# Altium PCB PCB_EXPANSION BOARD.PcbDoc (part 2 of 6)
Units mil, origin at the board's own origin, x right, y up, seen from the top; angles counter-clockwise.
Board outline 5512.34 x 7953.29 mil, 6 copper layers (Top Layer, L2, L3, L4, L5, Bottom Layer); 420 components, 365 nets, 1860 pads, 895 vias.
Unrouted connection lines stored in the file: 9.

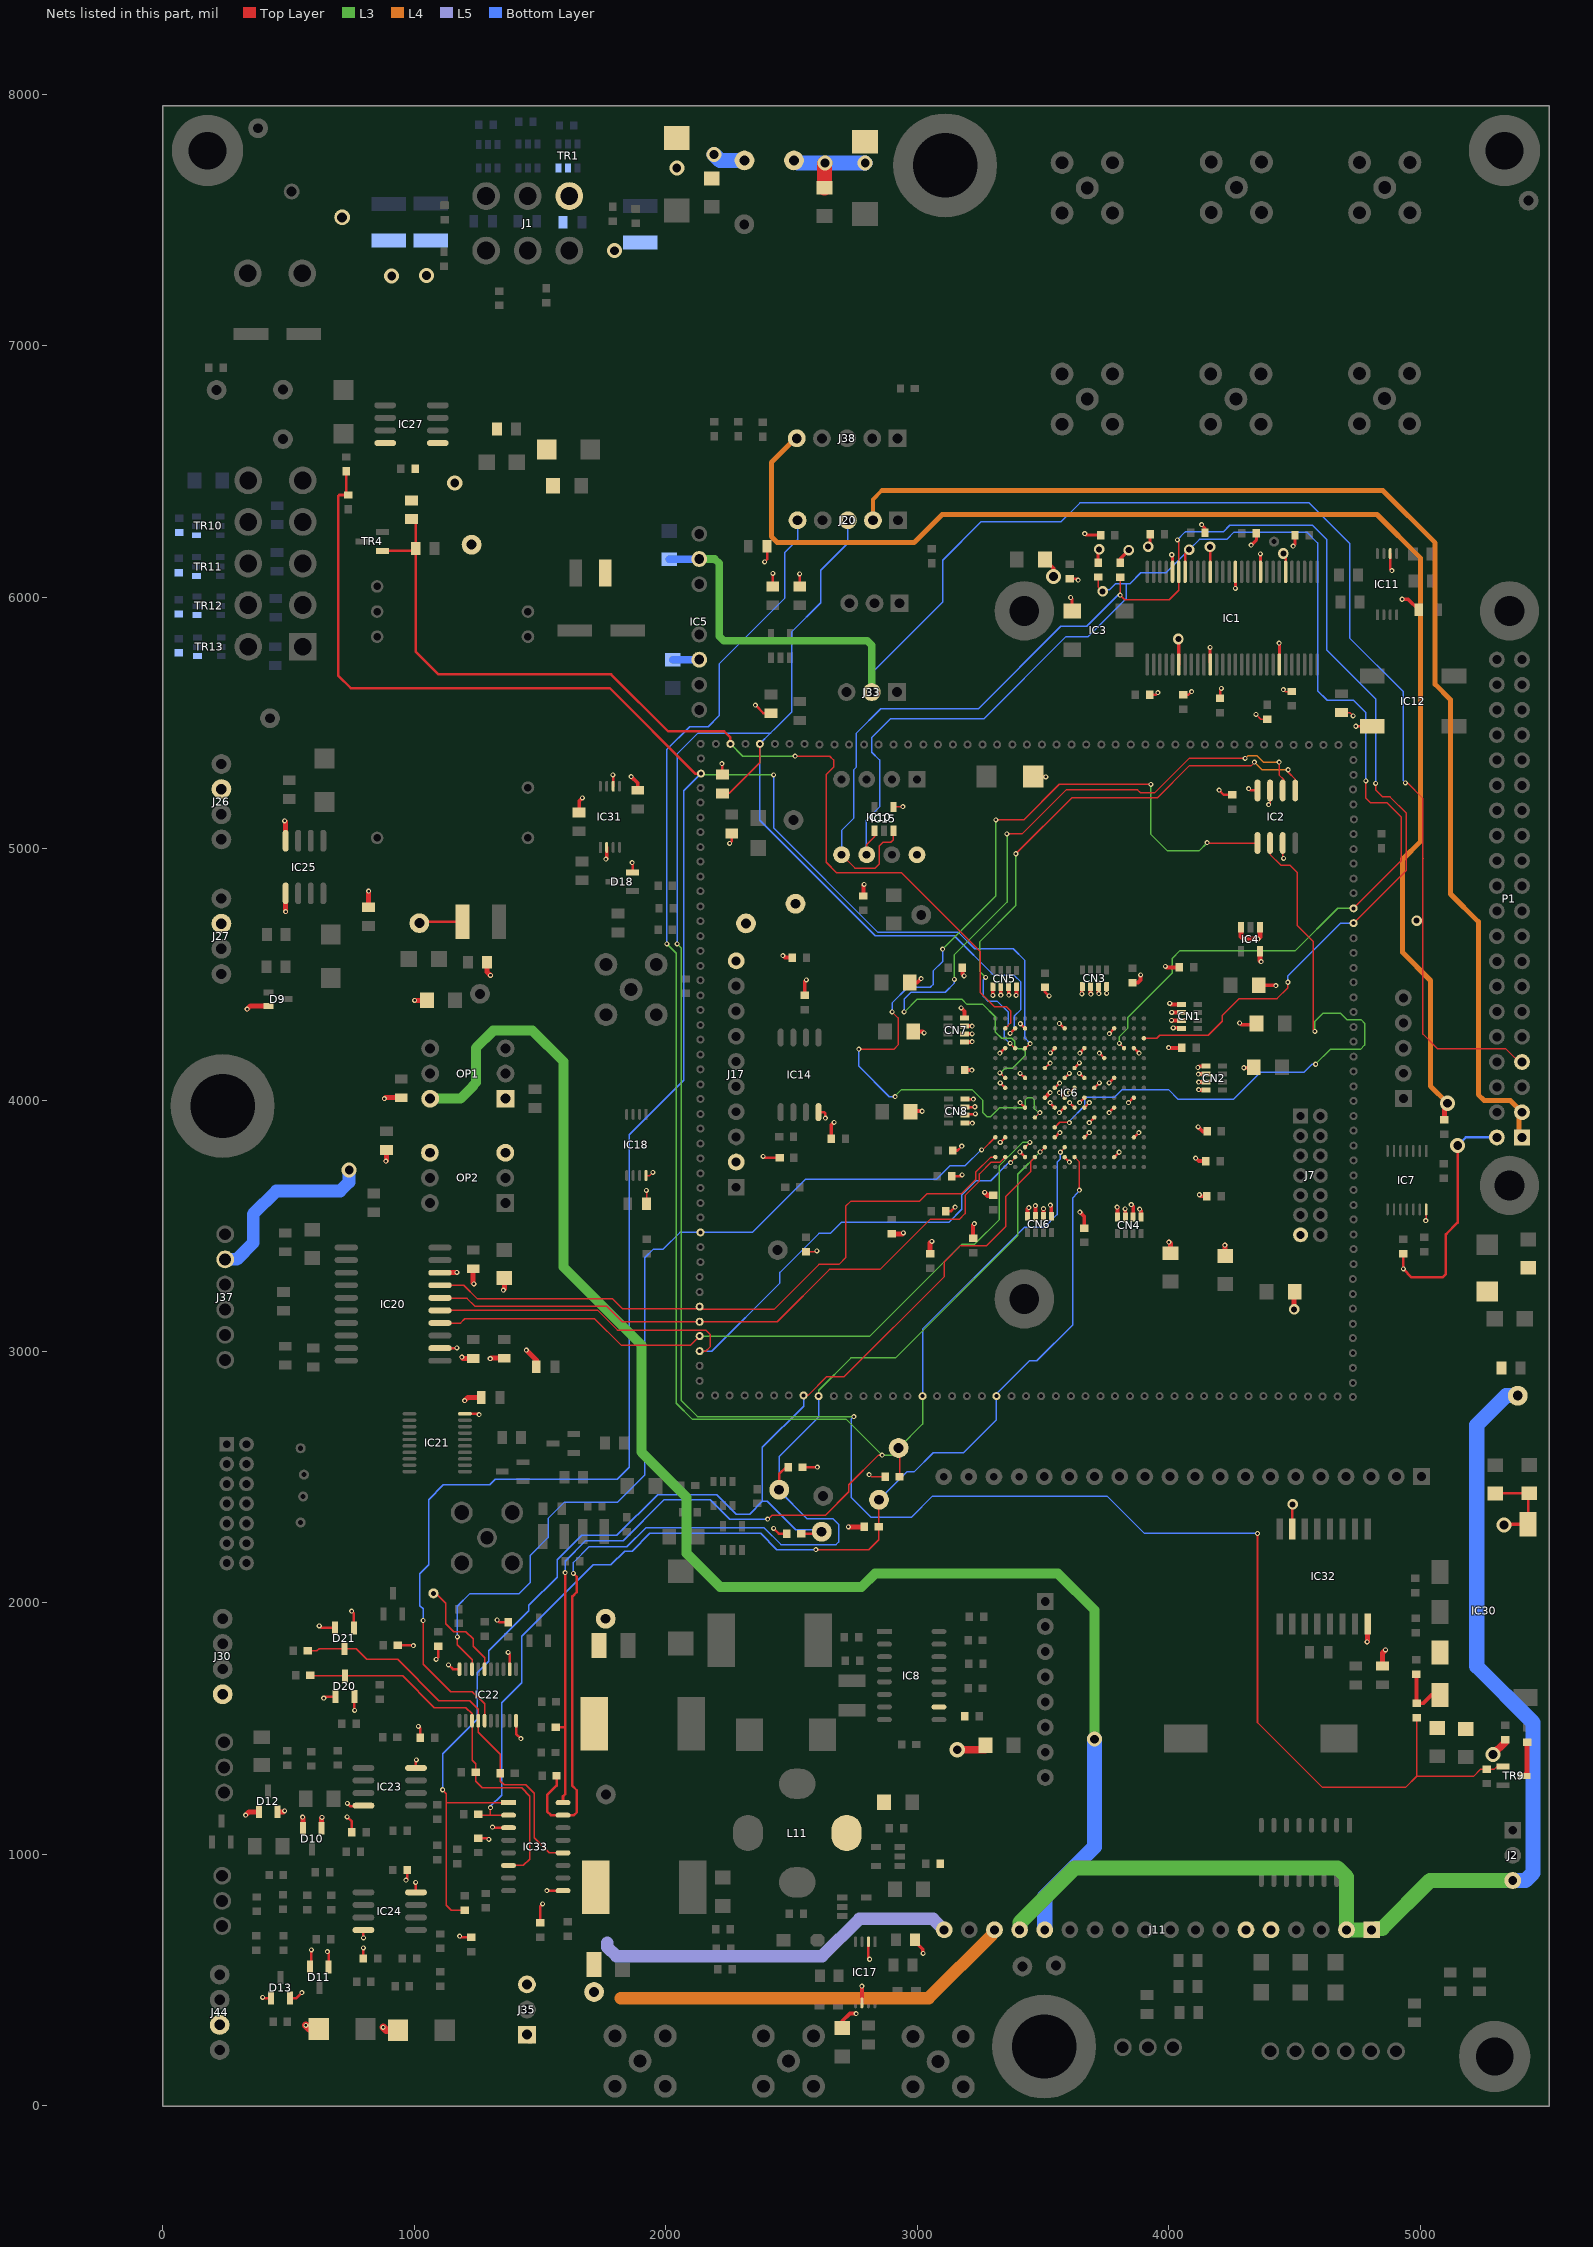
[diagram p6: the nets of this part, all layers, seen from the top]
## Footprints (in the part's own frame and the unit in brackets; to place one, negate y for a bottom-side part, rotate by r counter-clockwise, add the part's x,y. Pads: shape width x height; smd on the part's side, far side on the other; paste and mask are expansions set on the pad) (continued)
SSOP-56 [mil]
  oval 14x89.24 smd: 1(-338,-184) 2(-313,-184) 3(-288,-184) 4(-263,-184) 5(-238,-184) 6(-213,-184) 7(-188,-184) 8(-163,-184) 9(-138,-184) 10(-113,-184) 11(-88,-184) 12(-63,-184) 13(-38,-184) 14(-13,-184) 15(12,-184) 16(37,-184) 17(62,-184) 18(87,-184) 19(112,-184) 20(137,-184) 21(162,-184) 22(187,-184) 23(212,-184) 24(237,-184) 25(262,-184) 26(287,-184) 27(312,-184) 28(337,-184) 29(337,184.38) 30(312,184.38) 31(287,184.38) 32(262,184.38) 33(237,184.38) 34(212,184.38) 35(187,184.38) 36(162,184.38) 37(137,184.38) 38(112,184.38) 39(87,184.38) 40(62,184.38) 41(37,184.38) 42(12,184.38) 43(-13,184.38) 44(-38,184.38) 45(-63,184.38) 46(-88,184.38) 47(-113,184.38) 48(-138,184.38) 49(-163,184.38) 50(-188,184.38) 51(-213,184.38) 52(-238,184.38) 53(-263,184.38) 54(-288,184.38) 55(-313,184.38) 56(-338,184.38)
  silkscreen extent -369,-190 365,131
TEST_HOLE_C2mmD1mm [mm] "Connector; Plug"
  round 2 hole 1: 1(0,0)
  silkscreen extent -1.1,-1.1 1.1,1.1
TSSOP8 [mm] "3*6.4*1.2mm£¨³¤¿í¸ß£©"
  rect 1.1x0.3 smd: 1(-3.088,0.975)
  oval 1.1x0.3 smd: 2(-3.088,0.325) 3(-3.088,-0.325) 4(-3.088,-0.975) 5(3.087,-0.975) 6(3.087,-0.325) 7(3.087,0.325) 8(3.087,0.975)
  silkscreen extent -3.14,-1.27 1.77,2.03
TSSOP14 [mm] "5*6.4*1mm£¨³¤¿í¸ß£©"
  rect 1.2x0.25 smd: 1(-2.95,1.95)
  oval 1.2x0.25 smd: 2(-2.95,1.3) 3(-2.95,0.65) 4(-2.95,0) 5(-2.95,-0.65) 6(-2.95,-1.3) 7(-2.95,-1.95) 8(2.95,-1.95) 9(2.95,-1.3) 10(2.95,-0.65) 11(2.95,0) 12(2.95,0.65) 13(2.95,1.3) 14(2.95,1.95)
  silkscreen extent -3.3,-2.41 1.52,2.67
TSSOP20 [mm] "TSOP, 20-Leads, Body 6.5x4.4mm, Pitch 0.65mm, IPC High Density"
  oval 1.4x0.35 smd: 1(-2.8,2.925) 2(-2.8,2.275) 3(-2.8,1.625) 4(-2.8,0.975) 5(-2.8,0.325) 6(-2.8,-0.325) 7(-2.8,-0.975) 8(-2.8,-1.625) 9(-2.8,-2.275) 10(-2.8,-2.925) 11(2.8,-2.925) 12(2.8,-2.275) 13(2.8,-1.625) 14(2.8,-0.975) 15(2.8,-0.325) 16(2.8,0.325) 17(2.8,0.975) 18(2.8,1.625) 19(2.8,2.275) 20(2.8,2.925)
  silkscreen extent -2.92,-3.3 1.7,3.77
XH2.54-LI-3P [mm] "½Ó²å¼þ£¬3P"
  rect 1.7x1.7 hole 0.9: 1(-2.54,0)
  round 1.7 hole 0.9: 2(0,0) 3(2.54,0)
  silkscreen extent -4.95,-3.38 4.93,2.39

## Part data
C1 C2 C4 C5 C6 C7 C12 C13 C14 C15 C16 C17 C18 C19 C20 C21 C22 C23 C24 C25 C26 C27 C28 C29 C30 C31 C32 C33 C34 C35 C36 C37 C38 C39 C40 C41 C42 C43 C44 C45 C46 C47 C48 C49 C50 C51 C54 C55 C56 C57 C61 C68 C69 C72 C74 C75 C76 C77 C78 C79 C80 C81 C82 C83 C84 C85 C86 C88 C89 C90 C91 C92 C93 C94 C95 C96 C97 C98 C99 C100 C101 C102 C103 C104 C105 C106 C107 C108 C109 C110 C111 C112 C113 C114 C115 C116 C117 C118 C119 C120 C121 C122 C123 C124 C125 C126 C127 C128 C129 C130 C131 C132 C133 C134 C136 C137 C138 C139 C140 C141 C143 C144 C145 C146 C147 C148 C149 C150: library part CAP, "Capacitor"
C67 C70 C71 C135 C142: library part EC, "Electrolytic Capacitor"
CN1 CN2 CN3 CN4 CN5 CN6 CN7 CN8: library part CAP_8
D1 D2 D3 D4 D6 D7 D8: library part DZ
D10 D11 D12 D13 D18 D20 D21: library part BAV99
D14: library part BAV99W
D15 D16 D17: library part DDDDX
F1 F2 F5 F6 F7: library part R_fuse
IC3 IC12: library part JT_4
IC5: library part "TMR 1210"
IC7: library part SN74AHC125PWR_1
IC15: library part DIP5
IC19: library part JCG1212S05
IC21: library part 74AC244MTC
IC23 IC24: library part LM358A
IC28: library part "NMOS+PMOS  SOP6"
IC33: "14PIN 4+ 11- OUT_ 1 7 8 14"
J1: library part COON6X, "Connector"
J2 J12 J31 J33 J35 J42 J43: library part CON3, "Connector"
J5 J9 J13 J18 J19 J21 J22 J34 J39 J41 J45: library part RF_5_1_1
J6 J20 J38: library part CON5, "Connector"
J7 J29: library part COON14X, "Connector"
J8 J37: library part CON6, "Connector"
J10: library part CON20, "Connector"
J11: library part CON18, "Connector"
J17 J25: library part CON10, "Connector"
J24: library part CON2, "Connector"
J26 J27 J30 J44: library part CON4, "Connector"
J32: library part CON8, "Connector"
J40: library part BATTERY, "Battery"
L1 L3 L5 L7 L8 L9 L10: library part LLL1
L4 L6: library part LLL2
L11: library part UU9.8
LED1 LED2 LED3 LED4 LED5 LED6 LED7: library part LEDA
OP1 OP2: library part H11L1S1(TA)-V
P1: library part COON40X, "Connector"
R1 R2 R3 R4 R5 R6 R7 R8 R9 R10 R11 R12 R13 R14 R15 R16 R17 R18 R19 R20 R21 R22 R23 R24 R25 R26 R27 R28 R29 R30 R31 R32 R33 R34 R35 R36 R37 R38 R39 R42 R43 R44 R45 R46 R47 R48 R49 R50 R52 R53 R54 R55 R56 R57 R58 R59 R60 R61 R62 R63 R64 R65 R66 R67 R68 R69 R70 R71 R72 R73 R74 R75 R76 R77 R78 R79 R80 R81 R82 R83 R84 R85 R86 R87 R88 R89 R90 R91 R92 R93 R94 R95 R96 R97 R98 R99 R100 R101 R102 R103 R104 R105 R106 R107 R108 R109 R110 R111 R112 R113 R114 R115 R116 R117 R118 R119 R120 R123 R124 R125 R126 R127 R128 R130 R131 R132 R133 R218: library part R_XIAO
TP1 TP2 TP4 TP5 TP6 TP7 TP8 TP9 TP10 TP11 TP12 TP13 TP14 TP15 TP16 TP17 TP18 TP19 TP20 TP21 TP22 TP24 TP25 TP111: library part TTT_DWK1

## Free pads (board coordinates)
  round 0.25 on Keep-Out: 1(0,0) 1(0,0) 1(0,3976.38) 1(0,7952.76) 1(0,7952.76) 1(413.39,7952.76) 1(2755.91,0) 1(2755.91,6.38) 1(2755.91,7946.38) 1(2755.91,7952.76) 1(3110.24,7952.76) 1(3503.94,0) 1(5295.28,0) 1(5509.41,3976.38) 1(5511.81,0) 1(5511.81,0) 1(5511.81,0) 1(5511.81,0) 1(5511.81,3976.38) 1(5511.81,7952.76) 1(5511.81,7952.76) 1(5511.81,7952.76) 1(5511.81,7952.76) 1(5511.81,7952.76)
  round 283.46 hole 149.61: 1(177.17,7775.59) 1(5295.28,196.85) 1(5334.65,7775.59)
  round 413.39 hole 255.91: 1(237.41,3976.38) 1(3110.24,7716.54) 1(3503.94,236.22)
  round 40 hole 20: 1(547.41,2320.38) 1(547.41,2615.38) 1(557.41,2423.38) 1(560.41,2510.38) 1(1075.41,2038.38) 1(4418.41,6220.38)
  round 32 hole 16: 1(2134.41,2883.38) 1(2134.41,2943.38) 1(2134.41,3001.38) 1(2134.41,3061.38) 1(2134.41,3118.38) 1(2134.41,3178.38) 1(2134.41,3236.38) 1(2134.41,3296.38) 1(2135.41,2825.38) 1(2137.41,3355.38) 1(2137.41,3415.38) 1(2137.41,3473.38) 1(2137.41,3533.38) 1(2137.41,3590.38) 1(2137.41,3650.38) 1(2137.41,3708.38) 1(2137.41,3768.37) 1(2137.41,3826.38) 1(2137.41,3886.38) 1(2137.41,3944.37) 1(2137.41,4004.38) 1(2137.41,4062.38) 1(2137.41,4122.38) 1(2137.41,4180.38) 1(2137.41,4240.37) 1(2137.41,4298.38) 1(2137.41,4358.38) 1(2137.41,4416.37) 1(2137.41,4476.38) 1(2137.41,4533.38) 1(2137.41,4593.38) 1(2137.41,4651.38) 1(2137.41,4711.38) 1(2137.41,4770.38) 1(2137.41,4830.38) 1(2137.41,4888.37) 1(2137.41,4948.38) 1(2137.41,5005.38) 1(2137.41,5065.38) 1(2137.41,5123.38) 1(2137.41,5183.38) 1(2138.41,5241.38) 1(2138.41,5416.37) 1(2139.41,5298.38) 1(2139.41,5358.38) 1(2195.41,2825.38) 1(2198.41,5416.37) 1(2253.41,2825.38) 1(2256.41,5416.37) 1(2313.41,2825.38) 1(2316.41,5416.37) 1(2370.41,2825.38) 1(2373.41,5416.37) 1(2430.41,2825.38) 1(2433.41,5416.37) 1(2488.41,2825.38) 1(2491.41,5416.37) 1(2547.41,2825.38) 1(2551.41,5416.37) 1(2607.41,2822.38) 1(2610.41,5413.38) 1(2667.41,2822.38) 1(2670.41,5413.38) 1(2725.41,2822.38) 1(2728.41,5413.38) 1(2785.41,2822.38) 1(2788.41,5413.38) 1(2842.41,2822.38) 1(2845.41,5413.38) 1(2902.41,2822.38) 1(2905.41,5413.38) 1(2960.41,2822.38) 1(2963.41,5413.38) 1(3020.41,2822.38) 1(3023.41,5413.38) 1(3078.41,2822.38) 1(3081.41,5413.38) 1(3138.41,2822.38) 1(3141.41,5413.38) 1(3196.41,2822.38) 1(3199.41,5413.38) 1(3256.41,2822.38) 1(3259.41,5413.38) 1(3314.41,2822.38) 1(3317.41,5413.38) 1(3374.41,2822.38) 1(3377.41,5413.38) 1(3432.41,2822.38) 1(3435.41,5413.38) 1(3492.41,2822.38) 1(3495.41,5413.38) 1(3550.41,2822.38) 1(3553.41,5413.38) 1(3610.41,2822.38) 1(3613.41,5413.38) 1(3668.41,2822.38) 1(3671.41,5413.38) 1(3728.41,2822.38) 1(3731.41,5413.38) 1(3785.41,2822.38) 1(3788.4,5413.38) 1(3845.41,2822.38) 1(3848.41,5413.38) 1(3903.41,2822.38) 1(3906.41,5413.38) 1(3963.41,2822.38) 1(3966.41,5413.38) 1(4022.41,2822.38) 1(4025.41,5413.38) 1(4082.41,2822.38) 1(4085.41,5413.38) 1(4140.4,2822.38) 1(4143.41,5413.38) 1(4200.41,2822.38) 1(4203.41,5413.38) 1(4257.41,2822.38) 1(4260.4,5413.38) 1(4317.41,2822.38) 1(4320.41,5413.38) 1(4375.41,2822.38) 1(4378.41,5413.38) 1(4435.41,2822.38) 1(4438.41,5413.38) 1(4493.41,2821.38) 1(4496.41,5412.38) 1(4553.41,2821.38) 1(4556.4,5412.38) 1(4611.41,2821.38) 1(4614.41,5412.38) 1(4671.41,2821.38) 1(4674.41,5412.38) 1(4731.41,2819.38) 1(4731.41,2875.38) 1(4731.41,2935.38) 1(4731.41,2993.38) 1(4731.41,3053.38) 1(4731.41,3110.38) 1(4731.41,3170.38) 1(4731.41,3228.38) 1(4731.41,3288.38) 1(4732.4,5235.38) 1(4733.41,5175.38) 1(4733.41,5352.37) 1(4734.41,3347.38) 1(4734.41,3407.38) 1(4734.41,3465.38) 1(4734.41,3525.38) 1(4734.41,3582.38) 1(4734.41,3642.38) 1(4734.41,3700.38) 1(4734.41,3760.37) 1(4734.41,3818.38) 1(4734.41,3878.38) 1(4734.41,3936.37) 1(4734.41,3996.38) 1(4734.41,4054.38) 1(4734.41,4114.38) 1(4734.41,4172.38) 1(4734.41,4232.37) 1(4734.41,4290.38) 1(4734.41,4350.38) 1(4734.41,4408.37) 1(4734.41,4468.38) 1(4734.41,4525.38) 1(4734.41,4585.38) 1(4734.41,4643.38) 1(4734.41,4703.38) 1(4734.41,4762.38) 1(4734.41,4822.38) 1(4734.41,4880.37) 1(4734.41,4940.38) 1(4734.41,4997.38) 1(4734.41,5057.38) 1(4734.41,5293.38) 1(4734.41,5412.38) 1(4735.41,5116.38)
  round 236.22 hole 118.11: 1(3425.2,3208.66) 1(3425.2,5944.88) 1(5354.33,5944.88) 1(5354.41,3660.38)
  round 0.25 on Mech1: 1(5295.28,3661.42)
  round 0.5 on Mech1: 1(5509.41,7946.38) 1(5509.41,7946.38)

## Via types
v1: diameter 20, hole 10, Top Layer to Bottom Layer, tented both sides, 808 vias
v2: diameter 60, hole 35, Top Layer to Bottom Layer, 47 vias
v3: diameter 42, hole 24, Top Layer to Bottom Layer, 32 vias
v4: diameter 125.98/125.98/125.98/125.98/125.98/125.98 (per signal layer), hole 125.98, Top Layer to Bottom Layer, 6 vias
v5: diameter 51.18, hole 51.18, Top Layer to Bottom Layer, 2 vias

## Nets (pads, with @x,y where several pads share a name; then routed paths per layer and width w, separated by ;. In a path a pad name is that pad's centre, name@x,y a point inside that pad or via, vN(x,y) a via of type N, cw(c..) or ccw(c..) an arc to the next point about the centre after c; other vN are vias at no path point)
3V: P1.2 R5.2 | length 939.1
  Top Layer w6: 5108.4,3472.38 5112.41,3476.38
  Top Layer w10: v1@4932.4,3327.38 4965.41,3294.38 5087.41,3294.38 5101.41,3308.38 5101.41,3465.38 ; v1(4932.4,3328.38) R5.2@4932.4,3388.83 ; 5104.41,3468.38 5148.4,3512.38 v2(5148.4,3819.38)
  Top Layer w15: v1@4932.4,3327.38 v1(4932.4,3328.38)
  Bottom Layer w10: v2(5148.4,3819.38) 5180.4,3851.38 P1.2@5292.41,3851.38
3V3: C1.1 C2.2 C4.2 C5.2 C6.2 C7.2 C12.1 C13.2 C14.2 C15.1 C18.1 C20.2 C21.1 C22.1 C25.1 C29.2 C32.2 C34.1 C35.2 C39.2 C42.1 C48.2 C50.2 C51.1 C57.1 C75.2 C76.2 C77.2 C78.2 C80.1 C81.1 C125.1 C126.2 C134.2 CN1.5 CN1.6 CN1.7 CN1.8 CN2.5 CN2.6 CN2.7 CN2.8 CN3.1 CN3.2 CN3.3 CN3.4 CN4.5 CN4.6 CN4.7 CN4.8 CN5.1 CN5.2 CN5.3 CN5.4 CN6.5 CN6.6 CN6.7 CN6.8 CN7.1 CN7.2 CN7.3 CN7.4 CN8.1 CN8.2 CN8.3 CN8.4 D1.1 D18.2 IC1.6 IC1.10 IC1.14 IC1.18 IC1.24 IC1.34 IC1.39 IC1.50 IC2.3 IC2.7 IC2.8 IC3.4 IC4.1 IC4.3 IC5.6 IC6.B4 IC6.B9 IC6.B13 IC6.D2 IC6.D7 IC6.D10 IC6.D15 IC6.E5 IC6.F8 IC6.F11 IC6.G4 IC6.G10 IC6.G13 IC6.H6 IC6.J2 IC6.J10 IC6.J15 IC6.K4 IC6.K13 IC6.L6 IC6.L9 IC6.N2 IC6.N7 IC6.N10 IC6.N15 IC6.R4 IC6.R8 IC6.R13 IC7.14 IC10.8 IC11.6 IC12.4 IC14.8 IC15.4 IC17.2 IC17.6 IC18.8 IC20.2 IC20.8 IC21.20 IC31.2 IC31.6 IC32.16 J7.13 J11.5 J11.6 J17.2 J17.10 OP1.1 OP2.3 R4.2 R9.1 R10.2 R11.2 R20.1 R21.1 R24.1 R25.2 R26.1 R27.1 R29.1 R31.2 R36.2 R45.1 R46.1 R74.1 R97.1 R101.1 R104.2 TP5.1 | length 6788.2
  Top Layer w6: IC18.8@1920.79,3699.82 1935.85,3699.82 v1(1948.41,3712.37) ; v1(1922.41,3640.38) 1923.1,3639.68 C134.2@1923.1,3586.98 ; R31.2@2556.86,3396.83 2596.86,3396.83 v1(2600.41,3400.38) ; v1(2808.41,2510.38) 2817.41,2501.38 R45.1@2871.86,2501.38 ; IC15.4@2904.21,5165.38 2941.41,5165.38 v1(2942.41,5166.38) ; IC6.R4@3348.31,4206.28 IC6.R4@3349.21,4206.28 ; IC6.N7@3426.6,4088.17 IC6.N7@3427.91,4088.17 ; IC6.L6@3506.71,4127.48 IC6.L6@3508.5,4127.48 ; IC6.G4@3664.2,4204.17 IC6.G4@3664.2,4206.28 ; IC6.D7@3782.21,4088.17 IC6.D7@3782.3,4088.17 ; v1@4163.41,5799.38 v1(4164.4,5800.37) ; v1(4346.41,5533.38) 4365.34,5514.45 R9.1@4390.41,5514.45 ; v1(4363.41,6171.38) v1@4364.4,6170.38 ; v1(4396.4,5174.38) 4402.61,5180.58 IC2.7@4402.61,5231.07 ; IC2.3@4452.61,5022.09 4452.61,4965.18 v1(4456.41,4961.38) ; v1(4455.41,5632.37) 4463.25,5624.53 C2.2@4489.41,5624.53 ; C32.2@4686.4,5540.98 4718.8,5540.98 v1(4732.4,5527.38) ; v1(5021.41,3520.38) 5023.18,3522.15 IC7.14@5023.18,3565.24
  Top Layer w10: IC20.2@1101.41,3013.38 1167.41,3013.38 v1(1168.41,3014.38) ; IC21.20@1200.64,2752.53 1254.25,2752.53 v1(1257.41,2749.38) ; v1(1789.41,5293.38) 1790.2,5292.58 IC31.6@1790.2,5247.93 ; v1(1865.41,4944.37) 1867.64,4942.14 D18.2@1867.64,4905.48 ; v1(2222.41,5337.38) 2224.41,5335.38 R74.1@2224.41,5294.38 ; v1(2253.41,5020.38) 2262.01,5028.98 R4.2@2262.01,5059.98 ; v1(2355.41,5570.38) 2387.81,5537.98 R25.2@2418.01,5537.98 ; v1@2392.41,3770.38 R29.1@2451.86,3770.38 ; v1(2392.41,6140.38) 2402.41,6150.38 2402.41,6209.38 C50.2@2403.41,6210.38 ; R24.1@2425.01,6042.18 v1(2425.01,6094.38) ; v1(2428.41,2296.38) 2449.41,2275.38 R101.1@2480.86,2275.38 ; R20.1@2531.41,6043.18 v1(2531.41,6092.37) ; R104.2@2542.95,2540.38 v1(2602.41,2540.38) ; IC14.8@2606.41,3952.03 2628.75,3952.03 2634.41,3946.38 v1(2634.41,3928.37) ; IC17.6@2779.41,410.32 IC17.6@2779.61,410.52 ; v1(2779.41,476.38) v1@2779.61,476.17 ; IC17.2@2805.2,652.93 2805.2,588.58 v1(2810.41,583.38) ; C39.2@3112.95,3558.38 3134.41,3558.38 v1(3150.41,3574.38) ; CN8.1@3188.89,3909.13 3217.66,3909.13 v1(3218.41,3908.38) ; CN8.3@3188.89,3972.12 3227.16,3972.12 v1(3228.41,3973.38) ; CN8.2@3198.41,3944.37 3229.41,3944.37 v1(3230.41,3945.38) ; CN8.4@3199.41,4002.38 3221.41,4002.38 v1(3222.41,4003.38) ; v1(3328.41,4186.38) IC6.R4@3348.31,4206.28 ; v1(3329.41,3831.38) 3329.41,3831.73 3349.21,3851.53 IC6.R13@3349.21,3851.87 ; v1(3329.41,4068.38) 3329.5,4068.38 3349,4048.88 3349,4048.78 IC6.R8@3349.21,4048.78 ; v1(3407.41,3793.38) 3407.55,3793.38 3427.6,3773.33 3427.6,3773.17 IC6.N15@3427.91,3773.17 ; v1(3408.41,4106.38) 3409.05,4106.38 3426.6,4088.83 IC6.N7@3426.6,4088.17 ; v1(3408.41,3989.38) IC6.N10@3427.91,3969.98 ; v1(3409.41,4303.38) 3427.81,4284.98 IC6.N2@3427.91,4284.98 ; D1.1@3460.34,5286.38 3461.34,5285.38 v1(3510.41,5285.38) ; IC6.L6@3508.5,4127.48 3508.5,4128.38 3526.51,4146.38 v1(3527.41,4146.38) ; v1(3528.41,4187.38) 3546.01,4204.98 IC6.K4@3546.01,4206.28 ; IC6.K13@3546.01,3851.87 3546.95,3851.87 3565.46,3870.38 v1(3566.41,3870.38) ; v1(3564.41,3950.38) 3584.01,3969.98 IC6.J10@3585.41,3969.98 ; v1(3564.41,4304.37) 3565.21,4304.37 3584.6,4284.98 IC6.J2@3585.41,4284.98 ; IC6.J15@3585.41,3773.17 3585.41,3772.38 v1(3604.41,3753.38) ; C22.1@3605.41,6072.83 3633.95,6072.83 v1(3639.41,6067.38) ; IC6.H6@3624.8,4127.48 3624.8,4127.63 3644.41,4147.23 v1(3644.41,4147.38) ; v1(3646.41,4186.38) 3646.41,4187.43 3663.15,4204.17 IC6.G4@3664.2,4204.17 ; IC6.G13@3664.2,3851.87 3664.91,3851.87 v1(3683.41,3870.38) ; IC6.G10@3664.2,3969.98 3664.2,3970.18 v1(3683.41,3989.38) ; v1(3683.41,3910.38) 3683.41,3910.48 3703.51,3930.58 IC6.F11@3703.51,3930.68 ; IC6.F8@3703.51,4048.78 3703.81,4048.78 v1(3723.41,4068.38) ; v1(3723.41,4186.38) IC6.E5@3742.91,4166.88 ; v1(3762.41,3950.38) 3782,3969.98 IC6.D10@3782.3,3969.98 ; v1(3762.41,4068.38) 3762.46,4068.38 IC6.D7@3782.21,4088.13 ; v1(3763.41,4264.37) 3763.41,4265.23 3782.3,4284.12 IC6.D2@3782.3,4284.98 ; IC6.D15@3782.3,3773.17 3783.21,3773.17 v1(3802.41,3792.37) ; v1(3839.41,3989.38) 3859.41,4009.38 IC6.B9@3861,4009.38 ; IC6.B13@3861,3851.87 3861.91,3851.87 v1(3880.41,3870.38) ; IC6.B4@3861,4206.28 3861.26,4206.28 3881.15,4186.38 v1(3881.41,4186.38) ; C13.2@3923.95,5611.38 3947.41,5611.38 v1(3956.4,5620.38) ; v1(4011.41,6168.37) 4011.41,6165.67 v1@4014.41,6162.67 ; C14.2@4057.41,5610.92 4076.94,5610.92 v1(4090.41,5624.37) ; v3(4163.41,6199.38) 4164.4,6198.38 IC1.18@4164.4,6100.38 ; v1(4199.41,5232.37) 4217.86,5213.92 C15.1@4252.4,5213.92 ; C7.2@4203.41,5597.92 4203.41,5632.37 v1(4208.41,5637.38) ; v1(4317.41,5238.38) 4324.71,5231.07 IC2.8@4352.61,5231.07 ; v3(4455.41,6173.38) 4464.41,6164.38 IC1.6@4464.41,6100.38 ; v1(4743.41,5486.38) IC12.4@4808.8,5486.38 ; IC11.6@4880.2,6172.93 4880.2,6111.58 v1(4886.41,6105.38)
  Top Layer w12: v1(3609.41,5998.38) 3615.46,5992.32 IC3.4@3615.46,5944.15 ; v1(3665.41,6252.38) 3671.41,6246.38 C21.1@3728.41,6246.38 ; R10.2@3718.41,6136.92 3718.41,6185.38 v3(3722.41,6189.38) ; R11.2@3806.41,6135.92 3806.41,6152.37 v3(3840.41,6186.38) ; v3(3917.41,6200.37) 3925.41,6208.37 C12.1@3925.41,6250.38 ; IC1.24@4014.41,6100.38 v1@4014.41,6162.67 ; v1(4129.93,6287.74) 4143.5,6274.17 C5.2@4143.5,6255.38 ; IC1.39@4163.41,5739.38 v1@4163.41,5799.38 ; v1(4264.41,6034.38) IC1.14@4264.41,6100.38 ; v1(4327.41,6206.38) 4347.5,6226.47 C6.2@4347.5,6253.38 ; IC1.10@4364.4,6100.38 v1@4364.4,6170.38 ; v1(4438.41,5817.38) 4439.41,5816.37 IC1.50@4439.41,5732 ; v1(4494.41,6202.38) 4501.41,6209.38 C1.1@4501.41,6246.38
  Top Layer w15: R97.1@1655.01,5143.78 1655.01,5188.98 v1(1667.41,5201.38) ; v1(1761.41,4958.38) 1764.61,4961.58 IC31.2@1764.61,5004.82 ; v1(1861.41,5286.38) 1888.4,5259.38 C125.1@1888.4,5231.78 ; v1(2465.41,4574.38) 2473.41,4566.38 R26.1@2501.86,4566.38 ; R27.1@2552.41,4416.92 2552.41,4471.38 v1(2558.41,4477.38) ; C51.1@2657.03,3846.38 2657.03,3900.01 v1(2668.41,3911.38) ; C4.2@2701.41,309.47 2701.41,337.38 2731.41,367.38 v1(2756.41,367.38) ; IC17.6@2779.61,410.52 v1@2779.61,476.17 ; R21.1@2785.41,4811.47 2785.41,4854.38 v1(2788.41,4857.38) ; R36.2@2989.81,660.98 2989.81,655.07 3021.45,623.43 3021.45,607.33 v1(3022.41,606.38) ; v1(3173.41,4366.38) 3186.89,4352.9 CN7.4@3186.89,4325.63 ; C35.2@3178.95,4525.38 3178.95,4499.84 v1(3185.41,4493.38) ; CN7.1@3186.89,4231.13 3216.16,4231.13 v1(3217.41,4232.37) ; CN7.3@3186.89,4294.13 3217.16,4294.13 v1(3217.41,4294.38) ; CN7.2@3191.41,4263.38 v1(3217.41,4263.38) ; CN5.1@3299.91,4450.38 3299.91,4416.88 v1(3300.41,4416.37) ; v1(3331.41,4417.38) CN5.2@3331.41,4450.38 ; CN5.3@3362.91,4450.38 3362.91,4417.88 v1(3363.41,4417.38) ; v1(3392.41,4416.37) 3394.41,4418.38 CN5.4@3394.41,4450.38 ; CN6.8@3438.16,3537.86 3438.16,3567.13 v1(3443.41,3572.38) ; v1(3469.41,3580.38) 3469.66,3580.13 CN6.7@3469.66,3537.86 ; CN6.6@3501.16,3537.86 3501.16,3568.13 v1(3501.41,3568.38) ; IC6.L9@3506.71,4009.38 3507.41,4009.38 v1(3527.41,4029.38) ; C29.2@3506.99,6149.38 3541.41,6114.97 v2(3541.41,6082.38) ; v1(3528.41,3582.38) 3532.66,3578.13 CN6.5@3532.66,3537.86 ; CN3.1@3653.41,4457.38 3653.41,4423.38 v1(3654.41,4422.38) ; CN3.2@3688.66,4451.89 3688.66,4422.13 v1(3689.41,4421.38) ; CN3.3@3720.15,4451.89 3720.15,4424.63 v1(3721.41,4423.38) ; v1(3794.41,3574.38) 3795.16,3573.63 CN4.8@3795.16,3534.86 ; v1(3826.41,3567.38) 3826.66,3567.13 CN4.7@3826.66,3534.86 ; v1(3850.41,3584.38) 3858.16,3576.63 CN4.6@3858.16,3534.86 ; v1(3883.41,3566.38) 3889.66,3560.13 CN4.5@3889.66,3534.86 ; v1(4003.41,4384.37) 4008.15,4379.62 CN1.5@4049.93,4379.62 ; v1(4010.41,4316.38) 4010.66,4316.63 CN1.7@4049.93,4316.63 ; v1(4011.41,4348.38) 4011.65,4348.12 CN1.6@4049.93,4348.12 ; v1(4017.41,4287.38) CN1.8@4043.41,4287.38 ; v3(4037.41,5833.38) 4039.41,5831.38 IC1.34@4039.41,5732 ; v1(4115.41,4129.38) 4120.66,4134.63 CN2.5@4147.93,4134.63 ; v1(4116.4,3893.38) 4134.41,3875.38 C25.1@4151.87,3875.38 ; v1(4117.41,4103.13) CN2.6@4147.93,4103.13 ; v1(4118.41,4041.38) 4119.65,4040.12 CN2.8@4147.93,4040.12 ; v1(4118.41,4071.38) 4118.66,4071.62 CN2.7@4147.93,4071.62 ; v1(4298.41,4128.37) C18.1@4345.41,4128.37 ; v1(4927.41,5991.38) 4951.41,5991.38 4993.41,5949.38 C42.1@4993.6,5949.38
  Top Layer w20: IC20.8@1101.41,3313.38 1167.41,3313.38 v1(1168.41,3314.38) ; v1(1188.41,2977.38) 1193.3,2972.48 C77.2@1234.4,2972.48 ; v1(1199.41,2804.38) 1212.07,2817.05 C80.1@1265.53,2817.05 ; C75.2@1233.4,3328.98 1233.4,3272.38 v1(1236.41,3269.38) ; v1(1301.41,2971.38) 1303.51,2973.48 C78.2@1357.4,2973.48 ; v1(1353.41,3244.38) 1357.41,3248.38 C76.2@1357.41,3291.79 ; v1(1445.41,3005.38) 1484.53,2966.26 C81.1@1484.53,2938.99 ; v1(2725.41,2302.38) R46.1@2788.86,2302.38 ; C48.2@2898.41,3467.83 2940.86,3467.83 v1(2944.41,3471.38) ; v1(3267.41,3632.38) 3278.86,3620.92 C34.1@3301.41,3620.92 ; IC4.3@4287.6,4686.38 4287.6,4650.18 4299.41,4638.38 v1(4300.4,4638.38) 4302.41,4640.37 v1(4353.41,4640.37) 4362.41,4649.38 IC4.1@4362.41,4686.38 ; v3(4498.41,3167.38) 4498.41,3235.29 C20.2@4500.49,3237.38 ; v1(4788.4,1845.38) 4790.41,1847.38 IC32.16@4790.41,1916.4 ; C126.2@4849.34,1749.83 4849.34,1801.31 v1(4861.41,1813.38)
  Bottom Layer w30: C57.1@2027.41,5750.49 2028.29,5751.38 IC5.6@2132.41,5751.38
  other v1: 2386.41,3776.37 3752.41,4424.37
5V: J38.5 R1.1 | length 5489
  Top Layer w20: R1.1@5095.41,3920.92 5095.41,3974.38 v2(5108.4,3987.38)
  L4 w20: J38.5@2520.41,6631.38 2515.19,6631.38 2419.46,6535.65 2419.46,6240.14 2442.72,6216.88 2987.16,6216.88 3098.66,6328.38 4827.6,6328.38 5001.07,6154.92 5001.07,5028.76 4928.9,4956.6 4928.9,4587.16 5040.5,4475.57 5040.5,4055.28 v2(5108.4,3987.38)
12V: C49.2 J1.1 TR1.2 TR1.3
12V_EXT: C74.1 C79.2 D9.2 F1.1 IC25.1 IC25.8 J11.14 J26.2 J27.2 J37.5 OP1.6 OP2.4 R53.2 R58.1 R61.2 TP14.1 | length 7490.1
  Top Layer w10: TP14.1@1019.41,4703.38 1025.41,4709.38 F1.1@1190.44,4709.38
  Top Layer w20: v1(334.41,4361.38) 347.41,4374.38 D9.2@419.41,4374.38 ; v1(483.41,5110.38) 487.6,5106.18 IC25.8@487.6,5031.07 ; v1(487.41,4749.38) 487.6,4749.58 IC25.1@487.6,4822.09 ; v1(817.41,4830.38) 818.01,4829.78 R58.1@818.01,4766.78 ; v1(880.41,4005.38) 884.41,4009.38 C79.2@947.41,4009.38 ; v1(886.41,3757.38) 889.01,3759.98 R61.2@889.01,3800.98 ; v1(1000.41,4396.38) C74.1@1049.29,4396.38 ; R53.2@1287.81,4547.98 1287.81,4509.98 v1(1302.41,4495.38)
  L3 w20: v1(483.41,5110.38) v1@487.41,5106.38
  L3 w40: OP1.6@1062.41,4005.38 1182.98,4005.38 1232.41,4054.81 1232.41,4058.09 1245.1,4070.78 1245.1,4207.77 1313.14,4275.81 1469.57,4275.81 1592.41,4152.98 1592.41,3336.38 1902.41,3026.38 1902.41,2599.81 2082.41,2419.81 2082.41,2196.38 2215.58,2063.2 2777.98,2063.2 2831.58,2116.8 3559.3,2116.8 3704.41,1971.69 v2(3704.41,1458.38)
  Bottom Layer w50: J37.5@247.41,3366.38 293.41,3366.38 358.81,3431.78 358.81,3546.18 451.01,3638.38 704.41,3638.38 739.66,3673.63 739.66,3720.63 v2(740.41,3721.38)
  Bottom Layer w60: J11.14@3506.41,700.38 3506.41,832.38 3704.41,1030.38 v2(3704.41,1458.38)
12V_EXT_EN: IC6.R2 pad.1@2256.41,5416.37 R34.1 R35.1 TR4.1 | length 4626.9
  Top Layer w6: 1095.41,5692.38 1598.41,5692.38 ; v1(2513.41,5367.38) 2651.41,5367.38 2666.41,5352.37 2666.41,5323.38 2637.41,5294.38 2637.41,4945.38 2679.41,4903.38 2937.41,4903.38 3249.41,4591.38 3249.41,4428.38 3307.41,4370.38 3355.41,4370.38 3370.41,4355.38 3370.41,4306.18 IC6.R2@3349.21,4284.98
  Top Layer w10: TR4.1@873.08,6183.98 996,6183.98 R35.1@1005,6192.98 ; R34.1@988.8,6309.98 1005,6293.78 R35.1@1005,6192.98 ; 1598.41,5692.38 1627.41,5692.38 ; pad.1@2256.41,5416.37 2256.41,5441.38 2231.41,5466.38 2008.41,5466.38 1782.41,5692.38 1627.41,5692.38 ; R35.1@1005,6192.98 1005,5782.78 1095.41,5692.38 1627.41,5692.38
  L3 w6: pad.1@2256.41,5416.37 2305.41,5367.38 v1(2513.41,5367.38)
12V_OUT: C67.1 C68.1 F5.1 F6.1 F7.1 L5.1 | length 130.5
  Bottom Layer w60: v2(2191.41,7759.38) 2214.41,7736.37 L5.1@2312.41,7736.37
  other v2: 909.41,7276.38 1047.41,7278.38 1795.41,7377.38 2043.41,7706.38
12V_POWER: C56.1 C69.1 C70.1 C112.1 C113.2 C122.1 C124.1 C137.1 C149.1 C150.1 D6.1 F2.1 IC5.2 IC8.10 IC27.1 IC27.8 IC30.2 J30.4 J33.2 L5.2 L6.2 L11.2 P1.7 R34.2 R52.1 R75.1 R76.1 R77.1 R78.1 R95.2 R125.2 TP12.1 TR10.4 TR11.4 TR12.4 TR13.4 | length 7214.4
  Top Layer w6: v1(4940.4,5261.38) 4948.4,5261.38 5010.41,5199.38 5010.41,4960.37 ; v3(4985.41,4713.38) 4986.41,4712.37 5010.41,4712.37 ; 5011.41,4959.38 5010.41,4960.37 ; P1.7@5392.41,4151.38 5340.4,4203.38 5069.41,4203.38 5010.41,4262.38 5010.41,4712.37 ; 5010.41,4712.37 5010.41,4960.37
  Top Layer w10: C124.1@5298.41,2435.26 5314.29,2435.26 5315.29,2436.26 C122.1@5432.41,2436.26 5428.4,2432.26 IC30.2@5428.4,2312.88
  Top Layer w15: v2(5332.4,2310.38) 5334.91,2312.88 IC30.2@5428.4,2312.88
  Top Layer w20: C150.1@3186.41,1549.38 C150.1@3188.41,1549.38
  Top Layer w30: v2(3158.41,1416.38) 3270.29,1416.38 C137.1@3270.29,1434.38 ; v2(5288.77,1398.01) 5337.41,1446.64 R95.2@5337.41,1456.38
  Top Layer w60: C69.1@2630.41,7627.5 2630.41,7724.38 v2(2632.41,7726.38)
  L3 w30: IC5.2@2132.41,6151.38 2194.83,6151.38 2212.41,6133.8 2212.41,5843.95 2229.98,5826.38 2800.83,5826.38 2818.41,5808.8 J33.2@2818.41,5622.38
  L5 w6: v2@5310.41,2311.38 v2@5316.9,2311.38
  Bottom Layer w6: J33.2@2818.41,5622.38 2818.41,5698.38 3100.41,5980.38 3100.41,6146.38 3253.41,6299.38 3571.41,6299.38 3646.41,6374.38 4558.41,6374.38 4718.41,6214.38 4718.41,5837.38 4932.4,5623.38 4932.4,5269.38 v1(4940.4,5261.38)
  Bottom Layer w30: C56.1@2013.41,6150.26 IC5.2@2131.29,6150.26
  Bottom Layer w60: L5.2@2509.26,7736.37 2514.33,7736.37 2524.32,7726.38 v2(2792.41,7726.38)
  other v2: 1160.41,6453.38
485_DE: IC6.R15 IC20.6 pad.1@2134.41,3118.38 | length 2595.7
  Top Layer w6: IC20.6@1122.41,3211.38 1209.41,3211.38 1240.41,3180.38 1764.41,3180.38 1826.41,3118.38 pad.1@2134.41,3118.38 2442.41,3118.38 2650.41,3326.38 2851.41,3326.38 3050.41,3525.38 3166.41,3525.38 3189.41,3548.38 3189.41,3620.88 3246.41,3677.88 3246.41,3706.38 3293.41,3753.38 3329.41,3753.38 IC6.R15@3349.21,3773.17
485_RE#: IC6.P15 IC20.5 pad.1@2134.41,3001.38 | length 2846
  Top Layer w6: IC20.5@1101.41,3163.38 1729.41,3163.38 1807.41,3085.38 2158.41,3085.38 2175.41,3068.38 2175.41,3018.38 2158.41,3001.38 pad.1@2134.41,3001.38 ; v1(3370.41,3751.38) 3388.61,3769.58 IC6.P15@3388.61,3773.17
  Bottom Layer w6: pad.1@2134.41,3001.38 2182.41,3001.38 2453.41,3272.38 2453.41,3314.38 2608.41,3469.38 2653.41,3469.38 2698.41,3514.38 3125.41,3514.38 3176.41,3565.38 3176.41,3623.38 3232.41,3679.38 3291.41,3679.38 3363.41,3751.38 v1(3370.41,3751.38)
485_RXD: IC6.N14 IC20.4 pad.1@2134.41,3061.38 | length 2883
  Top Layer w6: IC20.4@1101.41,3113.38 1183.41,3113.38 1200.41,3130.38 1716.41,3130.38 1821.41,3025.38 2098.41,3025.38 pad.1@2134.41,3061.38 ; IC6.N14@3427.91,3812.58 3428.61,3812.58 v1(3447.41,3831.38)
  L3 w6: pad.1@2134.41,3061.38 2811.41,3061.38 3177.41,3427.38 3228.41,3427.38 3326.41,3525.38 3326.41,3739.38 3418.41,3831.38 v1(3447.41,3831.38)
485_TX: IC6.T15 IC20.7 pad.1@2134.41,3178.38 | length 2649.8
  Top Layer w6: IC20.7@1101.41,3263.38 1196.41,3263.38 1250.41,3209.38 1788.41,3209.38 1827.41,3170.38 2126.41,3170.38 pad.1@2134.41,3178.38 2145.41,3167.38 2429.41,3167.38 2608.41,3346.38 2688.41,3346.38 2715.41,3373.38 2715.41,3578.38 2735.41,3598.38 3009.41,3598.38 3038.41,3627.38 3053.41,3627.38 ; 3046.41,3627.38 3053.41,3627.38 ; IC6.T15@3309.8,3773.17 3292.2,3773.17 3232.41,3713.38 3232.41,3684.38 3175.41,3627.38 3053.41,3627.38
+1V2: C16.2 C17.1 C19.2 C23.1 C24.1 C26.1 C27.1 C28.2 C30.1 C31.1 C33.1 C36.2 C37.2 C38.2 C40.1 C41.1 C45.2 C46.2 C47.2 IC4.5 IC6.G7 IC6.G9 IC6.H8 IC6.H10 IC6.J7 IC6.J9 IC6.K8 IC6.K10 TP4.1 | length 1215
  Top Layer w6: IC6.G9@3664.2,4008.17 IC6.G9@3664.2,4009.38
  Top Layer w10: C38.2@3135.95,3696.37 v1@3171.41,3696.37 ; C37.2@3139.95,3799.38 3159.41,3799.38 v1(3176.41,3816.37) ; v1@3172.41,3698.38 3176.41,3702.38 v1(3177.41,3702.38) ; C33.1@3507.41,4447.84 3507.41,4430.38 v1(3523.41,4414.38) ; v1(3527.41,3989.38) 3527.41,3988.98 3546.01,3970.38 IC6.K10@3546.01,3969.98 ; IC6.K8@3546.01,4048.78 3546.41,4048.78 3565.01,4067.38 v1(3565.41,4067.38) ; v1(3564.41,4029.38) 3564.91,4029.38 3584.91,4009.38 IC6.J9@3585.41,4009.38 ; IC6.J7@3585.41,4088.17 3585.8,4088.17 3604.01,4106.38 v1(3604.41,4106.38) ; v1(3605.1,4029.08) IC6.H8@3624.8,4048.78 ; v1(3605.41,3989.38) IC6.H10@3624.8,3969.98 ; v1(3644.41,4106.38) 3645.2,4106.38 3663.41,4088.17 IC6.G7@3664.2,4088.17 ; v1(3645.41,3989.38) 3645.41,3989.98 3663.6,4008.17 IC6.G9@3664.2,4008.17
  Top Layer w15: C47.2@2965.41,3956.38 3017.41,3956.38 v1(3018.41,3955.38) ; C45.2@2969.41,4467.38 2999.41,4467.38 v1(3014.41,4482.38) ; C46.2@2983.5,4272.37 3021.41,4272.37 v1(3026.41,4267.38) ; C36.2@3187.95,4119.38 v1(3216.41,4119.38) ; C40.1@3221.41,3450.67 3221.41,3503.38 v1(3226.41,3508.38) ; v1(3646.41,3554.38) 3663.41,3537.38 C31.1@3663.41,3490.92 ; C30.1@3855.41,4466.83 3876.86,4466.83 3887.41,4477.38 v1(3887.41,4497.38) ; v1(3986.41,4531.38) 3990.41,4527.38 C23.1@4041.86,4527.38 ; v1(3999.41,4208.37) 4000.41,4207.38 C24.1@4051.87,4207.38 ; v1(4106.41,3769.38) 4118.41,3757.38 C26.1@4146.86,3757.38 ; v1(4121.41,3623.38) 4127.41,3617.38 C27.1@4150.86,3617.38 ; v1(4281.41,4306.38) 4288.41,4299.38 C17.1@4340.4,4299.38 ; C16.2@4357.49,4456.37 4424.41,4456.37 v1(4425.41,4455.38)
  Top Layer w20: C41.1@3050.41,3388.92 3050.41,3431.38 v1(3057.41,3438.38) ; v1(4000.41,3435.38) 4006.41,3429.38 C28.2@4006.41,3390.46 ; v1(4222.41,3423.38) 4223.41,3422.38 C19.2@4223.41,3380.46 ; IC4.5@4362.41,4591.89 4362.41,4554.38 v1(4366.41,4550.38)
+5VA: C72.2 C82.1 C85.2 C95.1 C133.2 C139.1 D3.1 D10.2 D11.2 D12.2 D13.2 D20.2 D21.2 IC22.10 IC22.12 IC22.20 IC23.8 IC24.8 IC33.3 J11.16 J35.1 J44.3 L9.2 R112.2 R113.2 TP8.1 | length 2717.3
  Top Layer w10: D13.2@504.81,428.6 530.63,428.6 v1(552.41,450.38) ; D11.2@589.41,563.38 589.41,619.38 v1(590.41,620.38) ; v1(621.41,1909.38) 630.17,1900.62 D21.2@684.3,1900.62 ; D20.2@760.81,1627.7 760.81,1574.97 v1(762.41,1573.38) ; R113.2@932.95,1831.72 994.06,1831.72 v1(995.41,1830.38) ; v1(966.41,898.38) 970.95,902.92 C85.2@970.95,938.38 ; v1(1004.41,889.38) 1006.1,887.69 IC24.8@1006.1,849.38 ; IC23.8@1006.1,1344.18 1006.1,1375.07 v1(1007.41,1376.38) ; v1(1015.41,1509.38) 1023.86,1500.92 C82.1@1023.86,1463.38 ; v1(1086.41,1775.38) 1094.41,1783.38 C95.1@1094.41,1828.83 ; v1(1135.41,1754.38) 1153.05,1736.74 IC22.20@1178.91,1736.74 ; v1(1179.41,675.18) 1183.86,670.72 C133.2@1226.41,670.72 ; C72.2@1253.41,1064.92 1291.86,1064.92 v1(1296.41,1060.38) ; v1(1310.41,1108.38) 1312.41,1106.38 IC33.3@1374.06,1106.38 ; v1(1328.41,1932.38) 1337.86,1922.92 R112.2@1372.41,1922.92 ; v1(1372.41,1803.38) 1378.91,1796.87 IC22.12@1378.91,1736.74 ; IC22.10@1403.91,1532.01 1403.91,1479.87 v1(1423.41,1460.38)
  Top Layer w20: D12.2@455.81,1169.7 479.73,1169.7 v1(483.41,1173.38) ; v1(555.41,1148.38) 556,1147.78 D10.2@556,1104.06
  Top Layer w30: v1(875.41,312.38) 887.41,300.38 D3.1@951.41,300.38
  L4 w50: J35.1@1440.41,276.38 J35.1@1447.41,283.38 J35.1@1457.84,272.94 ; TP8.1@1755.41,1932.38 TP8.1@1760.41,1937.38 ; 1819.54,428.98 3044.41,428.98 3297.94,682.51 3297.94,687.33 3306.41,695.8 J11.16@3306.41,700.38
+5VSW: C61.1 C120.2 C123.2 D2.1 IC30.5 IC30.6 J2.3 J11.1 J11.2 J11.15 J20.2 P1.1 P1.3 R64.1 R93.2 R117.2 TP13.1 | length 9778.3
  Top Layer w15: R93.2@4984.41,1716.83 4984.41,1601.92 R117.2@4985.41,1600.92 5010.95,1600.92 5043.75,1633.72 IC30.6@5078.41,1633.72 IC30.6@5067.41,1622.72
  L3 w60: J11.15@3406.41,700.38 3407.73,701.7 3407.73,729.1 3625.01,946.38 4671.26,946.38 4706.41,911.23 J11.2@4706.41,700.38 J11.1@4806.41,700.38 ; J11.1@4828.4,706.38 4848.41,706.38 5038.41,896.38 J2.3@5367.41,896.38
  L4 w15: J20.2@2823.41,6305.38 2823.41,6388.38 2858.44,6423.41
  L4 w20: 2858.44,6423.41 4851.22,6423.41 5058.67,6215.97 5058.67,5653.16 5120.03,5591.8 5120.03,4819.53 5230.27,4709.29 5230.27,4021.11 5253.48,3997.89 5357.83,3997.89 P1.3@5404.33,3951.4 5392.41,3951.4 P1.1@5392.41,3851.38
  Bottom Layer w60: J2.3@5367.41,896.38 5418.41,896.38 5448.41,926.38 5448.41,1524.38 5224.41,1748.38 5224.41,2708.38 5340.4,2824.38 TP13.1@5387.41,2824.38
+5VSW_EN: IC6.P2 J20.3 pad.1@2373.41,5416.37 R74.2 R116.2 R117.1 TR9.1 | length 11075.2
  Top Layer w6: R74.2@2224.41,5219.57 2251.6,5219.57 2373.41,5341.38 pad.1@2373.41,5416.37 ; v1(4352.41,2276.38) 4352.41,1524.38 4610.41,1266.38 4940.4,1266.38 4985.41,1311.38 4985.41,1348.38 ; R117.1@4985.41,1543.83 4985.41,1348.38 ; TR9.1@5329.17,1350.08 5305.1,1350.08 5294.41,1339.38 R116.2@5264.41,1339.38 5240.41,1339.38 5211.41,1310.38 4987.41,1310.38 4985.41,1312.38 4985.41,1348.38
  Top Layer w10: v1(3368.41,4265.38) 3388.01,4284.98 IC6.P2@3388.61,4284.98
  L3 w6: v1(2044.41,4621.38) 2060.41,4605.38 2060.41,2806.38 2125.41,2741.38 v1(2747.41,2741.38)
  Bottom Layer w6: v1(2044.41,4621.38) 2044.41,5376.18 2127.5,5459.28 2416.31,5459.28 ; J20.3@2723.41,6305.38 2723.41,6214.38 2615.41,6106.38 2615.41,5977.38 2499.41,5861.38 2499.41,5542.38 2442.91,5485.88 2439.41,5482.38 2416.31,5459.28 ; v1(2747.41,2741.38) 2736.41,2730.38 2736.41,2420.38 2816.41,2340.38 2975.41,2340.38 3060.41,2425.38 3754.41,2425.38 3903.41,2276.38 v1(4352.41,2276.38) ; v1(3368.41,4265.38) 3385.91,4282.88 3385.91,4334.88 3411.41,4360.37 3411.41,4469.38 3385.41,4495.38 3304.41,4495.38 3146.41,4653.38 2832.41,4653.38 2373.41,5112.37 pad.1@2373.41,5416.37 2416.31,5459.28
-5VA: C84.2 C89.1 C92.1 C143.1 D4.2 D10.1 D11.1 D12.1 D13.1 D20.1 D21.1 IC23.4 IC24.4 IC33.9 J11.18 J35.3 L10.2 TP10.1 | length 2203.4
  Top Layer w10: v1(396.41,431.38) 399.18,428.6 D13.1@430,428.6 ; v1(639.41,1621.38) 645.73,1627.7 D20.1@686,1627.7 ; v1(653.41,613.38) 659.11,607.67 D11.1@659.11,552.61 ; v1(732.41,1149.38) 750.86,1130.92 C89.1@750.86,1088.38 ; v1(733.41,1203.38) 744.41,1192.38 IC23.4@812.41,1192.38 ; v1(750.41,1967.38) 759.11,1958.67 D21.1@759.11,1900.61 ; C92.1@796.86,586.38 v1(796.86,628.38) ; IC24.4@797.12,699.37 797.12,668.67 v1(797.41,668.38) ; C84.2@1500.41,727.92 1500.41,794.38 v1(1509.41,803.38) ; v1(1526.41,856.38) IC33.9@1590.75,856.38
  Top Layer w20: v1(328.41,1156.38) 341.73,1169.7 D12.1@381,1169.7 ; D10.1@630.81,1104.05 630.81,1145.78 v1(632.41,1147.38)
  Top Layer w30: v1(568.41,320.38) 582.41,306.38 D4.2@619.46,306.38
  L4 w50: TP10.1@1706.63,453.38 TP10.1@1714.41,453.38
  L5 w50: 1767.41,647.88 1767.41,630.53 1802.55,595.38 2621.21,595.38 2769.61,743.78 3062.25,743.78 3105.65,700.38 J11.18@3106.41,700.38
ADC_BUSY: IC22.16 pad.1@1075.41,2038.38 | length 420.2
  Top Layer w5: pad.1@1075.41,2038.38 1085.41,2038.38 1124.41,1999.38 1124.41,1917.38 1156.41,1885.38 1204.91,1885.38 1233.41,1856.88 1233.41,1828.38 1278.91,1782.87 IC22.16@1278.91,1736.74
ADC_CS#: IC6.T13 IC22.18 pad.1@2137.41,3473.38 | length 3800.5
  Top Layer w5: v1(1170.41,1865.38) 1170.41,1833.38 1228.91,1774.87 IC22.18@1228.91,1736.74
  Top Layer w6: v1(3255.41,3801.38) 3259.3,3801.38 IC6.T13@3309.8,3851.87
  Bottom Layer w6: v1(1170.41,1865.38) 1170.41,1987.38 1220.41,2037.38 1416.41,2037.38 1460.41,2081.38 1460.41,2189.38 1531.41,2260.38 1531.41,2336.38 1596.41,2401.38 1808.41,2401.38 1915.6,2508.57 1915.6,3372.57 1950.41,3407.38 1989.41,3407.38 2055.41,3473.38 2343.41,3473.38 2555.41,3685.38 3076.41,3685.38 3130.41,3739.38 3190.41,3739.38 3252.41,3801.38 v1(3255.41,3801.38)
CH4: IC6.N4 IC22.5 pad.1@2139.41,5298.38 R88.2 R89.1 | length 9323.5
  Top Layer w5: v1(1034.41,1930.38) 1034.41,1757.38 1144.41,1647.38 1230.41,1647.38 1278.91,1598.87 IC22.5@1278.91,1532.01
  Top Layer w6: IC6.N4@3427.91,4206.28 3430.31,4206.28 v1(3448.41,4224.37)
  Top Layer w10: R88.2@728.41,6499.84 728.41,6414.92 R89.1@737.41,6405.92 700.95,6405.92 696.41,6401.38 696.41,5688.37 747.41,5637.38 1777.41,5637.38 2116.41,5298.38 pad.1@2139.41,5298.38
  L3 w6: pad.1@2139.41,5298.38 2144.41,5293.38 v1(2428.41,5293.38)
  Bottom Layer w5: v1(1034.41,1930.38) 1034.41,1976.38 1021.41,1989.38 1021.41,2116.38 1056.51,2151.48 1056.51,2410.48 1115.31,2469.28 1299.01,2469.28 1322.11,2492.38 1806.41,2492.38 1854.71,2540.68 1854.71,3862.68 2071.41,4079.38 2071.41,5230.38 pad.1@2139.41,5298.38
  Bottom Layer w6: v1(2428.41,5293.38) 2428.41,5081.38 2843.41,4666.38 3163.41,4666.38 3228.41,4601.38 3381.41,4601.38 3427.41,4555.38 3427.41,4246.38 3448.41,4225.38 v1(3448.41,4224.37)
CLKOUT: IC32.7 | length 98.8
  Top Layer w10: IC32.7@4490.41,2294.36 4490.41,2390.38 v3(4492.4,2392.38)
COMP_INB-: D20.3 IC22.3 IC33.6 R107.2 R109.2 | length 1567.1
  Top Layer w5: R109.2@584.95,1713.38 587.95,1710.38 D20.3@723.41,1710.38 953.41,1710.38 1079.41,1584.38 1203.41,1584.38 1228.91,1558.87 IC22.3@1228.91,1532.01 1228.91,1373.87 1242.95,1359.83 R107.2@1242.95,1326.38 1242.95,1290.83 1269.41,1264.38 1426.25,1264.38 1458.41,1232.23 1458.41,981.38 1433.41,956.38 IC33.6@1374.06,956.38
COMP_IND-: D21.3 IC22.4 IC33.12 R108.1 R111.2 | length 1575.2
  Top Layer w5: R111.2@574.95,1809.38 612.41,1809.38 620.96,1817.94 D21.3@721.71,1817.94 767.85,1817.94 810.41,1775.38 932.91,1775.38 1096.91,1611.38 1219.41,1611.38 1253.91,1576.87 IC22.4@1253.91,1532.01 1253.91,1486.87 1341.86,1398.92 R108.1@1341.86,1323.38 1341.86,1291.92 1356.41,1277.38 1442.41,1277.38 1475.41,1244.38 1475.41,1066.38 1535.41,1006.38 IC33.12@1590.75,1006.38
COMP_OUTA: IC6.H15 IC33.2 pad.1@3314.41,2822.38 R46.2 R55.2 TP17.1 | length 4481.3
  Top Layer w5: R55.2@1252.95,1159.38 1255.95,1156.38 1301.41,1156.38 ; v1(1302.41,1186.38) 1302.41,1157.38 1301.41,1156.38 ; IC33.2@1374.06,1156.38 1301.41,1156.38 ; v1(2596.41,2212.38) 2806.41,2212.38 2845.95,2251.92 R46.2@2845.95,2302.38
  Top Layer w6: R46.2@2845.95,2302.38 2845.95,2408.92 TP17.1@2847.41,2410.38 ; IC6.H15@3624.8,3773.17 3644.41,3753.58 v1(3644.41,3641.38)
  Bottom Layer w5: v1(1302.41,1186.38) 1302.41,1191.38 1346.41,1235.38 1346.41,1602.38 1427.41,1683.38 1427.41,1868.38 1710.41,2151.38 1780.41,2151.38 1835.41,2206.38 1865.41,2206.38 1936.41,2277.38 2376.41,2277.38 2441.41,2212.38 v1(2596.41,2212.38)
  Bottom Layer w6: TP17.1@2847.41,2410.38 2959.41,2522.38 2988.41,2522.38 3063.41,2597.38 3183.41,2597.38 3314.41,2728.38 pad.1@3314.41,2822.38 3319.38,2827.35 3319.38,2837.28 3445.2,2963.1 3474.5,2963.1 3617.41,3106.01 3617.41,3610.38 3620.41,3613.38 v1(3644.41,3641.38)
COMP_OUTB: IC6.M15 IC33.1 pad.1@2547.41,2825.38 R101.2 R103.1 TP24.1 | length 5175.1
  Top Layer w5: v1(1112.41,1257.38) 1127.41,1242.38 1127.41,1207.38 1127.41,798.38 1146.95,778.83 R103.1@1199.41,778.83 ; 1128.41,1206.38 1153.41,1206.38 ; 1149.41,1206.38 1153.41,1206.38 ; IC33.1@1374.06,1206.38 1153.41,1206.38
  Top Layer w6: pad.1@2547.41,2825.38 2564.41,2825.38 2638.41,2899.38 2708.41,2899.38 3107.41,3298.38 3107.41,3357.38 3171.41,3421.38 3275.41,3421.38 3351.41,3497.38 3351.41,3616.38 3450.41,3715.38 3450.41,3755.82 3467.3,3772.72 IC6.M15@3467.3,3773.17
  Top Layer w10: R101.2@2537.95,2275.38 2611.41,2275.38 TP24.1@2619.41,2283.38
  Bottom Layer w5: v1(1112.41,1257.38) 1112.41,1400.38 1250.41,1538.38 1250.41,1722.38 1296.41,1768.38 1296.41,1810.38 1455.41,1969.38 1455.41,1990.38 1568.41,2103.38 1568.41,2172.38 1665.41,2269.38 1805.41,2269.38 1967.41,2431.38 2202.41,2431.38 2280.41,2353.38 2332.41,2353.38 2383.41,2404.38 ; pad.1@2547.41,2825.38 2547.41,2783.01 2383.41,2619.01 2383.41,2450.38 2383.41,2404.38 ; TP24.1@2619.41,2283.38 2612.41,2290.38 2516.41,2290.38 2402.41,2404.38 2383.41,2404.38
COMP_OUTC: IC6.J14 IC33.16 J20.5 pad.1@3020.41,2822.38 R45.2 R48.2 TP16.1 | length 8915.5
  Top Layer w6: v1(2404.41,2333.38) 2405.41,2333.38 2420.41,2348.38 2633.41,2348.38 2727.41,2442.38 2727.41,2470.38 2845.41,2588.38 v1(2859.41,2588.38) ; TP16.1@2925.41,2616.38 2928.95,2612.83 R45.2@2928.95,2501.38 ; v1(3568.41,3792.37) 3585.41,3809.38 IC6.J14@3585.41,3812.58
  Top Layer w10: R48.2@1561.95,1506.38 1598.41,1506.38 1599.41,1507.38 ; IC33.16@1590.75,1206.38 1590.75,1230.72 1599.41,1239.38 1599.41,1507.38 ; v1(1599.41,2120.38) 1599.41,1507.38
  L3 w6: v1(2003.41,4621.38) 2041.41,4583.38 2041.41,2794.38 2106.01,2729.78 2718.01,2729.78 v1(2859.41,2588.38) 2897.41,2588.38 TP16.1@2925.41,2616.38 3020.41,2711.38 pad.1@3020.41,2822.38
  Bottom Layer w6: v1(1599.41,2120.38) 1599.41,2166.38 1680.41,2247.38 1829.91,2247.38 1992.91,2410.38 2176.41,2410.38 2253.41,2333.38 v1(2404.41,2333.38) ; v1(2003.41,4621.38) 2003.41,5393.38 2094.41,5484.38 2168.01,5484.38 2211.41,5527.78 2211.41,5734.38 2473.41,5996.38 2473.41,6178.38 2523.41,6228.38 J20.5@2523.41,6305.38 ; pad.1@3020.41,2822.38 3020.41,3089.38 3425.41,3494.38 3505.41,3494.38 3555.41,3544.38 3555.41,3752.37 3568.41,3765.38 v1(3568.41,3792.37)
COMP_OUTD: IC6.L14 IC33.15 pad.1@2607.41,2822.38 R104.1 R106.2 TP25.1 | length 4821.9
  Top Layer w6: v1(3488.41,3793.38) 3506.71,3811.68 IC6.L14@3506.71,3812.58
  Top Layer w10: R106.2@1564.95,1313.38 1564.95,1273.92 1563.41,1272.38 1527.41,1236.38 1527.41,1171.38 1542.41,1156.38 IC33.15@1590.75,1156.38 1634.41,1156.38 1645.41,1167.38 1645.41,1255.38 1628.41,1272.38 1628.41,2026.38 1645.41,2043.38 1645.41,2104.38 v1(1632.41,2117.38) ; TP25.1@2450.41,2450.38 2450.41,2512.38 2478.41,2540.38 R104.1@2485.86,2540.38
  L3 w6: pad.1@2607.41,2822.38 2607.41,2846.38 2735.41,2974.38 2912.41,2974.38 3399.41,3461.38 3399.41,3705.28 3487.51,3793.38 v1(3488.41,3793.38)
  Bottom Layer w6: v1(1632.41,2117.38) 1632.41,2161.38 1694.41,2223.38 1844.41,2223.38 1920.41,2299.38 2390.41,2299.38 2457.41,2232.38 2676.41,2232.38 2686.41,2242.38 2686.41,2313.38 2664.41,2335.38 2561.41,2335.38 2450.41,2446.38 2450.41,2582.88 2607.41,2739.88 pad.1@2607.41,2822.38
EEPROM1_CS#: IC2.1 IC6.M11 | length 3672
  Top Layer w6: v1(2767.41,4202.38) 2906.41,4202.38 2923.41,4219.38 2923.41,4326.38 v1(2899.41,4350.38) ; v1(3312.41,5114.38) 3423.41,5114.38 3564.41,5255.38 v1(3928.41,5255.38) ; IC6.M11@3467.3,3930.68 3467.71,3930.68 v1(3487.41,3950.38) ; v1(4152.41,5023.38) 4153.69,5022.09 IC2.1@4352.61,5022.09
  L3 w6: v1(2911.41,4013.38) 2911.41,4016.37 2936.41,4041.38 3217.41,4041.38 3260.41,3998.38 3260.41,3949.38 3276.41,3933.38 3290.41,3933.38 3327.11,3970.08 3420.1,3970.08 3428.11,3978.08 3428.11,4000.08 3436.41,4008.37 3457.41,4008.37 3465.41,4000.37 3465.41,3966.38 3481.41,3950.38 v1(3487.41,3950.38) ; v1(3100.41,4600.37) 3312.41,4812.38 v1(3312.41,5114.38) ; v1(3928.41,5255.38) 3928.41,5056.37 3994.41,4990.38 4119.41,4990.38 v1(4152.41,5023.38)
  Bottom Layer w6: v1(2767.41,4202.38) 2767.41,4134.38 2888.41,4013.38 v1(2911.41,4013.38) ; v1(2899.41,4350.38) 2899.41,4386.38 2961.41,4448.37 3051.41,4448.37 3062.41,4459.38 3062.41,4513.38 3100.41,4551.38 v1(3100.41,4600.37)
EEPROM1_SCK: IC2.6 IC6.R7 | length 3105.8
  Top Layer w6: v1(3328.41,4108.38) 3348.61,4088.17 IC6.R7@3349.21,4088.17 ; v1(3355.41,5058.38) 3356.41,5059.38 3417.41,5059.38 3591.41,5233.38 3875.41,5233.38 3886.41,5222.38 3944.41,5222.38 4080.41,5358.38 v1(4303.41,5358.38) ; v1(4438.41,5343.38) 4438.41,5292.38 4456.41,5274.38 IC2.6@4456.41,5240.37
  L3 w6: v1(2947.41,4350.38) 2948.41,4350.38 2998.41,4400.37 3177.41,4400.37 3197.41,4380.38 3260.41,4380.38 3309.8,4330.98 3309.8,4270.98 3335.21,4245.58 3375.21,4245.58 3387.41,4233.38 3387.41,4217.38 3400.41,4204.38 3416.86,4204.38 3427.91,4193.33 3427.91,4175.87 3379.41,4127.38 3349.21,4127.38 3330.21,4108.38 v1(3328.41,4108.38) ; v1(3147.41,4479.38) 3147.41,4578.38 3356.41,4787.38 v1@3356.41,5059.38
  L4 w6: v1(4303.41,5358.38) 4314.41,5369.38 4350.41,5369.38 4376.41,5343.38 v1(4438.41,5343.38)
  Bottom Layer w6: v1(2947.41,4350.38) 2947.41,4401.38 2974.41,4428.38 3110.41,4428.38 3147.41,4465.38 v1(3147.41,4479.38)
EEPROM1_SI: IC2.5 IC6.P4 | length 2255.4
  Top Layer w6: v1(3368.41,4225.38) 3387.51,4206.28 IC6.P4@3388.61,4206.28 ; v1(3391.41,4979.38) 3614.41,5202.38 3954.41,5202.38 4080.41,5328.37 4326.41,5328.37 4340.4,5342.38 v1(4340.4,5343.38) ; v1(4474.41,5313.38) 4474.41,5303.38 4503.41,5274.38 IC2.5@4503.41,5250.38
  L3 w6: v1(3271.41,4487.38) 3248.41,4510.38 3248.41,4630.38 3391.41,4773.38 v1(3391.41,4979.38)
  L4 w6: v1(4340.4,5343.38) 4370.41,5313.38 v1(4474.41,5313.38)
  Bottom Layer w6: v1(3271.41,4487.38) 3262.41,4478.38 3262.41,4411.38 3281.41,4392.37 3318.41,4392.37 3360.91,4349.87 3360.91,4296.28 3344.71,4280.08 3344.71,4249.08 v1(3368.41,4225.38)
EEPROM1_SO: IC2.2 IC6.K12 | length 2617.8
  Top Layer w6: IC6.K12@3546.01,3891.28 3566.1,3911.38 3603.41,3911.38 v1(3604.41,3910.38) ; IC2.2@4402.61,5022.09 4402.61,4976.17 4445.41,4933.38 4481.41,4933.38 4510.41,4904.37 4510.41,4694.38 4574.41,4630.38 4574.41,4279.38 v1(4580.4,4273.38)
  L3 w6: v1(4580.4,4273.38) 4580.4,4312.37 4613.41,4345.38 4682.41,4345.38 4709.41,4318.38 4765.41,4318.38 4778.41,4305.38 4778.41,4218.38 4761.41,4201.38 4641.41,4201.38 4583.41,4143.38 v1(4583.41,4142.38)
  Bottom Layer w6: v1(3604.41,3910.38) 3604.41,3916.38 3665.41,3977.38 3665.41,4004.38 3671.7,4010.68 3783.71,4010.68 3814.41,4041.38 3998.41,4041.38 4036.4,4003.38 4257.41,4003.38 4365.41,4111.38 4538.41,4111.38 4569.41,4142.38 v1(4583.41,4142.38)
EEPROM_CLK: IC1.22 IC6.C4 IC10.6 IC15.1 pad.1@4734.41,4762.38 R10.1 | length 6062.3
  Top Layer w6: IC10.6@2798.41,4975.38 2798.41,5016.37 2829.41,5047.38 IC15.1@2829.41,5070.88 ; R10.1@3718.41,6079.84 3718.41,6040.37 v3(3736.41,6022.38) ; v1(3803.41,4225.38) 3821.6,4207.18 IC6.C4@3821.6,4206.28 ; pad.1@4734.41,4762.38 4923.41,4951.38 4923.41,5126.38 4868.4,5181.38 4802.41,5181.38 4783.41,5200.37 v1(4783.41,5269.38)
  Top Layer w10: IC1.22@4064.41,6100.38 4064.41,6172.38 v3(4080.4,6188.38)
  L3 w6: v1(3803.41,4225.38) 3803.41,4252.38 3837.41,4286.38 3837.41,4329.38 4013.41,4505.38 4013.41,4563.38 4044.4,4594.38 4503.41,4594.38 4671.41,4762.38 pad.1@4734.41,4762.38
  Bottom Layer w6: IC10.6@2797.41,4976.37 2797.41,5113.38 2849.41,5165.38 2849.41,5352.37 2818.41,5383.38 2818.41,5441.38 2893.41,5516.38 3264.41,5516.38 3589.41,5841.38 3677.41,5841.38 3831.41,5995.38 3831.41,6053.38 ; v3(3736.41,6022.38) 3743.41,6029.38 3763.41,6029.38 3787.41,6053.38 3831.41,6053.38 ; v1(4783.41,5269.38) 4783.41,5540.38 4734.41,5589.38 4629.41,5589.38 4591.41,5627.38 4591.41,6215.38 4548.4,6258.38 4259.41,6258.38 4230.41,6229.38 4121.4,6229.38 v3(4080.4,6188.38) 3988.4,6096.37 3888.41,6096.37 3845.41,6053.38 3831.41,6053.38
EEPROM_SDA: IC1.23 IC6.A3 IC10.5 IC15.3 pad.1@4734.41,4703.38 R11.1 | length 6134.4
  Top Layer w6: IC10.5@2698.41,4975.38 2751.41,4922.38 2832.41,4922.38 2847.41,4937.38 2847.41,5009.38 2863.41,5025.38 2894.41,5025.38 2904.41,5035.38 2904.41,5061.83 2904.21,5062.03 IC15.3@2904.21,5070.88 ; R11.1@3806.41,6078.83 v1(3806.41,6007.38) 3824.41,5989.38 4001.41,5989.38 4039.41,6027.38 IC1.23@4039.41,6100.38 4039.41,6212.89 ccw(c4018.92,6212.89) v1(4033.41,6227.38) ; IC6.A3@3900.4,4245.58 3951.6,4245.58 3963.41,4257.38 4156.4,4257.38 4212.4,4313.38 4212.4,4336.37 4279.41,4403.38 4430.41,4403.38 4472.41,4445.38 4472.41,4465.98 cw(c4475.81,4465.98) v1(4473.41,4468.38) ; pad.1@4734.41,4703.38 4944.41,4913.38 4944.41,5140.38 4879.41,5205.38 4850.41,5205.38 4822.41,5233.38 v1(4822.41,5259.38)
  Bottom Layer w6: IC10.5@2698.41,4975.38 2698.41,5072.37 2747.41,5121.38 2747.41,5314.38 2757.41,5324.38 2757.41,5459.38 2854.41,5556.38 3242.41,5556.38 3570.41,5884.38 3673.41,5884.38 3796.4,6007.38 v1(3806.41,6007.38) ; v1(4033.41,6227.38) 4064.41,6258.38 4064.41,6259.38 4216.41,6259.38 4242.41,6285.38 4571.41,6285.38 4627.41,6229.38 4627.41,5789.38 4822.41,5594.38 v1(4822.41,5259.38) ; v1(4473.41,4468.38) 4473.41,4494.38 4682.41,4703.38 pad.1@4734.41,4703.38
EN2: R96.2 TR9.3 | length 139.4
  Top Layer w20: TR9.3@5411.85,1312.68 5424.41,1325.24 R96.2@5424.41,1446.83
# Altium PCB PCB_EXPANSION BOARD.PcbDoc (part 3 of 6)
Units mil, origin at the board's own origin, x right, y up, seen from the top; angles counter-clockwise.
Board outline 5512.34 x 7953.29 mil, 6 copper layers (Top Layer, L2, L3, L4, L5, Bottom Layer); 420 components, 365 nets, 1860 pads, 895 vias.
Unrouted connection lines stored in the file: 9.

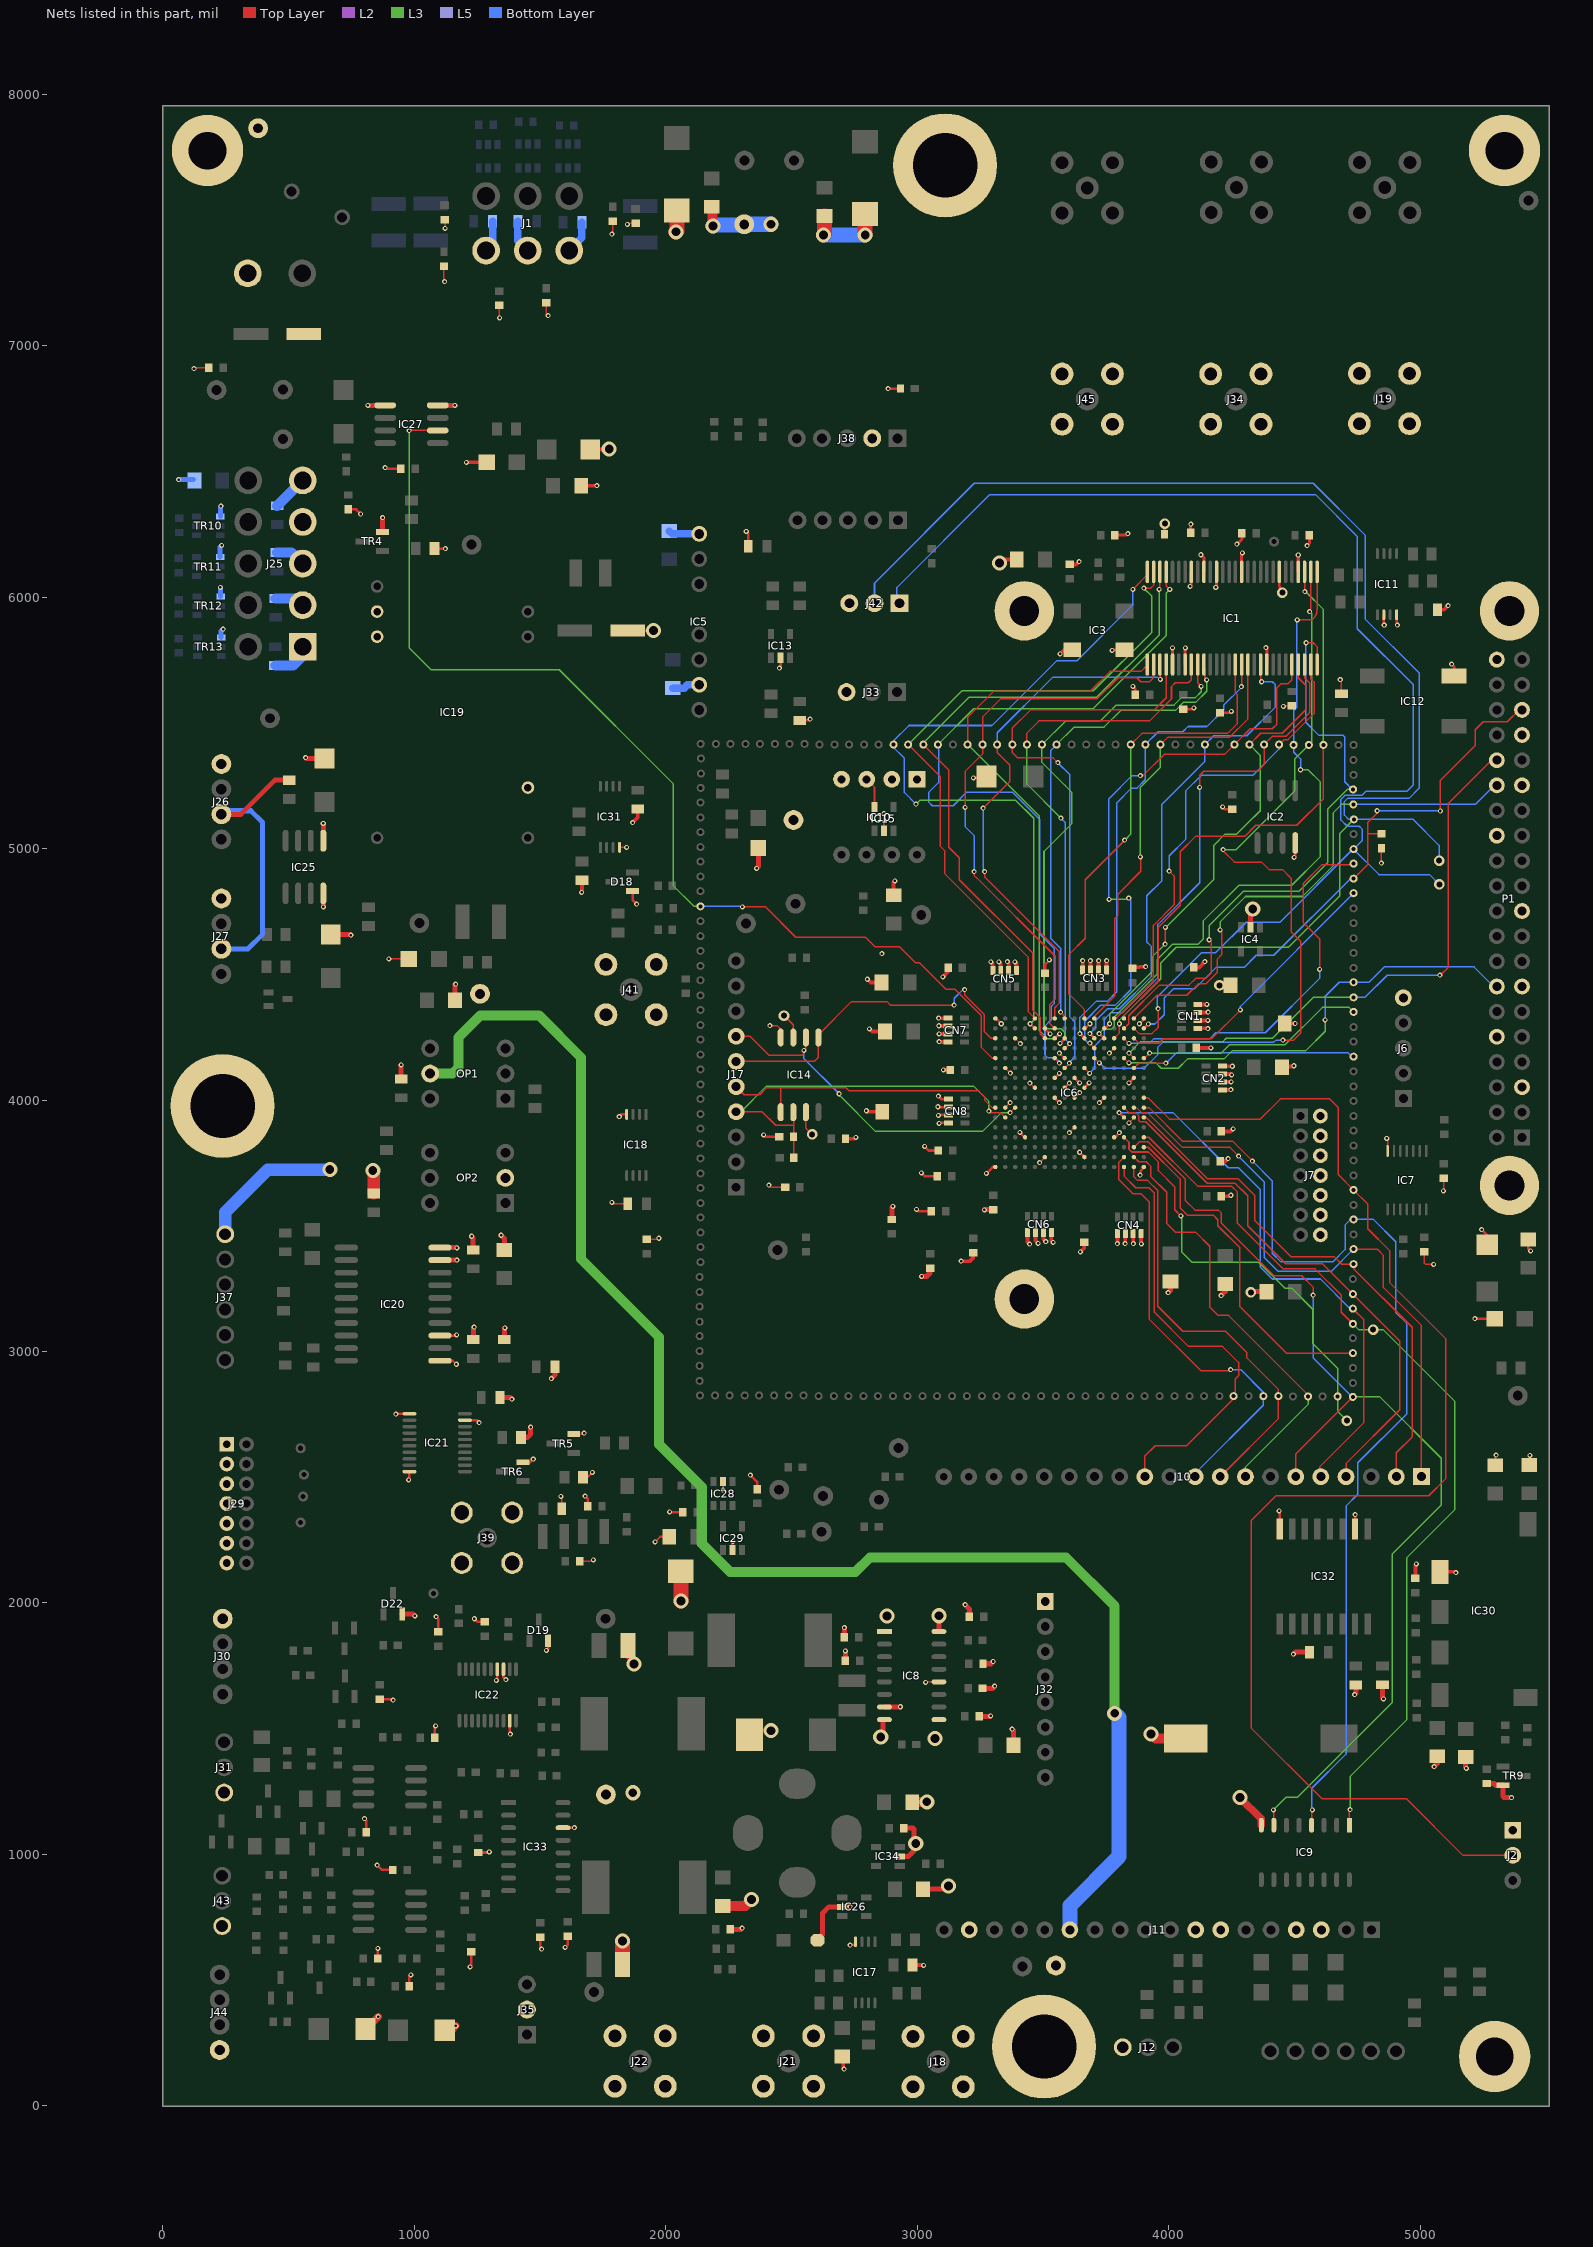
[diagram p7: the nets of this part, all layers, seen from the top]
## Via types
v1: diameter 20, hole 10, Top Layer to Bottom Layer, tented both sides, 808 vias
v2: diameter 60, hole 35, Top Layer to Bottom Layer, 47 vias
v3: diameter 42, hole 24, Top Layer to Bottom Layer, 32 vias
v4: diameter 125.98/125.98/125.98/125.98/125.98/125.98 (per signal layer), hole 125.98, Top Layer to Bottom Layer, 6 vias
v5: diameter 51.18, hole 51.18, Top Layer to Bottom Layer, 2 vias

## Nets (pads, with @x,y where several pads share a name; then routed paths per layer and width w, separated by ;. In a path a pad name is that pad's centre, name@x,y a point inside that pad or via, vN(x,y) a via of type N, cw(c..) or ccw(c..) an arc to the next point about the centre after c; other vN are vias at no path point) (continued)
EXP_TX: J26.3 J27.3 R65.1 | length 1147
  Top Layer w20: J26.3@232.41,5136.37 309.41,5136.37 444.81,5271.78 R65.1@502.01,5271.78
  Bottom Layer w20: J27.3@232.41,4601.38 338.41,4601.38 396.41,4659.38 396.41,5103.38 349.41,5150.38 246.41,5150.38 J26.3@232.41,5136.37
FANS_EN: IC6.T5 IC27.2 pad.1@2137.41,4770.38 | length 4311.5
  Top Layer w6: v1(978.41,6662.38) 978.61,6662.58 IC27.2@1092.69,6662.58 ; v1(2304.41,4768.37) 2395.41,4768.37 2516.41,4647.38 2793.41,4647.38 2830.41,4610.38 2927.41,4610.38 2991.41,4546.38 3007.41,4546.38 3112.41,4441.38 3148.41,4441.38 3254.41,4335.38 3254.41,4209.38 3296.91,4166.88 IC6.T5@3309.8,4166.88
  L3 w6: 990,6665.9 978.41,6665.9 978.41,5798.79 1066,5711.2 1575.58,5711.2 2028.41,5258.38 2028.41,4853.38 2111.41,4770.38 pad.1@2137.41,4770.38
  Bottom Layer w6: pad.1@2137.41,4770.38 2302.41,4770.38 v1(2304.41,4768.37)
FD0: IC1.25 IC6.K5 pad.1@3081.41,5413.38 | length 3190.7
  Top Layer w6: IC6.K5@3546.01,4166.88 3546.01,4164.78 v1(3564.41,4146.38) ; IC1.25@3989.41,6100.38 3989.41,6044.38 v1(4003.41,6030.38)
  L3 w6: pad.1@3081.41,5413.38 3224.41,5556.38 3698.41,5556.38 3989.41,5847.38 3989.41,6016.37 v1(4003.41,6030.38)
  Bottom Layer w6: pad.1@3081.41,5413.38 3084.41,5410.38 3084.41,5262.38 3044.41,5222.38 3044.41,5185.38 3059.41,5170.38 3142.41,5170.38 3196.41,5224.37 3377.41,5224.37 3486.41,5115.38 3486.41,4660.38 3543.41,4603.38 3543.41,4383.38 3532.41,4372.38 3532.41,4319.38 3507.41,4294.38 3507.41,4179.38 3519.41,4167.38 3549.41,4167.38 3564.41,4152.37 v1(3564.41,4146.38)
FD1: IC1.26 IC6.L3 pad.1@3023.41,5413.38 | length 2742.3
  Top Layer w6: pad.1@3023.41,5413.38 3124.41,5312.37 3124.41,5005.38 3166.41,4963.38 3166.41,4876.38 3458.41,4584.37 3458.41,4358.38 3488.41,4328.37 3488.41,4263.87 IC6.L3@3506.71,4245.58 ; v1(3961.41,6030.38) 3964.4,6033.38 IC1.26@3964.4,6100.38
  L3 w6: pad.1@3023.41,5413.38 3023.41,5419.38 3205.41,5601.38 3713.41,5601.38 3961.41,5849.38 v1(3961.41,6030.38)
FD2: IC1.27 IC6.M1 pad.1@2963.41,5413.38 | length 2726.5
  Top Layer w6: pad.1@2963.41,5413.38 3091.41,5285.38 3091.41,5008.37 3109.41,4990.38 3109.41,4899.38 3388.41,4620.38 3441.41,4567.38 3441.41,4350.28 IC6.M1@3467.3,4324.38 ; v1(3900.4,6035.38) 3927.41,6035.38 3940.4,6048.37 IC1.27@3940.4,6089.38
  L3 w6: pad.1@2963.41,5413.38 3177.41,5627.38 3699.41,5627.38 3932.4,5860.38 3932.4,6003.38 v1(3900.4,6035.38)
FD3: IC1.28 IC6.M2 pad.1@2905.41,5413.38 | length 2963.3
  Top Layer w6: v1(3856.41,6030.38) 3913.41,6087.38 IC1.28@3913.41,6091.38
  Top Layer w10: v1(3448.41,4303.38) 3466.8,4284.98 IC6.M2@3467.3,4284.98
  L3 w6: v1(2994.41,5176.37) 3010.41,5192.37 3390.41,5192.37 3462.41,5120.37 3462.41,4317.38 v1(3448.41,4303.38)
  Bottom Layer w6: v1(2994.41,5176.37) 2948.41,5222.38 2948.41,5359.38 2905.41,5402.38 2905.41,5428.38 2966.41,5489.38 3296.41,5489.38 3553.41,5746.38 3633.41,5746.38 3855.41,5968.37 3855.41,6029.38 v1(3856.41,6030.38)
FD4: IC1.29 IC6.K3 pad.1@3199.41,5413.38 | length 2296.3
  Top Layer w6: pad.1@3199.41,5413.38 3199.41,5521.38 3304.41,5626.38 3687.41,5626.38 3765.41,5704.37 3889.41,5704.37 3914.41,5729.38 IC1.29@3914.41,5732
  Top Layer w10: IC6.K3@3546.01,4245.58 3563.81,4263.38 v1(3565.41,4263.38)
  L3 w6: pad.1@3199.41,5413.38 3200.41,5413.38 3485.41,5128.37 3485.41,4275.38 3516.41,4244.38 3546.41,4244.38 v1(3565.41,4263.38)
FD5: IC1.30 IC6.K2 pad.1@3259.41,5413.38 | length 2219.8
  Top Layer w6: v1(3189.41,5163.38) 3189.41,5306.38 3259.41,5376.37 pad.1@3259.41,5413.38 3259.41,5523.38 3332.41,5596.38 3715.41,5596.38 3798.41,5679.38 3872.41,5679.38 3888.41,5663.38 3922.41,5663.38 3938.41,5679.38 IC1.30@3938.41,5708.38 ; v1(3225.41,4908.38) 3225.41,4893.38 3236.41,4882.38 3237.41,4882.38 3548.41,4571.38 3548.41,4401.38 3526.41,4379.38 3526.41,4304.58 IC6.K2@3546.01,4284.98
  Bottom Layer w6: v1(3189.41,5163.38) 3189.41,5087.38 3225.41,5051.38 v1(3225.41,4908.38)
FD6: IC1.31 IC6.K1 pad.1@3317.41,5413.38 | length 2136.8
  Top Layer w6: v1(3261.41,5160.37) 3367.41,5266.38 3367.41,5332.38 3317.41,5382.38 pad.1@3317.41,5413.38 ; v1(3267.41,4908.38) 3267.41,4887.38 3563.41,4591.38 3563.41,4384.37 3546.01,4366.98 IC6.K1@3546.01,4324.38 ; IC1.31@3964.4,5732 3966.41,5730 v1(3966.41,5672.37)
  Bottom Layer w6: v1(3261.41,5160.37) 3261.41,4914.38 v1(3267.41,4908.38) ; pad.1@3317.41,5413.38 3317.41,5460.38 3537.41,5680.37 3956.4,5680.37 3964.4,5672.37 v1(3966.41,5672.37)
FD7: IC1.32 IC6.J6 pad.1@3377.41,5413.38 | length 2347.6
  Top Layer w6: v1(3558.41,5341.38) 3539.41,5360.37 3399.41,5360.37 3377.41,5382.38 pad.1@3377.41,5413.38 3377.41,5479.38 3449.41,5551.38 3941.41,5551.38 3989.41,5599.38 IC1.32@3989.41,5732 ; IC6.J6@3585.41,4127.48 3585.51,4127.48 v1(3604.41,4146.38)
  Bottom Layer w6: v1(3558.41,5341.38) 3606.41,5293.38 3606.41,4330.38 3625.41,4311.38 3625.41,4171.38 3604.41,4150.38 v1(3604.41,4146.38)
FD8: IC1.52 IC6.F4 pad.1@4260.4,5413.38 | length 2278.1
  Top Layer w6: v1(3685.41,4226.38) 3703.51,4208.28 IC6.F4@3703.51,4206.28 ; v1(3886.41,5290.38) 3897.41,5290.38 3981.41,5374.38 4221.41,5374.38 pad.1@4260.4,5413.38 4323.41,5476.38 4411.41,5476.38 4429.41,5494.38 4429.41,5639.38 4445.41,5655.38 4473.41,5655.38 4489.41,5671.38 IC1.52@4489.41,5732
  L3 w6: v1(3762.41,4798.38) 3835.41,4798.38 v1(3840.41,4803.38)
  Bottom Layer w6: v1(3685.41,4226.38) 3679.41,4226.38 3665.41,4240.37 3665.41,4313.38 3729.41,4377.38 3787.41,4377.38 3848.41,4438.38 3848.41,4795.38 v1(3840.41,4803.38) ; v1@3761.41,4799.38 3761.41,5198.38 3853.41,5290.38 v1(3886.41,5290.38)
FD9: IC1.53 IC6.E2 pad.1@4320.41,5413.38 | length 1907
  Top Layer w6: v1(3985.41,4620.38) 3986.41,4621.38 v1(3986.41,4686.38) ; pad.1@4320.41,5413.38 4365.41,5458.38 4450.71,5458.38 4544.41,5552.08 4544.41,5649.38 4514.41,5679.38 IC1.53@4514.41,5732
  Top Layer w10: IC6.E2@3742.91,4284.98 3746.01,4284.98 v1(3764.4,4303.38)
  L3 w6: v1(3764.4,4303.38) 3764.4,4341.38 3935.41,4512.37 3935.41,4570.38 v1(3985.41,4620.38) ; v1(3986.41,4686.38) 3987.41,4686.38 4178.41,4877.38 4178.41,5012.38 4223.41,5057.38 4269.51,5057.38 4338.52,5126.38 4339.41,5126.38 4363.41,5150.38 4363.41,5370.38 pad.1@4320.41,5413.38
FD10: IC1.54 IC6.G6 pad.1@4378.41,5413.38 | length 2211.7
  Top Layer w6: IC6.G6@3664.2,4127.48 3664.2,4126.58 v1(3684.41,4106.38) ; v1(4122.41,5243.38) 4122.41,5291.38 4138.41,5307.38 4353.41,5307.38 4378.41,5332.38 pad.1@4378.41,5413.38 4411.71,5446.68 4465.7,5446.68 4560.41,5541.39 4560.41,5658.38 4539.41,5679.38 IC1.54@4539.41,5732
  Bottom Layer w6: v1(3684.41,4106.38) 3705.41,4127.38 3705.41,4215.38 3742.41,4252.38 3742.41,4320.37 3768.41,4346.38 3815.41,4346.38 3956.4,4487.38 3956.4,4698.38 4122.41,4864.37 v1(4122.41,5243.38)
FD11: IC1.55 IC6.D1 pad.1@4438.41,5413.38 | length 1890.8
  Top Layer w6: IC6.D1@3782.3,4324.38 3788.4,4324.38 3938.41,4474.38 3938.41,4694.38 4020.4,4776.37 4020.4,4891.38 v1(4001.41,4910.38) ; pad.1@4438.41,5413.38 4458.41,5433.38 4473.8,5433.38 4577.41,5536.98 4577.41,5662.38 4564.4,5675.38 IC1.55@4564.4,5732
  Bottom Layer w6: v1(4001.41,4910.38) 4001.41,4971.38 4066.41,5036.38 4066.41,5228.38 4129.41,5291.38 4334.41,5291.38 4438.41,5395.38 pad.1@4438.41,5413.38
FD12: IC1.56 IC6.C2 pad.1@4732.4,5235.38 | length 2411.5
  Top Layer w6: IC6.C2@3821.6,4284.98 3840.41,4303.78 3840.41,4335.38 3962.41,4457.38 4080.41,4457.38 4107.41,4484.38 4147.41,4484.38 4169.41,4506.38 4169.41,4628.38 v1(4160.41,4637.38) ; v1(4545.41,5818.38) 4574.41,5818.38 4589.41,5803.38 IC1.56@4589.41,5732
  L3 w6: v1(4160.41,4637.38) 4160.41,4694.38 4295.41,4829.38 4516.4,4829.38 4631.41,4944.37 4631.41,5157.38 4709.41,5235.38 pad.1@4732.4,5235.38
  Bottom Layer w6: v1(4545.41,5818.38) 4544.41,5817.38 4544.41,5502.38 4595.41,5451.38 4691.41,5451.38 4699.41,5443.38 4699.41,5265.38 4729.41,5235.38 pad.1@4732.4,5235.38
FD13: IC1.1 IC6.E3 pad.1@4496.41,5412.38 | length 2560.5
  Top Layer w6: v1(4510.41,5909.38) 4562.34,5909.38 ccw(c4562.34,5926.45) 4574.41,5914.38 ccw(c4538.19,5950.59) 4589.41,5950.59 4589.41,5951.01 IC1.1@4589.41,6100.38
  Top Layer w10: v1(3722.41,4264.37) 3741.21,4245.58 IC6.E3@3742.91,4245.58
  L3 w6: v1(3722.41,4264.37) 3740.4,4282.38 3771.41,4282.38 3783.41,4294.38 3783.41,4331.38 3953.41,4501.38 3953.41,4558.38 4015.41,4620.38 4116.4,4620.38 4137.41,4641.38 4137.41,4713.38 4278.41,4854.38 4488.41,4854.38 4602.41,4968.37 4602.41,5264.37 4553.41,5313.38 v1(4523.41,5313.38)
  Bottom Layer w6: v1(4510.41,5909.38) ccw(c4515.23,5904.55) 4508.4,5904.55 4508.4,5561.38 4496.41,5549.38 4496.41,5383.38 4523.41,5356.38 v1(4523.41,5313.38)
FD14: IC1.2 IC6.F5 pad.1@4556.4,5412.38 | length 3159.8
  Top Layer w6: IC6.F5@3703.51,4166.88 3703.9,4166.88 v1(3723.41,4147.38) ; v1(4215.41,4995.38) 4215.41,4991.38 4260.4,4946.38 4368.41,4946.38 4398.41,4916.38 4451.41,4916.38 4486.41,4881.38 4486.41,4668.38 4523.41,4631.38 4523.41,4265.38 4496.41,4238.38 v1(4453.41,4238.38) ; v1(4559.41,5942.38) ccw(c4547.34,5954.45) 4564.41,5954.45 IC1.2@4564.4,6100.38
  L3 w6: v1(4215.41,4995.38) 4266.92,4995.38 4501.41,5229.87 4501.41,5357.38 pad.1@4556.4,5412.38 4568.41,5424.37 4568.41,5933.38 v1(4559.41,5942.38)
  Bottom Layer w6: v1(3723.41,4147.38) 3725.41,4147.38 3745.41,4127.38 3902.41,4127.38 3956.4,4181.38 3956.4,4210.38 3976.41,4230.38 4417.41,4230.38 4425.41,4238.38 ; 4436.4,4238.38 4425.41,4238.38 ; v1(4453.41,4238.38) 4425.41,4238.38
FD15: IC1.3 IC6.C1 pad.1@4614.41,5412.38 | length 2347.1
  Top Layer w6: IC6.C1@3821.6,4324.38 3821.6,4336.58 3957.41,4472.37 3957.41,4686.38 4045.41,4774.38 4045.41,4987.38 4106.41,5048.37 4301.41,5048.37 4345.41,5092.38 4508.4,5092.38 4614.41,5198.38 pad.1@4614.41,5412.38 ; IC1.3@4539.41,6100.38 4539.41,6023.79 ccw(c4542.82,6023.79) v1(4540.4,6021.38)
  L3 w6: v1(4540.4,6021.38) 4544.03,6021.38 4614.41,5951.01 pad.1@4614.41,5412.38
FIFOADR0: IC1.44 IC6.G3 pad.1@3906.41,5413.38 | length 1900.1
  Top Layer w6: v1(4288.41,5644.38) 4289.41,5645.38 IC1.44@4289.41,5732
  Top Layer w10: v1(3646.41,4264.37) 3664.2,4246.58 IC6.G3@3664.2,4245.58
  Bottom Layer w6: v1(3646.41,4264.37) 3646.41,4328.37 3710.41,4392.37 3754.41,4392.37 3792.41,4430.38 3792.41,5181.38 3851.41,5240.37 3873.41,5240.37 3906.41,5273.38 pad.1@3906.41,5413.38 3957.41,5464.37 4055.41,5464.37 4076.4,5485.38 4151.41,5485.38 4218.41,5552.37 4218.41,5570.38 4288.41,5640.37 v1(4288.41,5644.38)
FIFOADR1: IC1.45 IC6.F1 pad.1@3966.41,5413.38 | length 1806.4
  Top Layer w6: IC6.F1@3703.51,4324.38 3703.51,4332.48 3784.41,4413.38 3784.41,4721.38 3797.41,4734.38 3797.41,4818.38 3888.41,4909.38 3888.41,4965.38 v1(3886.41,4967.38) ; pad.1@3966.41,5413.38 3996.1,5443.08 4242.1,5443.08 4314.41,5515.38 IC1.45@4314.41,5732
  L3 w6: v1(3886.41,4967.38) 3886.41,5243.38 3966.41,5323.38 pad.1@3966.41,5413.38
FIFOADR2: IC1.43 IC6.G1 pad.1@3848.41,5413.38 | length 1913.2
  Top Layer w6: IC6.G1@3664.2,4324.38 3664.2,4359.58 3602.41,4421.38 3602.41,4578.38 3667.41,4643.38 3667.41,4876.38 v1(3824.41,5033.38) ; pad.1@3848.41,5413.38 3892.6,5457.58 4232.61,5457.58 4272.41,5497.38 4272.41,5611.38 4264.41,5619.38 IC1.43@4264.41,5732
  L3 w6: v1(3824.41,5033.38) 3848.41,5057.38 pad.1@3848.41,5413.38
FLAGA: IC1.36 IC6.J4 pad.1@3435.41,5413.38 | length 2164.1
  Top Layer w6: pad.1@3435.41,5413.38 3435.41,5459.38 3483.41,5507.38 3922.41,5507.38 4010.41,5595.38 4010.41,5644.38 4025.41,5659.38 4077.41,5659.38 4089.41,5671.38 IC1.36@4089.41,5732 ; IC6.J4@3585.41,4206.28 3587.3,4206.28 v1(3605.41,4224.37)
  L3 w6: pad.1@3435.41,5413.38 3435.41,5256.37 v1(3570.41,5121.38)
  Bottom Layer w6: v1(3570.41,5121.38) 3587.41,5104.37 3587.41,4242.38 v1(3605.41,4224.37)
FLAGB: IC1.37 IC6.J3 pad.1@3495.41,5413.38 | length 2222
  Top Layer w6: IC1.37@4114.41,5732 4114.41,5659.38 v1(4128.41,5645.38)
  Top Layer w10: v1(3567.41,4225.38) 3585.41,4243.38 IC6.J3@3585.41,4245.58
  L3 w6: v1(3567.41,4225.38) 3567.41,4226.38 3586.51,4245.48 3586.51,4267.88 3570.41,4283.98 3517.8,4283.98 3503.41,4298.38 3503.41,4988.38 3614.41,5099.38 3614.41,5223.38 3586.91,5250.88 ; 3589.41,5248.37 3586.91,5250.88 ; v1(4128.41,5645.38) 4128.41,5623.38 4105.41,5600.37 4050.41,5600.37 4020.4,5570.38 3790.41,5570.38 3728.41,5508.38 3590.41,5508.38 pad.1@3495.41,5413.38 3495.41,5342.38 3586.91,5250.88
FLAGC: IC1.38 IC6.J1 pad.1@3553.41,5413.38 | length 1902.4
  Top Layer w6: v1(3569.41,4349.38) 3585.41,4333.38 IC6.J1@3585.41,4324.38 ; IC1.38@4142.41,5718.38 4142.41,5678.38 v1(4150.41,5670.38)
  L3 w6: pad.1@3553.41,5413.38 3623.41,5483.38 3742.41,5483.38 3808.41,5549.38 4026.41,5549.38 4059.41,5582.38 4107.41,5582.38 4150.41,5625.38 v1(4150.41,5670.38)
  Bottom Layer w6: pad.1@3553.41,5413.38 3530.41,5390.38 3530.41,4642.38 3569.41,4603.38 v1(3569.41,4349.38)
FLAGD/CS#: IC1.47 IC6.F3 pad.1@4143.41,5413.38 | length 1967.8
  Top Layer w6: IC1.47@4364.4,5732 4364.4,5667.38 v1(4368.41,5663.38)
  Top Layer w10: v1(3685.41,4264.37) 3703.51,4246.28 IC6.F3@3703.51,4245.58
  Bottom Layer w6: v1(3685.41,4264.37) 3709.41,4288.37 3709.41,4316.38 3756.4,4363.38 3802.41,4363.38 3930.41,4491.38 3930.41,4610.38 3912.41,4628.38 3912.41,4812.38 3972.4,4872.37 3972.4,5176.37 4143.41,5347.38 pad.1@4143.41,5413.38 4178.41,5448.37 4309.41,5448.37 4423.41,5562.38 4423.41,5651.38 4411.41,5663.38 v1(4368.41,5663.38)
FLASH_CS#: IC6.T3 IC14.1 J17.6 | length 1361.7
  Top Layer w6: J17.6@2279.41,4153.38 2589.41,4153.38 2606.41,4170.38 IC14.1@2606.41,4248.73 2606.41,4259.38 2738.41,4391.38 2879.41,4391.38 2894.41,4376.37 3145.41,4376.37 v1(3146.41,4377.38) ; v1(3187.41,4439.38) 3187.41,4418.38 3265.41,4340.38 3265.41,4272.37 3292.2,4245.58 IC6.T3@3309.8,4245.58
  Bottom Layer w6: v1(3146.41,4377.38) 3146.41,4404.38 3181.41,4439.38 v1(3187.41,4439.38)
FLASH_IO0: IC6.T10 IC14.5 J17.5 | length 1191.3
  Top Layer w6: J17.5@2279.41,4053.38 2311.41,4021.38 2373.41,4021.38 2400.41,4048.37 2456.41,4048.37 ; IC14.5@2456.41,3952.03 2456.41,4048.37 ; IC6.T10@3309.8,3969.98 3296.8,3969.98 3268.41,3998.38 3268.41,4011.38 3243.41,4036.38 2729.41,4036.38 2717.41,4048.37 2456.41,4048.37
FLASH_IO1: IC6.P10 IC14.2 J17.7 | length 1404.6
  Top Layer w6: J17.7@2279.41,4253.38 2334.41,4253.38 2409.41,4178.38 2541.41,4178.38 2548.41,4185.38 v1(2548.41,4197.38) 2556.41,4205.38 IC14.2@2556.41,4248.73 ; v1(3368.41,3950.38) 3388.01,3969.98 IC6.P10@3388.61,3969.98
  L3 w6: v1(2689.01,4024.98) 2689.01,4021.19 2693.84,4016.35 2693.84,4014.94 2833.41,3875.38 3259.41,3875.38 3334.41,3950.38 v1(3368.41,3950.38) v1@3368.41,3949.88
  Bottom Layer w6: v1(2548.41,4197.38) 2548.41,4165.58 v1(2689.01,4024.98)
FLASH_IO2: IC14.3 | length 102.6
  Top Layer w6: v3(2469.41,4335.38) 2470.41,4335.38 2506.41,4299.38 IC14.3@2506.41,4248.73
FLASH_IO3: IC14.7 | length 99
  Top Layer w6: IC14.7@2556.41,3952.03 2556.41,3888.37 v3(2581.41,3863.38)
FLASH_SPI_CLK: IC6.R11 IC14.6 J17.4 R28.2 R29.2 | length 1619.9
  Top Layer w6: J17.4@2279.41,3953.38 2380.41,3953.38 2381.41,3954.38 2436.41,3899.38 2507.41,3899.38 ; IC14.6@2506.41,3952.03 2506.41,3942.38 2507.41,3941.38 2507.41,3899.38 ; R29.2@2508.95,3770.38 2507.41,3771.92 R28.2@2507.41,3854.38 2507.41,3899.38 ; v1(3284.41,3956.38) 3290.41,3950.38 3329.51,3950.38 IC6.R11@3349.21,3930.68
  L3 w6: J17.4@2279.41,3953.38 2298.41,3953.38 2400.41,4055.38 3223.41,4055.38 3284.41,3994.38 v1(3284.41,3956.38)
GND: C1.2 C2.1 C4.1 C5.1 C6.1 C7.1 C12.2 C13.1 C14.1 C15.2 C16.1 C17.2 C18.2 C19.1 C20.1 C21.2 C22.2 C23.2 C24.2 C25.2 C26.2 C27.2 C28.1 C29.1 C30.2 C31.2 C32.1 C33.2 C34.2 C35.1 C36.1 C37.1 C38.1 C39.1 C40.2 C41.2 C42.2 C43.2 C44.1 C45.1 C46.1 C47.1 C48.1 C49.1 C50.1 C51.2 C54.2 C55.1 C56.2 C57.2 C61.2 C67.2 C68.2 C69.2 C70.2 C71.1 C72.1 C75.1 C76.1 C77.1 C78.1 C80.2 C81.2 C82.2 C84.1 C85.1 C89.2 C92.2 C94.1 C95.2 C96.1 C97.1 C98.1 C99.2 C108.2 C109.2 C110.2 C111.1 C112.2 C113.1 C114.1 C115.1 C116.1 C118.2 C119.2 C120.1 C122.2 C123.1 C124.2 C125.2 C126.1 C127.1 C128.1 C129.2 C130.1 C131.1 C132.2 C133.1 C134.1 C135.2 C136.1 C137.2 C138.2 C139.2 C140.1 C141.1 C142.2 C143.2 C144.1 C147.2 C148.2 C149.2 C150.2 CN1.1 CN1.2 CN1.3 CN1.4 CN2.1 CN2.2 CN2.3 CN2.4 CN3.5 CN3.6 CN3.7 CN3.8 CN4.1 CN4.2 CN4.3 CN4.4 CN5.5 CN5.6 CN5.7 CN5.8 CN6.1 CN6.2 CN6.3 CN6.4 CN7.5 CN7.6 CN7.7 CN7.8 CN8.5 CN8.6 CN8.7 CN8.8 D1.2 D2.2 D3.2 D4.1 D6.2 D15.2 D16.2 D18.1 D19.2 D22.2 IC1.4 IC1.7 IC1.13 IC1.17 IC1.19 IC1.21 IC1.33 IC1.35 IC1.48 IC2.4 IC3.1 IC3.2 IC4.2 IC5.1 IC5.7 IC6.A1 IC6.A16 IC6.B7 IC6.B11 IC6.D4 IC6.D13 IC6.E9 IC6.G2 IC6.G8 IC6.G15 IC6.H7 IC6.H9 IC6.H12 IC6.J5 IC6.J8 IC6.K7 IC6.K9 IC6.L2 IC6.L15 IC6.M8 IC6.N13 IC6.P3 IC6.R6 IC6.R10 IC6.T1 IC6.T16 IC7.7 IC8.1 IC8.7 IC8.8 IC8.9 IC8.12 IC8.16 IC9.8 IC10.1 IC10.2 IC10.3 IC10.4 IC11.2 IC11.4 IC12.2 IC13.2 IC14.4 IC15.2 IC15.5 IC17.4 IC18.4 IC19.2 IC19.3 IC20.1 IC20.3 IC20.9 IC20.10 IC21.1 IC21.10 IC21.19 IC22.9 IC22.13 IC22.14 IC26.2 IC27.4 IC27.5 IC28.5 IC29.2 IC30.3 IC31.4 IC32.2 IC32.8 IC33.14 IC34.2 J1.2 J1.4 J1.6 J2.1 J6.5 J7.2 J7.4 J7.6 J7.8 J7.10 J7.12 J7.14 J11.3 J11.4 J11.7 J11.8 J11.17 J12.3 J18.1 J18.2 J18.3 J18.4 J19.1 J19.2 J19.3 J19.4 J21.1 J21.2 J21.3 J21.4 J22.1 J22.2 J22.3 J22.4 J24.2 J25.1 J25.2 J25.3 J25.4 J25.5 J29.1 J29.3 J29.5 J29.7 J29.9 J29.11 J29.13 J30.1 J31.1 J32.1 J33.3 J34.1 J34.2 J34.3 J34.4 J35.2 J38.2 J39.1 J39.2 J39.3 J39.4 J40.2 J41.1 J41.2 J41.3 J41.4 J42.3 J43.1 J44.4 J45.1 J45.2 J45.3 J45.4 LED1.1 LED3.1 LED5.1 OP2.2 P1.5 P1.10 P1.13 P1.19 P1.26 P1.29 P1.33 P1.40 pad.1@177.17,7775.59 pad.1@237.41,3976.38 pad.1@3110.24,7716.54 pad.1@3425.2,3208.66 pad.1@3425.2,5944.88 pad.1@3503.94,236.22 pad.1@5295.28,196.85 pad.1@5334.65,7775.59 pad.1@5354.33,5944.88 pad.1@5354.41,3660.38 R2.2 R6.2 R28.1 R30.1 R35.2 R37.2 R43.2 R44.2 R81.1 R82.1 R83.1 R84.2 R87.1 R89.2 R92.2 R94.1 R98.2 R115.1 R116.1 R119.2 R124.2 TP2.1 TP9.1 TP11.1 TP15.1 TP111.1 TR4.2 TR5.2 TR6.2 TR9.2 TR10.1 TR11.1 TR12.1 TR13.1 | length 15145.1
  Top Layer w6: v1(123.41,6908.38) 127.41,6912.37 C136.1@182.86,6912.37 ; R83.1@1117.41,7315.84 1117.41,7257.38 v1(1120.41,7254.38) ; C108.2@1120.41,7500.83 1122.41,7498.83 v1(1122.41,7466.38) ; C109.2@1336.41,7159.84 1336.41,7112.37 v1(1338.41,7110.38) ; R82.1@1524.41,7170.83 1524.41,7126.38 v1(1531.41,7119.38) ; v1(1582.41,2424.38) 1586.1,2420.68 C118.2@1586.1,2373.98 ; TR5.2@1633.64,2671.48 1670.51,2671.48 v1(1674.41,2675.38) ; C119.2@1656.95,2165.38 1705.41,2165.38 v1(1711.41,2171.38) ; v1(1785.41,3593.38) 1791.81,3586.98 C134.1@1848.3,3586.98 ; v1(1785.41,7443.38) 1788.41,7446.38 R81.1@1788.41,7494.83 ; IC31.4@1815.79,5004.82 v1(1843.41,5004.82) ; v1(1846.41,7482.38) 1850.86,7486.83 C110.2@1880.41,7486.83 ; R115.1@1923.41,3445.92 1967.95,3445.92 v1(1972.41,3450.38) ; v1(2227.41,2448.94) IC28.5@2227.41,2482.4 ; v1(2409.41,3661.38) 2417.41,3653.38 R30.1@2474.86,3653.38 ; v1(2413.41,4296.37) 2441.41,4296.37 2456.41,4281.38 IC14.4@2456.41,4248.73 ; IC10.3@2798.41,5275.38 2829.41,5244.38 IC15.5@2829.41,5165.38 ; IC15.2@2866.8,5070.88 2866.8,5138.17 v1(2867.01,5138.38) ; v1(3032.41,1684.38) 3034.41,1686.38 IC8.12@3085.75,1686.38 ; IC6.R10@3349.21,3969.98 3349.21,3970.18 v1(3368.41,3989.38) ; IC6.R6@3349.21,4127.48 3349.3,4127.48 v1(3369.41,4107.38) ; IC6.P3@3388.61,4245.58 3388.61,4245.17 v1(3409.41,4224.37) ; IC6.N13@3426.91,3851.87 IC6.N13@3427.91,3851.87 ; v1(3447.41,4067.38) IC6.M8@3468.41,4046.38 ; v1(3486.41,3751.38) 3506.71,3771.68 IC6.L15@3506.71,3773.17 ; v1(3564.41,4186.38) 3583.91,4166.88 IC6.J5@3585.41,4166.88 ; v1(3604.41,3870.38) 3624.8,3890.78 IC6.H12@3624.8,3891.28 ; IC6.H9@3624.8,4009.38 IC6.H9@3625.41,4009.38 ; v1(3723.41,3989.38) 3742.91,4008.88 IC6.E9@3742.91,4009.38 ; v1(3763.41,4186.38) 3782.3,4205.28 IC6.D4@3782.3,4206.28 ; v1(3841.41,3909.38) 3861,3928.98 IC6.B11@3861,3930.68 ; IC6.B7@3861,4087.98 IC6.B7@3861,4088.17 ; v1@4064.41,5797.38 v1(4065.41,5798.38) ; v1(4186.41,6038.38) v1@4189.41,6041.38 ; v1@4289.41,6172.38 v1(4292.4,6175.38) ; v1@4457.48,5567.45 C2.1@4489.41,5567.45 ; v1(4681.41,5671.38) 4686.4,5666.39 C32.1@4686.4,5615.78 ; v1(4845.41,4942.38) R84.2@4845.41,5001.83 ; v1(4866.41,3847.38) 4869.63,3844.15 IC7.7@4869.63,3797.52 ; R6.2@5015.41,3396.83 5015.41,3351.38 5020.4,3346.38 v1(5052.4,3346.38) ; v1(5091.41,3638.38) 5093.41,3640.38 R2.2@5093.41,3689.83 ; C124.2@5298.41,2547.47 5298.41,2585.38 v1(5301.41,2588.38) ; C122.2@5432.41,2548.46 5432.41,2584.38 v1(5435.41,2587.38)
  Top Layer w10: R89.2@737.41,6348.83 767.95,6348.83 v1(786.41,6330.38) ; v1(801.41,1142.38) 807.95,1135.83 C89.2@807.95,1088.38 ; v1(851.41,957.38) 870.41,938.38 C85.1@913.86,938.38 ; C92.2@853.95,586.38 853.95,625.92 v1(854.41,626.38) ; C130.1@861.41,1617.83 910.95,1617.83 v1(915.41,1613.38) ; v1(883.71,6514.38) 887.71,6510.38 C113.1@946.32,6510.38 ; v1(926.41,2751.38) 927.57,2752.53 IC21.1@980.17,2752.53 ; v1(976.41,2489.38) 980.17,2493.14 IC21.10@980.17,2522.22 ; C132.2@979.95,476.38 979.95,515.92 v1(985.41,521.38) ; R35.2@1079.81,6192.98 1122.8,6192.98 v1(1123.41,6192.37) ; C82.2@1080.95,1463.38 1080.95,1507.92 v1(1084.41,1511.38) ; v1(1086.41,1945.38) 1094.41,1937.38 C95.2@1094.41,1885.92 ; IC20.3@1120.41,3062.38 1163.41,3062.38 v1(1167.41,3066.38) ; IC20.1@1121.41,2963.38 1152.41,2963.38 v1(1166.41,2949.38) ; IC21.19@1200.64,2726.94 1247.84,2726.94 v1(1257.41,2717.38) ; v1(1221.41,553.38) 1226.41,558.38 C133.1@1226.41,613.64 ; v1(1238.41,1937.38) 1250.36,1925.42 C129.2@1279.41,1925.42 ; C72.1@1253.41,1007.83 1294.86,1007.83 v1(1297.41,1010.38) ; v1(1325.41,1692.38) 1328.91,1695.88 IC22.14@1328.91,1736.74 ; IC22.13@1353.91,1736.74 1353.91,1704.87 v1(1363.41,1695.38) ; IC22.9@1378.91,1532.01 1378.91,1480.87 v1(1381.41,1478.38) ; TR6.2@1442.41,2560.38 1460.41,2560.38 v1(1472.41,2572.38) ; C84.1@1500.41,670.83 1500.41,628.38 v1(1505.41,623.38) ; v1(1524.41,1811.38) 1531.81,1818.78 D19.2@1531.81,1849.7 ; IC33.14@1590.75,1106.38 v1(1636.41,1106.38) ; v1(1599.41,630.38) 1610.41,641.38 C131.1@1610.41,675.14 ; R44.2@1671.04,2499.98 1688.01,2499.98 v1(1707.41,2519.38) ; v1(1678.41,2425.38) 1688.86,2414.92 C114.1@1688.86,2384.38 ; v1(1814.41,3934.38) 1822.96,3942.94 IC18.4@1844.02,3942.94 ; C71.1@1847.52,5866.38 1949.41,5866.38 v2(1950.41,5867.38) ; D18.1@1867.64,4830.67 1867.64,4795.15 v1(1883.41,4779.38) ; v1(1957.41,2243.38) 1977.41,2263.38 C115.1@2013.29,2263.38 ; v1(2014.41,2362.38) 2015.41,2361.38 C116.1@2066.86,2361.38 ; IC29.2@2264.65,2210.58 2264.65,2243.62 v1(2266.41,2245.38) ; v1(2319.41,6261.38) 2327.43,6253.35 C50.1@2327.43,6202.19 ; v1(2335.41,2508.38) 2362.41,2481.38 R92.2@2362.41,2452.92 ; v1(2388.41,3861.38) 2395.41,3854.38 R28.1@2450.32,3854.38 ; v1(2451.41,5717.38) 2455.8,5721.78 IC13.2@2455.8,5758.88 ; C43.2@2533,5509.68 2568.71,5509.68 v1(2573.41,5514.38) ; v1(2732.41,639.38) 2733.81,640.78 2753.18,640.78 2754.02,641.62 IC17.4@2754.02,652.93 ; v1(2883.41,6829.38) R87.1@2932.86,6829.38 ; C149.2@2979.5,1207.38 C149.2@2981.5,1209.38 ; v1(2996.41,3565.38) 3003.41,3558.38 C39.1@3055.86,3558.38 ; v1(3015.41,3710.38) 3029.41,3696.37 C38.1@3078.86,3696.37 ; v1(3028.41,3815.38) 3044.41,3799.38 C37.1@3082.86,3799.38 ; v1(3081.41,3973.38) 3082.66,3972.12 CN8.6@3123.93,3972.12 ; v1(3083.41,3939.38) 3084.66,3940.63 CN8.7@3123.93,3940.63 ; v1(3083.41,4015.38) 3095.16,4003.62 CN8.5@3123.93,4003.62 ; v1(3086.41,3907.38) 3088.16,3909.13 CN8.8@3123.93,3909.13 ; v1(3222.41,5281.38) 3269.47,5281.38 D1.2@3274.47,5286.38 ; v1(3274.41,3708.38) 3299.81,3733.78 IC6.T16@3309.8,3733.78 ; IC6.T1@3309.8,4324.38 3312.41,4324.38 v1(3333.41,4303.38) ; v1(3407.41,3871.38) IC6.N13@3426.91,3851.87 ; IC6.L2@3506.71,4284.98 3506.71,4284.08 v1(3527.41,4263.38) ; C33.2@3507.41,4504.92 3507.41,4539.02 3524.41,4556.02 v1(3524.41,4557.38) ; IC6.K9@3546.01,4009.38 3546.01,4008.58 3564.41,3990.18 v1(3564.41,3989.38) ; IC6.K7@3546.01,4088.17 3546.1,4088.17 3564.31,4106.38 v1(3564.41,4106.38) ; IC6.J8@3585.41,4048.78 3585.6,4048.78 3604.21,4067.38 v1(3604.41,4067.38) ; IC6.H7@3624.8,4088.17 3625.21,4088.17 3645,4068.38 v1(3645.41,4068.38) ; IC6.H9@3625.41,4009.38 3625.41,4009.68 3645.1,4029.38 v1(3645.41,4029.38) ; v1(3645.41,3792.37) IC6.G15@3664.2,3773.58 ; IC6.G8@3664.2,4048.78 3664.2,4049.48 3682.41,4067.68 v1(3682.41,4068.38) ; IC6.G2@3664.2,4284.98 3667.01,4284.98 v1(3685.41,4303.38) ; v1(3774.41,5788.38) 3776.63,5790.61 IC3.2@3823.35,5790.61 ; IC6.D13@3782.3,3851.87 3784.91,3851.87 v1(3803.41,3870.38) ; v1(3841.41,4068.38) IC6.B7@3861,4087.98 ; v1(3856.41,5645.38) 3866.86,5634.92 C13.1@3866.86,5611.38 ; v1(3882.41,4303.38) 3900.4,4321.38 IC6.A1@3900.4,4324.38 ; v1(3885.41,3701.55) 3887.32,3703.47 3887.32,3718.61 3900.4,3731.69 IC6.A16@3900.4,3733.78 ; C14.1@4057.41,5553.83 4093.86,5553.83 v1(4099.41,5559.38) ; v1(4084.4,6042.38) 4084.4,6045.08 v1@4088.64,6049.32 ; IC1.21@4088.64,6099.62 IC1.21@4089.41,6100.38 ; v1(4127.41,6168.37) 4139.41,6156.38 ; C7.1@4203.41,5540.83 4243.87,5540.83 v1(4248.41,5545.38) ; v1(4213.41,5165.38) 4221.95,5156.83 C15.2@4252.4,5156.83 ; v1(4438.41,2366.38) 4440.41,2364.38 IC32.8@4440.41,2294.36 ; IC1.7@4439.41,6100.38 4439.41,6046.35 ccw(c4480.38,6046.35) v3(4451.41,6017.38) ; v1(4498.41,4965.38) 4502.61,4969.58 IC2.4@4502.61,5022.09 ; IC32.2@4740.4,2294.36 v1(4740.4,2351.38) ; IC11.2@4854.61,5929.82 4854.61,5890.17 v1(4856.41,5888.37) ; IC11.4@4905.79,5929.82 4905.79,5890.99 v1(4908.4,5888.37) ; v1(5124.4,5733.38) 5134,5723.78 IC12.2@5134,5686.38 ; v1(5216.41,3130.38) LED5.1@5295.67,3130.38 ; v1(5243.41,3484.38) 5266.41,3461.38 D2.2@5266.41,3424.32 ; C61.2@5428.4,3445.47 5428.4,3410.38 v1(5438.41,3400.38)
  Top Layer w12: v1(3567.41,5774.38) 3583.64,5790.61 IC3.1@3615.46,5790.61 ; C21.2@3785.49,6246.38 3831.41,6246.38 v1(3837.41,6252.38) ; C12.2@3982.5,6250.38 3982.5,6290.47 v3(3984.41,6292.38) ; IC1.33@4014.41,5732 v1(4014.41,5798.38) ; IC1.35@4064.41,5732 v1@4064.41,5797.38 ; C5.1@4086.41,6255.38 4086.41,6289.38 v1(4087.41,6290.38) ; v1@4088.64,6049.32 IC1.21@4088.64,6099.62 ; IC1.19@4139.41,6100.38 4139.41,6156.38 ; v1@4189.41,6041.38 IC1.17@4189.41,6100.38 ; v1(4270.41,6210.38) 4290.41,6230.38 C6.1@4290.41,6253.38 ; IC1.13@4289.41,6100.38 v1@4289.41,6172.38 ; v1(4385.41,5799.38) 4389.41,5795.38 IC1.48@4389.41,5732 ; IC1.4@4514.41,6100.38 v1(4514.41,6167.38) ; v1(4549.41,6204.38) 4558.5,6213.46 C1.2@4558.5,6246.38
  Top Layer w15: v1(1206.41,6535.38) 1207.41,6536.38 LED3.1@1287.67,6536.38 ; C112.2@1663.5,6442.38 1724.41,6442.38 v1(1725.41,6443.38) ; v1(1664.41,4825.38) 1666.01,4826.98 R98.2@1666.01,4873.98 ; D6.2@1699.01,6586.38 1772.41,6586.38 v2(1774.41,6588.38) ; C139.2@1848.49,1830.38 1848.49,1782.29 v2(1873.41,1757.38) ; v1(1867.41,5103.38) 1888.4,5124.37 C125.2@1888.4,5156.98 ; C4.1@2705.41,208.38 2705.41,149.38 v1(2708.41,146.38) ; C51.2@2714.12,3846.38 2750.41,3846.38 v1(2755.41,3851.38) ; v1(2797.41,3957.38) 2801.41,3953.38 C47.1@2860.29,3953.38 ; v1(2801.41,4480.37) 2814.41,4467.38 C45.1@2857.2,4467.38 ; v1(2809.41,4283.38) 2820.41,4272.37 C46.1@2871.29,4272.37 ; C44.1@2905.41,4814.58 2905.41,4866.38 v1(2910.41,4871.38) ; R37.2@2979.81,560.98 3020.54,560.98 cw(c3020.54,555.51) v1(3024.41,559.38) ; v1(3084.41,4325.38) 3084.66,4325.63 CN7.5@3121.93,4325.63 ; v1(3085.41,4295.38) 3086.66,4294.13 CN7.6@3121.93,4294.13 ; v1(3086.41,4232.37) 3087.66,4231.13 CN7.8@3121.93,4231.13 ; v1(3086.41,4263.38) 3087.16,4262.63 CN7.7@3121.93,4262.63 ; v1(3101.41,4489.38) 3121.86,4509.83 C35.1@3121.86,4525.38 ; v1(3103.41,4120.37) 3104.41,4119.38 C36.1@3130.86,4119.38 ; v1(3173.41,3359.38) 3209.41,3359.38 3221.41,3371.38 C40.2@3221.41,3393.59 ; v1(3292.41,4549.38) 3299.91,4541.88 CN5.8@3299.91,4515.34 ; v1(3324.41,4549.38) 3331.41,4542.38 CN5.7@3331.41,4515.34 ; v2(3326.41,6135.38) 3340.41,6149.38 C29.1@3394.78,6149.38 ; v1(3357.41,4550.38) 3362.91,4544.88 CN5.6@3362.91,4515.34 ; v1(3387.41,4549.38) 3394.41,4542.38 CN5.5@3394.41,4515.34 ; CN6.1@3438.16,3472.9 3438.16,3435.63 v1(3446.41,3427.38) ; CN6.2@3469.66,3472.9 3469.66,3441.13 v1(3480.41,3430.38) ; CN6.3@3501.16,3472.9 3501.16,3446.63 v1(3510.41,3437.38) ; CN6.4@3532.66,3472.9 3532.66,3441.13 v1(3539.41,3434.38) ; C22.2@3605.41,6129.92 3631.95,6129.92 v1(3643.41,6141.38) ; v1(3648.41,3396.38) 3663.41,3411.38 C31.2@3663.41,3433.83 ; CN3.8@3657.41,4520.37 v1(3657.41,4554.38) ; v1(3687.41,4554.38) 3688.66,4553.13 CN3.7@3688.66,4516.85 ; CN3.6@3720.15,4516.85 3720.15,4554.13 v1(3720.41,4554.38) ; CN3.5@3751.65,4516.85 3751.65,4553.63 v1(3752.41,4554.38) ; CN4.1@3795.16,3469.9 3795.16,3429.63 v1(3795.41,3429.38) ; v1(3826.41,3429.38) 3826.66,3429.63 CN4.2@3826.66,3469.9 ; CN4.3@3858.16,3469.9 3858.16,3429.63 v1(3858.41,3429.38) ; C30.2@3860.4,4528.37 3882.41,4528.37 3884.4,4530.38 v1(3907.41,4530.38) ; CN4.4@3889.66,3469.9 3889.66,3429.13 v1(3890.41,3428.38) ; C23.2@4098.95,4527.38 4120.41,4527.38 v1(4143.41,4550.38) ; C24.2@4108.94,4207.38 v1(4167.41,4207.38) ; CN1.1@4114.89,4285.13 4154.66,4285.13 v1(4155.41,4284.38) ; CN1.2@4114.89,4316.63 v1(4155.41,4316.63) ; CN1.3@4114.89,4348.12 4155.16,4348.12 v1(4156.4,4349.38) ; CN1.4@4114.89,4379.62 4150.66,4379.62 v1(4151.41,4380.38) ; v3(4201.41,4456.37) C16.1@4261.41,4456.37 ; C26.2@4203.95,3757.38 4225.41,3757.38 v1(4235.41,3767.38) ; C27.2@4207.95,3617.38 4242.41,3617.38 v1(4246.41,3621.38) ; C25.2@4208.94,3875.38 4245.41,3875.38 v1(4255.41,3885.38) ; CN2.1@4212.89,4040.12 4245.16,4040.12 v1(4246.41,4041.38) ; CN2.2@4212.89,4071.62 4246.66,4071.62 v1(4247.41,4072.37) ; CN2.3@4212.89,4103.13 4246.66,4103.13 v1(4249.41,4100.38) ; CN2.4@4212.89,4134.63 4252.15,4134.63 v1(4252.4,4134.38) ; v3(4326.41,3235.38) 4328.41,3237.38 C20.1@4388.29,3237.38 ; C18.2@4455.41,4133.38 4494.41,4133.38 v1(4497.41,4136.37) ; C17.2@4460.91,4304.37 v1(4502.26,4304.37) ; R94.1@4980.4,2097.92 4980.4,2151.38 v1(4984.41,2155.38) ; C42.2@5068.4,5949.38 5093.41,5949.38 v1(5110.41,5966.38) ; IC30.3@5078.41,2123.88 5137.91,2123.88 v1(5141.41,2120.38)
  Top Layer w20: v1(814.41,6762.58) IC27.5@883.71,6762.58 ; TR4.2@873.09,6258.78 v1(873.09,6316.38) ; D22.2@951.51,1956.14 993.64,1956.14 v1(1001.41,1948.38) ; IC27.4@1092.69,6762.58 v1(1160.41,6762.58) ; IC20.9@1101.41,3363.38 v1(1168.41,3363.38) ; IC20.10@1101.41,3413.38 1167.41,3413.38 v1(1168.41,3412.38) ; v1(1227.41,3458.38) 1233.4,3452.38 C75.1@1233.4,3403.78 ; C77.1@1234.4,3047.28 1234.4,3094.37 v1(1237.41,3097.38) ; C80.2@1340.33,2817.05 1380.74,2817.05 v1(1387.41,2810.38) ; v1(1344.41,3462.38) 1357.41,3449.38 C76.1@1357.41,3404 ; C78.1@1357.4,3048.28 1357.4,3092.37 v1(1359.41,3094.38) ; R43.2@1423.81,2657.98 1449.01,2657.98 1462.41,2671.38 v1(1462.41,2699.38) ; v1(1544.41,2892.38) 1559.34,2907.31 C81.2@1559.33,2938.99 ; R124.2@2255.95,702.38 2298.41,702.38 v1(2303.41,707.38) ; v1(2360.41,4921.38) 2367.41,4928.37 LED1.1@2367.41,5001.64 ; D16.2@2602.41,658.48 2602.41,662.62 2622.41,682.62 2622.41,766.38 2648.01,791.98 IC26.2@2701.91,791.98 2702.31,792.38 v1(2732.41,792.38) ; C141.1@2709.41,1863.92 v1(2709.41,1902.38) ; C140.1@2713.41,1770.92 v1(2713.41,1809.38) ; v2(2854.41,1467.38) 2854.41,1478.2 2862.41,1486.2 2862.41,1536.22 2862.56,1536.38 IC8.8@2869.06,1536.38 ; IC8.7@2869.06,1586.38 2931.41,1586.38 v1(2932.41,1587.38) ; C48.1@2898.41,3524.92 2898.41,3573.38 v1(2902.41,3577.38) ; IC34.2@2929.9,991.98 2930.3,992.38 2964.4,992.38 2985.75,1013.72 2985.75,1035.72 v2(2993.41,1043.38) ; C148.2@2944.95,1104.38 2981.69,1104.38 2985.75,1100.32 2985.75,1051.03 v2(2993.41,1043.38) ; v2@3003.41,1051.38 2995.41,1043.38 v2(2993.41,1043.38) ; v1(3016.41,3298.38) 3036.41,3298.38 3050.41,3312.38 C41.2@3050.41,3331.83 ; C147.2@3022.49,862.38 3111.41,862.38 v2(3123.41,874.38) ; IC8.16@3085.75,1886.38 3085.75,1948.72 v2(3086.41,1949.38) ; v1(3189.41,1993.38) 3206.32,1976.46 C94.1@3206.32,1945.38 ; C150.2@3245.5,1549.38 3289.41,1549.38 v1(3291.41,1551.38) ; R119.2@3258.95,1660.38 3298.41,1660.38 v1(3307.41,1669.38) ; C138.2@3260.95,1758.38 3292.41,1758.38 v1(3301.41,1767.38) ; v1(3266.41,3563.38) 3266.86,3563.83 C34.2@3301.41,3563.83 ; v1(3376.41,1498.38) 3382.49,1492.29 C137.2@3382.49,1434.38 ; v1(3997.41,3234.38) 4006.41,3243.38 C28.1@4006.41,3278.26 ; v1(4207.41,3222.38) 4224.41,3239.38 C19.1@4224.41,3278.38 ; IC4.2@4325,4686.38 4325,4750.98 v2(4333.41,4759.38) ; v3(4326.41,3235.38) 4329.41,3238.38 C20.1@4399.41,3238.38 ; v1(4495.41,1796.38) 4503.41,1804.38 C128.1@4558.6,1804.38 ; v1(4738.41,1635.38) 4743.38,1640.35 C127.1@4743.39,1674.48 ; C126.1@4849.34,1675.02 4849.34,1622.45 v1(4853.41,1618.38) ; v1(5054.41,1349.38) 5067.41,1362.38 C120.1@5067.41,1390.26 ; C123.1@5180.4,1387.26 5180.4,1345.38 v1(5183.41,1342.38) ; R116.1@5264.41,1282.29 5292.49,1282.29 5299.51,1275.27 TR9.2@5329.17,1275.27 5329.17,1229.89 5332.69,1226.38 v1(5362.41,1226.38)
  Top Layer w30: D4.1@805.35,306.38 806.25,306.38 v1(855.41,355.54) ; D3.2@1120.34,301.38 1147.41,301.38 v1(1164.41,318.38) ; v2(4282.41,1226.38) 4367.41,1141.38 IC9.8@4367.41,1116.38
  Top Layer w40: C68.2@2182.41,7551.99 2185.06,7549.34 2185.06,7478.13 v2(2187.71,7475.48) ; C144.1@2225.41,795.76 2315.79,795.76 v2(2340.41,820.38) ; C149.2@2981.5,1209.38 v2(3037.41,1209.38) ; v2(3928.41,1479.38) 3946.41,1461.38 J40.2@4066.18,1461.38
  Top Layer w60: C143.2@1827.5,562.38 v2@1827.5,655.29 ; v2(2040.41,7452.38) 2043.41,7455.38 C67.2@2043.41,7537.68 ; v2(2059.41,2008.38) C142.2@2059.41,2126.08 ; v2(2626.41,7440.37) 2630.41,7444.38 C69.2@2630.41,7515.29 ; C70.2@2791.41,7522.97 2791.41,7441.38 v2(2792.41,7440.37)
  L2 w6: v1(5301.41,2588.38) v1@5302.41,2587.38
  Bottom Layer w20: v1(62.41,6467.38) C111.1@121.29,6467.38 ; TR11.1@227.65,6158.78 227.65,6199.62 v1(233.41,6205.38) ; TR10.1@227.87,6320.78 227.87,6358.85 v1(230.41,6361.38) ; v1(228.41,6038.38) 229.65,6037.14 TR12.1@229.65,6002.78 ; TR13.1@231.65,5839.78 231.65,5864.62 v1(239.41,5872.37)
  Bottom Layer w30: J1.6@1284.85,7378.47 1310.98,7404.6 C55.1@1310.98,7494.75 ; C54.2@1411.63,7494.12 1411.63,7417.05 J1.4@1450.21,7378.47 ; J1.2@1615.56,7378.47 1665.87,7428.78 C49.1@1665.87,7491.2 ; C56.2@2013.41,6262.47 2024.49,6251.38 IC5.1@2132.41,6251.38 ; C57.2@2027.41,5638.29 2072.32,5638.29 2085.41,5651.38 IC5.7@2132.41,5651.38
  Bottom Layer w40: C99.2@447.14,5727.45 516.48,5727.45 555.41,5766.38 J25.1@555.41,5802.96 ; C98.1@447.73,5994.65 529.07,5994.65 J25.2@555.41,5968.32 ; C97.1@453.41,6177.38 511.7,6177.38 J25.3@555.41,6133.67 ; C96.1@454.21,6362.9 J25.5@555.41,6464.1
  Bottom Layer w60: v2(2187.71,7475.48) 2191.16,7478.93 2307.96,7478.93 TP111.1@2311.41,7482.38 2311.51,7482.48 2418.31,7482.48 v2(2418.41,7482.58) ; v2(2626.41,7440.37) v2(2792.41,7440.37)
  other v1: 2858.41,4582.38 4455.41,5565.38
  other v2: 1827.41,655.38 1868.41,1245.38 3070.41,1461.38 2417.41,1492.38 2879.41,1948.38
GND1: C74.2 C79.1 D7.2 D8.2 IC19.16 IC25.4 IC25.5 J11.13 J26.1 J27.1 J37.6 LED2.1 OP1.5 R86.1 TP7.1 | length 7287.1
  Top Layer w6: v1(898.41,4561.38) LED2.1@977.67,4561.38
  Top Layer w20: v1(567.41,5361.38) 570.8,5357.99 D8.2@642.41,5357.99 ; v1(637.41,5100.38) 637.61,5100.17 IC25.5@637.61,5031.07 ; v1(637.61,4768.17) IC25.4@637.61,4822.09 ; D7.2@667.41,4657.99 744.8,4657.99 v1(747.41,4655.38) ; C79.1@947.41,4084.18 v1(947.41,4139.38) ; C74.2@1161.5,4396.38 v1@1161.5,4459.47
  Top Layer w50: v2(834.41,3720.37) 838.01,3716.78 R86.1@838.01,3628.78
  L3 w40: OP1.5@1062.41,4105.38 1151.87,4105.38 1175.3,4128.81 1175.3,4249.27 1263.03,4337 1494.98,4337 1662.41,4169.58 1662.41,3367.49 1972.41,3057.49 1972.41,2631.13 2142.41,2461.13 2142.41,2236.38 2255.58,2123.2 2753.13,2123.2 2811.33,2181.4 3591.3,2181.4 3784.41,1988.29 v2(3784.41,1561.38)
  L5 w20: v2@3780.4,1565.38 v2(3784.41,1561.38)
  Bottom Layer w50: J37.6@247.41,3466.38 247.41,3553.38 417.41,3723.38 v2(663.41,3723.38)
  Bottom Layer w60: J11.13@3606.41,700.38 3606.41,796.38 3801.4,991.37 3801.4,1544.39 v2(3784.41,1561.38)
  other v1: 1163.41,4461.38
IC6-A2: IC6.A2 P1.35 pad.1@4734.41,4880.37 R84.1 | length 2321.2
  Top Layer w6: pad.1@4734.41,4880.37 4791.41,4937.38 4791.41,5058.38 ; v1(4828.4,5150.38) 4828.4,5141.38 4791.41,5104.37 4791.41,5058.38 ; R84.1@4845.41,5058.92 4791.95,5058.92 4791.41,5058.38 ; v1(5079.41,5149.38) 5079.41,5270.38 5218.41,5409.38 5218.41,5472.37 5250.41,5504.37 5345.41,5504.37 P1.35@5392.41,5551.38
  Top Layer w10: IC6.A2@3900.4,4284.98 3917.8,4302.38 v1(3918.41,4302.38)
  Bottom Layer w6: v1(3918.41,4302.38) 3944.41,4302.38 3981.41,4339.38 3981.41,4405.38 4019.41,4443.38 4103.41,4443.38 4187.41,4527.38 4299.41,4527.38 4347.41,4575.38 4417.41,4575.38 4722.41,4880.37 pad.1@4734.41,4880.37 ; v1(4828.4,5150.38) 5078.41,5150.38 v1(5079.41,5149.38)
IC6-A5: IC6.A5 pad.1@4734.41,4350.38 | length 924.9
  Top Layer w6: IC6.A5@3900.4,4166.88 3903.9,4166.88 v1(3923.41,4186.38)
  L3 w6: v1(3923.41,4186.38) 4207.41,4186.38 4241.01,4219.98 4462.01,4219.98 4610.41,4368.37 4716.4,4368.37 pad.1@4734.41,4350.38
IC6-A9: IC6.A9 J2.2 pad.1@4734.41,3642.38 | length 5425.4
  Top Layer w6: IC6.A9@3900.4,4009.38 3917.41,4009.38 4002.41,3924.38 4363.41,3924.38 4443.41,4004.38 4639.41,4004.38 4673.41,3970.38 4673.41,3703.38 pad.1@4734.41,3642.38 4790.41,3586.38 4790.41,3488.38 4877.41,3401.38 4877.41,3274.38 5100.4,3051.38 5100.4,2493.38 5033.41,2426.38 4425.41,2426.38 4328.41,2329.38 4328.41,1501.38 4608.41,1221.38 4944.41,1221.38 5169.41,996.38 J2.2@5367.41,996.38
IC6-A10: IC6.A10 IC9.4 pad.1@4734.41,3525.38 | length 4086
  Top Layer w6: IC6.A10@3900.4,3969.98 3920.8,3969.98 4055.41,3835.38 4254.41,3835.38 v1(4332.4,3757.38) ; IC9.4@4567.41,1116.38 4567.41,1174.38 v1(4570.41,1177.38)
  Bottom Layer w6: v1(4332.4,3757.38) 4411.41,3678.38 4411.41,3390.38 4445.41,3356.38 4651.41,3356.38 4700.4,3405.38 4700.4,3503.38 4722.41,3525.38 4813.41,3525.38 4902.41,3436.38 4902.41,3155.38 4946.41,3111.38 4946.41,2752.38 4751.41,2557.38 4751.41,2432.38 4704.41,2385.38 4704.41,1399.38 4568.41,1263.38 4568.41,1179.38 v1(4570.41,1177.38)
IC6-A11: IC6.A11 J10.2 pad.1@4734.41,3347.38 | length 2101.2
  Top Layer w6: IC6.A11@3900.4,3930.68 3910.1,3930.68 4153.41,3687.38 4274.41,3687.38 4342.41,3619.38 4342.41,3520.38 4486.41,3376.38 4658.41,3376.38 4687.41,3347.38 pad.1@4734.41,3347.38 4734.41,3329.38 4967.41,3096.38 4967.41,2660.38 4904.41,2597.38 J10.2@4904.41,2502.38
IC6-A13: IC6.A13 IC9.1 pad.1@4731.41,3110.38 | length 3643.8
  Top Layer w6: IC6.A13@3900.4,3851.87 3919.9,3851.87 4115.41,3656.38 4250.41,3656.38 4272.41,3634.38 4272.41,3510.38 4454.41,3328.38 4581.41,3328.38 4685.41,3224.38 4685.41,3156.38 pad.1@4731.41,3110.38 ; IC9.1@4717.41,1116.38 4717.41,1175.38 v1(4720.41,1178.38)
  L3 w6: v1(4720.41,1178.38) 4720.41,1310.38 4946.41,1536.38 4946.41,2180.38 5137.71,2371.68 5137.71,2801.08 4851.41,3087.38 v3(4812.4,3087.38) 4754.41,3087.38 pad.1@4731.41,3110.38
IC6-A14: IC6.A14 pad.1@4731.41,2993.38 | length 1388.8
  Top Layer w6: IC6.A14@3900.4,3812.58 3918.21,3812.58 4044.4,3686.38 4044.4,3571.38 4073.41,3542.38 4176.41,3542.38 4194.41,3524.38 4194.41,3500.38 4281.41,3413.38 4281.41,3179.38 4467.41,2993.38 pad.1@4731.41,2993.38
IC6-B1: IC6.B1 P1.30 pad.1@4733.41,5175.38 | length 2057.6
  Top Layer w6: IC6.B1@3861,4324.38 3861,4324.98 3952.41,4416.37 4071.41,4416.37 4118.41,4463.38 4148.4,4463.38 4191.41,4506.38 4191.41,4559.38 4210.41,4578.38 4210.41,4669.38 v1(4203.41,4676.38)
  L3 w6: v1(4203.41,4676.38) 4203.41,4708.38 4304.41,4809.38 4531.41,4809.38 4654.41,4932.38 4654.41,5143.38 4686.41,5175.38 pad.1@4733.41,5175.38
  Bottom Layer w6: pad.1@4733.41,5175.38 5218.41,5175.38 5292.41,5249.38 P1.30@5292.41,5251.38
IC6-B2: IC6.B2 J42.1 pad.1@4734.41,4997.38 | length 5449.2
  Top Layer w6: IC6.B2@3861,4284.98 3881.6,4264.37 3933.41,4264.37 3957.41,4288.37 v1(3957.41,4363.38)
  Bottom Layer w6: J42.1@2929.41,5975.38 2918.41,5986.38 2918.41,6038.38 3287.41,6407.38 4583.41,6407.38 4749.41,6241.38 4749.41,5874.38 4972.4,5651.38 4972.4,5253.38 4947.02,5228 4784,5228 4767.28,5211.28 4699.31,5211.28 4684.4,5196.38 4684.4,5113.38 4709.41,5088.37 4757.41,5088.37 4768.41,5077.38 4768.41,5031.38 pad.1@4734.41,4997.38 ; v1(3957.41,4363.38) 3953.41,4367.38 3953.41,4409.38 4130.41,4586.38 4186.41,4586.38 4307.41,4707.38 4441.41,4707.38 4731.41,4997.38 pad.1@4734.41,4997.38 ; v3(5075.41,4857.38) 5036.4,4896.37 4835.41,4896.37 pad.1@4734.41,4997.38
IC6-B3: IC6.B3 pad.1@4734.41,4822.38 | length 1137.3
  Top Layer w6: IC6.B3@3861,4245.58 3881.2,4225.38 3959.41,4225.38 3977.41,4243.38 4169.41,4243.38 v1(4284.4,4358.38)
  Bottom Layer w6: v1(4284.4,4358.38) 4284.4,4372.38 pad.1@4734.41,4822.38
IC6-B5: IC6.B5 P1.32 pad.1@4734.41,4408.37 | length 2354.2
  Top Layer w6: v1(3841.41,4186.38) 3860.91,4166.88 IC6.B5@3861,4166.88 ; v1(5077.41,4496.37) 5079.41,4496.37 5111.41,4528.37 5111.41,5180.38 5282.41,5351.38 5292.41,5351.38 P1.32@5281.41,5351.38
  L3 w6: v1(3841.41,4186.38) 3849.41,4194.38 3849.6,4194.38 3887.6,4232.37 4215.41,4232.37 4228.4,4245.38 4412.4,4245.38 4575.41,4408.37 pad.1@4734.41,4408.37
  Bottom Layer w6: pad.1@4734.41,4408.37 4780.4,4408.37 4868.4,4496.37 v1(5077.41,4496.37)
IC6-B6: IC6.B6 pad.1@4734.41,4172.38 | length 905.3
  Top Layer w6: IC6.B6@3861,4127.48 3879.9,4146.38 v1(3988.4,4146.38)
  Bottom Layer w6: v1(3988.4,4146.38) 4030.41,4188.38 4712.41,4188.38 4728.41,4172.38 pad.1@4734.41,4172.38
IC6-B10: IC6.B10 J10.1 pad.1@4734.41,3407.38 | length 2427.6
  Top Layer w6: IC6.B10@3861,3969.98 3871.81,3969.98 3891.41,3950.38 3915.41,3950.38 4054.41,3811.38 4243.41,3811.38 v1(4277.41,3777.38) ; pad.1@4734.41,3407.38 4828.4,3407.38 4853.41,3382.38 4853.41,3254.38 5004.4,3103.38 J10.1@5004.4,2502.38
  Bottom Layer w6: v1(4277.41,3777.38) 4277.41,3776.37 4379.41,3674.38 4379.41,3374.38 4434.41,3319.38 4646.41,3319.38 pad.1@4734.41,3407.38
IC6-B14: IC6.B14 IC9.7 J10.6 pad.1@4731.41,2819.38 | length 4165.8
  Top Layer w6: IC6.B14@3861,3812.58 3882.8,3834.38 3917.41,3834.38 4065.41,3686.38 4065.41,3600.38 4103.41,3562.38 4197.41,3562.38 4207.41,3552.38 4207.41,3512.38 4418.41,3301.38 4528.41,3301.38 4573.41,3256.38 v1(4573.41,3224.38) ; v1(4415.41,1177.38) 4417.41,1175.38 IC9.7@4417.41,1116.38 ; J10.6@4504.41,2502.38 4504.41,2592.38 pad.1@4731.41,2819.38
  L3 w6: v1(4415.41,1177.38) 4466.41,1228.38 4512.41,1228.38 4888.41,1604.38 4888.41,2194.38 5083.41,2389.38 5083.41,2575.38 4839.41,2819.38 pad.1@4731.41,2819.38
  Bottom Layer w6: v1(4573.41,3224.38) 4573.41,2975.38 4729.41,2819.38 pad.1@4731.41,2819.38
IC6-B15: IC6.B15 J10.8 pad.1@4553.41,2821.38 | length 1749.5
  Top Layer w6: IC6.B15@3861,3773.17 3879.81,3754.38 3910.41,3754.38 3927.41,3737.38 3927.41,3697.38 3991.41,3633.38 3991.41,3509.38 4027.41,3473.38 4107.41,3473.38 4162.41,3418.38 4162.41,3177.38 4196.4,3143.38 4237.41,3143.38 4553.41,2827.38 pad.1@4553.41,2821.38
  L3 w6: J10.8@4304.41,2502.38 4304.41,2540.38 4553.41,2789.38 pad.1@4553.41,2821.38
IC6-B16: IC6.B16 J10.9 pad.1@4435.41,2822.38 | length 1688
  Top Layer w6: IC6.B16@3861,3733.78 3861,3694.78 3875.41,3680.38 3915.41,3680.38 3955.41,3640.38 3955.41,3180.38 4055.41,3080.38 4225.41,3080.38 4310.41,2995.38 4310.41,2974.38 4435.41,2849.38 pad.1@4435.41,2822.38 4435.41,2733.38 J10.9@4204.4,2502.38
IC6-C3: IC6.C3 pad.1@4734.41,4940.38 | length 1530.9
  Top Layer w6: IC6.C3@3821.6,4245.58 3821.6,4245.17 v1(3841.41,4225.38) ; v1(4599.41,4519.38) 4599.41,4641.38 4534.41,4706.38 4534.41,4861.38 4609.41,4936.37 4730.41,4936.37 pad.1@4734.41,4940.38
  Bottom Layer w6: v1(3841.41,4225.38) 3921.41,4225.38 3940.4,4244.38 4163.41,4244.38 4186.41,4267.38 4383.41,4267.38 4599.41,4483.38 v1(4599.41,4519.38)
IC6-C5: IC6.C5 P1.14 pad.1@4734.41,4468.38 | length 1768.2
  Top Layer w6: IC6.C5@3821.6,4166.88 3821.91,4166.88 v1(3841.41,4147.38)
  L3 w6: v1(3841.41,4147.38) 3948.4,4147.38 3969.41,4126.38 4037.41,4126.38 4074.41,4163.38 4219.41,4163.38 4251.41,4195.38 4543.41,4195.38 4621.41,4273.38 v1(4621.41,4318.38)
  Bottom Layer w6: v1(4621.41,4318.38) 4621.41,4412.38 4677.41,4468.38 4795.41,4468.38 4856.41,4529.38 5213.41,4529.38 5291.41,4451.38 P1.14@5292.4,4451.38
IC6-C10: IC6.C10 J10.4 pad.1@4731.41,3228.38 | length 2189.9
  Top Layer w6: IC6.C10@3821.6,3969.98 3841.2,3950.38 3867.41,3950.38 3879.41,3938.38 3879.41,3919.38 3885.41,3913.38 3908.4,3913.38 4152.41,3669.38 4263.41,3669.38 4313.41,3619.38 4313.41,3500.38 4464.41,3349.38 4610.41,3349.38 pad.1@4731.41,3228.38 4918.41,3041.38 4918.41,2768.38 4704.41,2554.38 J10.4@4704.41,2502.38
IC6-C11: IC6.C11 J10.5 pad.1@4731.41,3170.38 | length 2220.5
  Top Layer w6: J10.5@4604.4,2502.38 4600.41,2506.38 4600.41,2542.38 4775.41,2717.38 4775.41,3126.38 pad.1@4731.41,3170.38
  Top Layer w10: v1(3802.41,3950.38) 3821.6,3931.18 IC6.C11@3821.6,3930.68
  Bottom Layer w6: v1(3802.41,3950.38) 4016.41,3950.38 4236.4,3730.38 4277.41,3730.38 4362.41,3645.38 4362.41,3337.38 4411.41,3288.38 4602.41,3288.38 4720.41,3170.38 pad.1@4731.41,3170.38
IC6-C13: IC6.C13 pad.1@4671.41,2821.38 | length 1704.3
  Top Layer w6: IC6.C13@3821.6,3851.87 3841.41,3832.08 3841.41,3804.38 3852.4,3793.38 3918.41,3793.38 3958.41,3753.38 3958.41,3719.38 4023.41,3654.38 4023.41,3563.38 v1(4047.41,3539.38)
  L3 w6: v1(4047.41,3539.38) 4051.41,3535.38 4051.41,3395.38 4091.41,3355.38 4357.41,3355.38 4461.41,3251.38 4489.41,3251.38 4572.4,3168.38 4572.4,3031.38 4671.41,2932.38 pad.1@4671.41,2821.38 4671.41,2761.38 v3(4707.41,2725.38)
IC6-C15: IC6.C15 J10.10 pad.1@4375.41,2822.38 | length 1748.4
  Top Layer w6: IC6.C15@3821.6,3773.17 3800.41,3751.98 3800.41,3684.38 3857.41,3627.38 3889.41,3627.38 3921.41,3595.38 3921.41,3129.38 4127.41,2923.38 4240.41,2923.38 v1(4245.41,2928.38)
  Bottom Layer w6: J10.10@4104.41,2502.38 4104.41,2515.38 4375.41,2786.38 4375.41,2838.38 4285.41,2928.38 v1(4245.41,2928.38)
IC6-C16: IC6.C16 J10.12 pad.1@4257.41,2822.38 | length 1757.5
  Top Layer w6: IC6.C16@3821.6,3733.78 3821.6,3698.18 3868.4,3651.38 3920.41,3651.38 3941.41,3630.38 3941.41,3157.38 4078.41,3020.38 4213.41,3020.38 4277.41,2956.38 4277.41,2903.38 4263.41,2889.38 4263.41,2828.38 pad.1@4257.41,2822.38 4257.41,2812.38 4070.41,2625.38 3945.41,2625.38 3904.41,2584.38 J10.12@3904.41,2502.38
IC6-D3: IC6.D3 J42.2 pad.1@4735.41,5116.38 | length 5762.9
  Top Layer w6: IC6.D3@3782.3,4245.58 3803.41,4266.68 v1(3803.41,4303.38)
  L3 w6: v1(3803.41,4303.38) 3803.41,4318.38 3967.41,4482.38 3967.41,4545.38 4029.41,4607.38 4475.41,4607.38 4679.41,4811.38 4679.41,5060.38 pad.1@4735.41,5116.38
  Bottom Layer w6: J42.2@2829.41,5975.38 2829.41,6055.38 3226.41,6452.38 4574.41,6452.38 4780.4,6246.38 4780.4,5913.38 4995.41,5698.38 4995.41,5240.37 4954.53,5199.5 4710.53,5199.5 4697.8,5186.77 4697.8,5132.99 4714.41,5116.38 pad.1@4735.41,5116.38 4970.41,5116.38 5074.41,5012.38 v3(5074.41,4952.37)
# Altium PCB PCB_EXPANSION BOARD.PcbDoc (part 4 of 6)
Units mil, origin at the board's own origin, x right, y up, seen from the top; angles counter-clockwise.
Board outline 5512.34 x 7953.29 mil, 6 copper layers (Top Layer, L2, L3, L4, L5, Bottom Layer); 420 components, 365 nets, 1860 pads, 895 vias.
Unrouted connection lines stored in the file: 9.

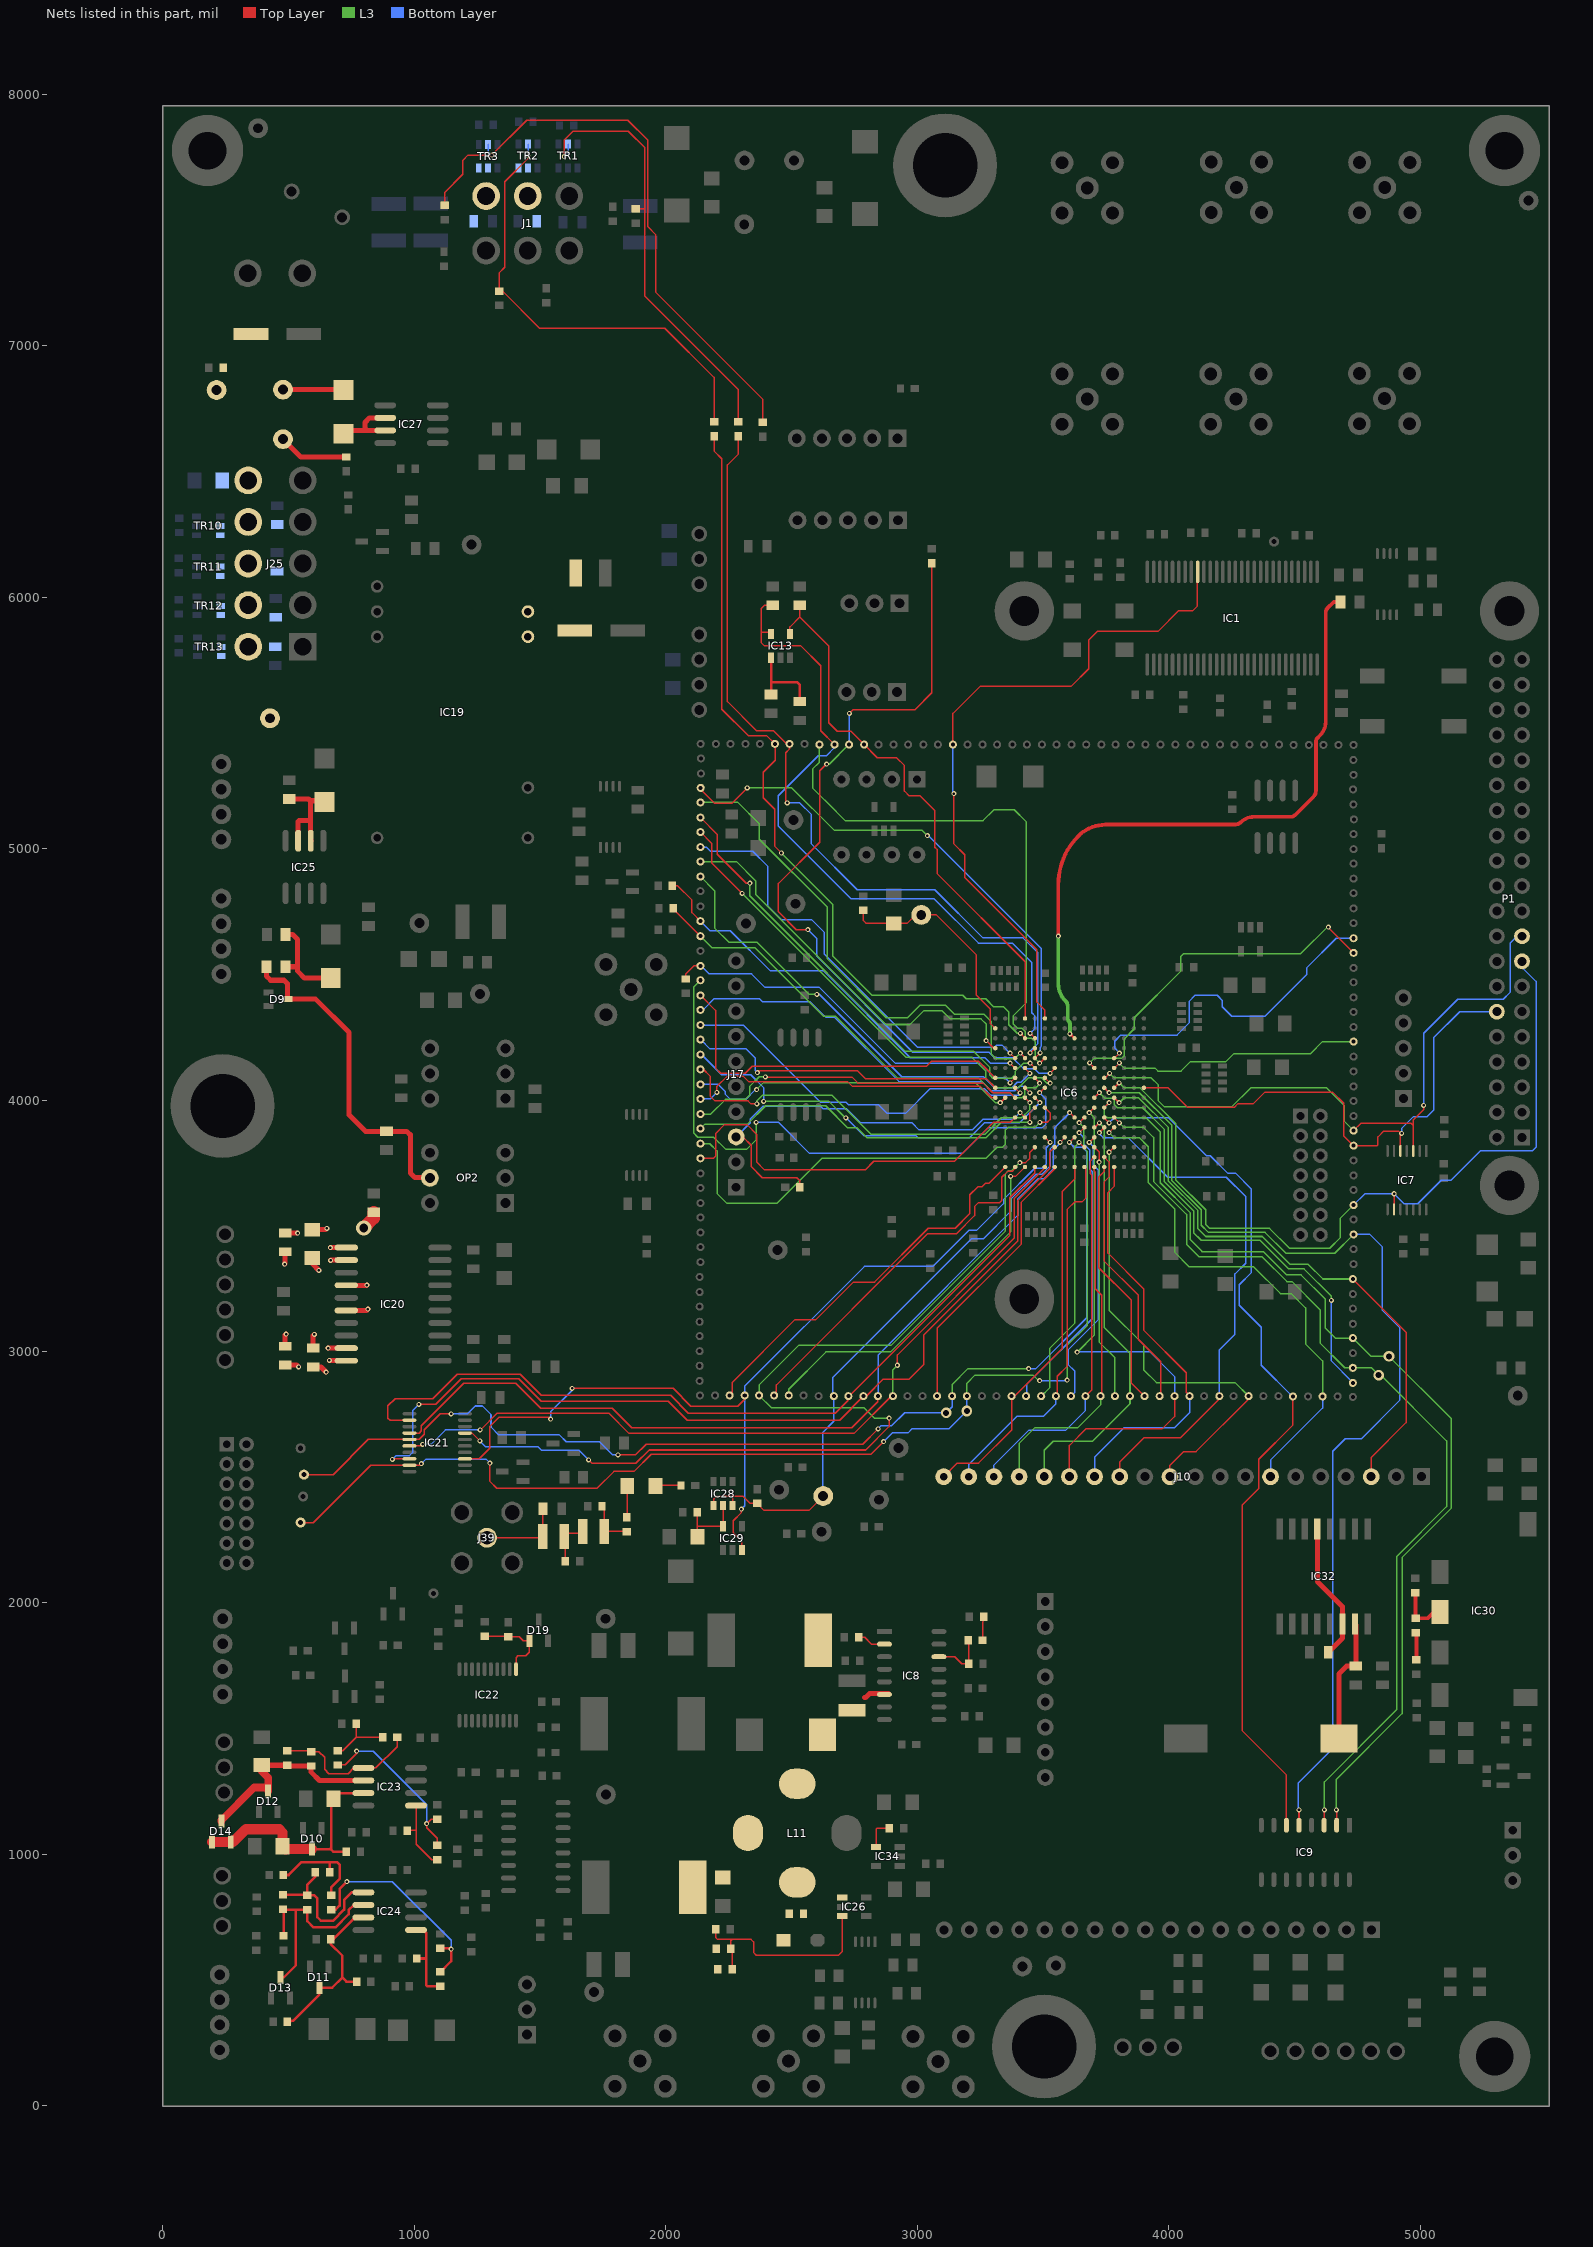
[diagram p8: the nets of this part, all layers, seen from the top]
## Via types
v1: diameter 20, hole 10, Top Layer to Bottom Layer, tented both sides, 808 vias
v2: diameter 60, hole 35, Top Layer to Bottom Layer, 47 vias
v3: diameter 42, hole 24, Top Layer to Bottom Layer, 32 vias
v4: diameter 125.98/125.98/125.98/125.98/125.98/125.98 (per signal layer), hole 125.98, Top Layer to Bottom Layer, 6 vias
v5: diameter 51.18, hole 51.18, Top Layer to Bottom Layer, 2 vias

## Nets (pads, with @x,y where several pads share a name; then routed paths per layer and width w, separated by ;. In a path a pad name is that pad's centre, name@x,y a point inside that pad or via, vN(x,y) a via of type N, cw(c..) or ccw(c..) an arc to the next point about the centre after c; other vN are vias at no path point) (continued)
IC6-D5: IC6.D5 pad.1@4734.41,4643.38 | length 1353.9
  Top Layer w6: IC6.D5@3782.3,4166.88 3783.9,4166.88 v1(3803.41,4186.38)
  Bottom Layer w6: v1(3803.41,4186.38) 3803.41,4187.38 3784.41,4206.38 3784.41,4234.18 3808.61,4258.38 4032.41,4258.38 4080.41,4306.38 4080.41,4392.37 4104.41,4416.37 4192.41,4416.37 4212.4,4396.38 4212.4,4371.38 4250.41,4333.38 4382.41,4333.38 4547.41,4498.38 4547.41,4525.38 4665.41,4643.38 pad.1@4734.41,4643.38
IC6-D6: IC6.D6 pad.1@4734.41,4232.37 | length 1023.1
  Top Layer w6: IC6.D6@3782.3,4127.48 3783.51,4127.48 v1(3803.41,4147.38)
  L3 w6: v1(3803.41,4147.38) 3803.41,4145.68 3821.71,4127.38 3944.41,4127.38 3956.4,4115.38 4048.41,4115.38 4084.4,4151.38 4225.41,4151.38 4257.41,4183.38 4562.41,4183.38 4611.41,4232.37 pad.1@4734.41,4232.37
IC6-D9: IC6.D9 J10.3 pad.1@4731.41,3288.38 | length 2362.7
  Top Layer w6: IC6.D9@3782.3,4009.38 3782.41,4009.38 v1(3802.41,3989.38) ; pad.1@4731.41,3288.38 4943.41,3076.38 4943.41,2717.38 4804.4,2578.38 J10.3@4804.4,2502.38
  L3 w6: v1(3802.41,3989.38) 3822.41,4009.38 3879.41,4009.38 3998.41,3890.38 3998.41,3677.38 4115.41,3560.38 4115.41,3488.38 4146.41,3457.38 4371.41,3457.38 4481.41,3347.38 4553.41,3347.38 4612.4,3288.38 pad.1@4731.41,3288.38
IC6-D11: IC6.D11 IC9.3 pad.1@4731.41,2935.38 | length 3835.4
  Top Layer w6: IC6.D11@3782.3,3930.68 3782.3,3930.48 3782.1,3930.68 v1(3803.41,3909.38) ; IC9.3@4617.41,1116.38 4617.41,1176.38 v1(4618.41,1177.38)
  L3 w6: v1(3803.41,3909.38) 3803.51,3909.38 3821.5,3891.38 3899.41,3891.38 3939.41,3851.38 3939.41,3676.38 4070.41,3545.38 4070.41,3426.38 4120.41,3376.38 4371.41,3376.38 4469.41,3278.38 4489.41,3278.38 4601.41,3166.38 4601.41,3033.38 4699.41,2935.38 pad.1@4731.41,2935.38 4805.41,2935.38 v3(4834.41,2906.38) 4842.41,2906.38 5104.41,2644.37 5104.41,2383.38 4906.41,2185.38 4906.41,1576.38 4618.41,1288.38 v1(4618.41,1177.38)
IC6-D12: IC6.D12 J10.7 pad.1@4611.41,2821.38 | length 2068.3
  Top Layer w6: v1(3762.41,3870.38) 3782.3,3890.28 IC6.D12@3782.3,3891.28
  L3 w6: v1(3762.41,3870.38) 3782.11,3850.68 3882.11,3850.68 3918.21,3814.58 3918.21,3671.58 4022.41,3567.38 4022.41,3395.38 4080.41,3337.38 4336.41,3337.38 4443.41,3230.38 4486.41,3230.38 4543.41,3173.38 4543.41,3030.38 4611.41,2962.38 pad.1@4611.41,2821.38
  Bottom Layer w6: J10.7@4404.4,2502.38 4404.4,2568.38 4611.41,2775.38 pad.1@4611.41,2821.38
IC6-D14: IC6.D14 J10.11 pad.1@4317.41,2822.38 | length 1890
  Top Layer w6: v1(3762.41,3792.37) 3782.3,3812.28 IC6.D14@3782.3,3812.58 ; J10.11@4004.4,2502.38 4004.4,2547.38 4059.41,2602.38 4108.4,2602.38 4317.41,2811.38 pad.1@4317.41,2822.38
  L3 w6: v1(3762.41,3792.37) 3762.41,3164.38 3899.41,3027.38 3899.41,2927.38 3950.41,2876.38 4263.41,2876.38 pad.1@4317.41,2822.38
IC6-D16: IC6.D16 J10.14 pad.1@4082.41,2822.38 | length 1650.6
  Top Layer w6: IC6.D16@3782.3,3733.78 3782.3,3656.28 3757.41,3631.38 3757.41,3391.38 3899.41,3249.38 3899.41,3085.38 4069.41,2915.38 4069.41,2838.38 4082.41,2825.38 pad.1@4082.41,2822.38
  Bottom Layer w6: J10.14@3704.41,2502.38 3704.41,2579.38 3822.41,2697.38 4023.41,2697.38 4082.41,2756.38 pad.1@4082.41,2822.38
IC6-E8: IC6.E8 IC9.5 pad.1@4734.41,3465.38 | length 4127.6
  Top Layer w6: IC6.E8@3742.91,4048.78 3743.01,4048.78 v1(3762.41,4029.38) ; IC9.5@4517.41,1116.38 v1(4517.41,1177.38)
  L3 w6: v1(3762.41,4029.38) 3882.41,4029.38 4011.41,3900.38 4011.41,3680.38 4128.41,3563.38 4128.41,3502.38 4157.41,3473.38 4382.41,3473.38 4465.41,3390.38 4659.41,3390.38 pad.1@4734.41,3465.38
  Bottom Layer w6: v1(4517.41,1177.38) 4515.41,1179.38 4515.41,1285.38 4651.41,1421.38 4651.41,2603.38 4701.41,2653.38 4765.41,2653.38 4917.41,2805.38 4917.41,3095.38 4849.41,3163.38 4849.41,3415.38 4799.41,3465.38 pad.1@4734.41,3465.38
IC6-E10: IC6.E10 IC9.2 pad.1@4731.41,3053.38 | length 4020
  Top Layer w6: IC6.E10@3742.91,3969.98 3743.01,3969.98 v1(3762.41,3989.38) ; v1(4666.41,1177.38) 4667.41,1176.38 IC9.2@4667.41,1116.38
  L3 w6: v1(3762.41,3989.38) 3742.41,3969.38 3742.41,3941.78 3754.8,3929.38 3909.41,3929.38 3965.41,3873.38 3965.41,3671.38 4085.41,3551.38 4085.41,3444.38 4131.41,3398.38 4131.41,3397.38 4375.41,3397.38 4468.4,3304.38 4525.41,3304.38 4621.41,3208.38 4621.41,3093.38 4661.41,3053.38 pad.1@4731.41,3053.38 4804.41,2980.38 v3(4875.41,2980.38) 5123.41,2732.38 5123.41,2377.38 4927.41,2181.38 4927.41,1560.38 4666.41,1299.38 v1(4666.41,1177.38)
IC6-E11: IC6.E11 IC9.6 pad.1@4493.41,2821.38 | length 3516.2
  Top Layer w6: IC6.E11@3742.91,3930.68 3742.91,3928.88 v1(3762.41,3909.38) ; IC9.6@4467.41,1116.38 4467.41,1316.38 4292.4,1491.38 4292.4,2390.38 4357.41,2455.38 4357.41,2571.38 4493.41,2707.38 pad.1@4493.41,2821.38
  Bottom Layer w6: v1(3762.41,3909.38) 3782.41,3929.38 3998.41,3929.38 4149.41,3778.38 4164.4,3778.38 4233.41,3709.38 4264.41,3709.38 4328.41,3645.38 4328.41,3314.38 4279.41,3265.38 4279.41,3184.38 4367.41,3096.38 4367.41,2945.38 4491.41,2821.38 pad.1@4493.41,2821.38
IC6-E12: IC6.E12 J10.13 pad.1@4200.41,2822.38 | length 2125
  Top Layer w6: v1(3723.41,3870.38) 3742.91,3889.88 IC6.E12@3742.91,3891.28 ; J10.13@3804.4,2502.38 3804.4,2560.38 3900.4,2656.38 4045.41,2656.38 4200.41,2811.38 pad.1@4200.41,2822.38
  Bottom Layer w6: v1(3723.41,3870.38) 3723.41,3866.38 3740.31,3849.48 3839.31,3849.48 3995.41,3693.38 4228.4,3693.38 4305.41,3616.38 4305.41,3351.38 4262.41,3308.38 4262.41,3068.38 4200.41,3006.38 pad.1@4200.41,2822.38
IC6-E15: IC6.E15 pad.1@3963.41,2822.38 | length 1062
  Top Layer w6: IC6.E15@3742.91,3773.17 3762.41,3753.68 3762.41,3694.38 3742.41,3674.38 3742.41,3360.38 3878.41,3224.38 3878.41,3048.38 3967.41,2959.38 3967.41,2826.38 pad.1@3963.41,2822.38
IC6-E16: IC6.E16 pad.1@3903.41,2822.38 | length 995.7
  Top Layer w6: IC6.E16@3742.91,3733.78 3742.91,3715.87 3721.41,3694.38 3721.41,3333.38 3850.41,3204.38 3850.41,2875.38 pad.1@3903.41,2822.38
IC6-F6: IC6.F6 pad.1@4734.41,4585.38 | length 1449.8
  Top Layer w6: v1(3684.41,4147.38) 3703.51,4128.28 IC6.F6@3703.51,4127.48 ; v1(4634.41,4687.38) 4634.41,4685.38 pad.1@4734.41,4585.38
  L3 w6: v1(3684.41,4147.38) 3702.41,4165.38 3811.91,4165.38 3822.31,4175.78 3822.31,4243.29 3862.41,4283.39 3862.41,4325.94 ; 3862.41,4327.38 4046.41,4511.38 4046.41,4569.38 4058.41,4581.38 4523.41,4581.38 4634.41,4692.38 v1(4634.41,4687.38)
IC6-F9: IC6.F9 pad.1@4731.41,2875.38 | length 1849.3
  Top Layer w6: IC6.F9@3703.51,4009.38 3703.51,4009.48 v1(3723.41,4029.38)
  L3 w6: v1(3723.41,4029.38) 3745.21,4007.58 3775.2,4007.58 3782.41,4000.37 3782.41,3982.38 3795.41,3969.38 3896.41,3969.38 3982.41,3883.38 3982.41,3675.38 4098.41,3559.38 4098.41,3472.38 4128.41,3442.38 4362.41,3442.38 4476.4,3328.38 4537.41,3328.38 4646.41,3219.38 v1(4646.41,3203.38)
  Bottom Layer w6: v1(4646.41,3203.38) 4646.41,2962.38 4731.41,2877.38 pad.1@4731.41,2875.38
IC6-F10: IC6.F10 J10.15 pad.1@4022.41,2822.38 | length 2194.5
  Top Layer w6: J10.15@3604.41,2502.38 3604.41,2626.38 3671.41,2693.38 3974.41,2693.38 4022.41,2741.38 pad.1@4022.41,2822.38 ; v1(3683.41,3950.38) 3703.01,3969.98 IC6.F10@3703.51,3969.98
  L3 w6: v1(3635.41,2997.38) 3703.51,3065.48 3703.51,3930.48 3683.6,3950.38 v1(3683.41,3950.38)
  Bottom Layer w6: v1(3635.41,2997.38) 3636.41,2998.38 3924.4,2998.38 4022.41,2900.38 pad.1@4022.41,2822.38
IC6-F12: IC6.F12 J10.16 pad.1@3845.41,2822.38 | length 1717.6
  Top Layer w6: IC6.F12@3703.51,3891.28 3705.3,3891.28 v1(3723.41,3909.38)
  L3 w6: J10.16@3504.41,2502.38 3504.41,2607.38 3540.41,2643.38 3696.41,2643.38 3845.41,2792.38 pad.1@3845.41,2822.38 3845.41,2993.38 3742.91,3095.88 3742.91,3889.88 v1(3723.41,3909.38)
IC6-F13: IC6.F13 pad.1@3610.41,2822.38 | length 1118.8
  Top Layer w6: v1(3683.41,3831.38) 3703.51,3851.48 IC6.F13@3703.51,3851.87
  Bottom Layer w6: pad.1@3610.41,2822.38 3625.41,2837.38 3625.41,2922.38 3599.2,2948.58 3599.2,3006.17 3718.41,3125.38 3718.41,3722.98 3699.01,3742.38 3699.01,3815.78 v1(3683.41,3831.38)
IC6-F14: IC6.F14 pad.1@3785.41,2822.38 | length 1024.4
  Top Layer w6: IC6.F14@3703.51,3812.58 3722.71,3793.38 3722.71,3753.68 v1(3722.41,3753.38)
  L3 w6: v1(3722.41,3753.38) 3722.41,3038.38 3785.41,2975.38 pad.1@3785.41,2822.38
IC6-F15: IC6.F15 J10.18 pad.1@3668.41,2822.38 | length 1528
  Top Layer w6: pad.1@3668.41,2822.38 3693.41,2847.38 3693.41,3701.38 3686.41,3708.38 3686.41,3756.08 IC6.F15@3703.51,3773.17
  Bottom Layer w6: J10.18@3304.41,2502.38 3304.41,2548.38 3443.41,2687.38 3590.41,2687.38 3668.41,2765.38 pad.1@3668.41,2822.38
IC6-F16: IC6.F16 J10.17 pad.1@3728.41,2822.38 | length 1480.2
  Top Layer w6: IC6.F16@3703.51,3733.78 3703.51,3717.28 3707.41,3713.38 3707.41,3249.38 3733.41,3223.38 3733.41,2827.38 pad.1@3728.41,2822.38
  L3 w6: J10.17@3404.41,2502.38 3404.41,2634.38 3467.41,2697.38 3638.41,2697.38 3728.41,2787.38 pad.1@3728.41,2822.38
IC6-G11: IC6.G11 IC21.9 pad.1@547.41,2320.38 pad.1@3196.41,2822.38 | length 4611.9
  Top Layer w5: pad.1@547.41,2320.38 548.41,2319.38 597.41,2319.38 825.84,2547.81 IC21.9@980.17,2547.81
  Top Layer w6: IC21.9@980.17,2547.81 1020.84,2547.81 v1(1027.41,2554.38) ; v1(1300.41,2556.38) 1300.41,2483.38 1327.41,2456.38 1658.41,2456.38 ; 1651.41,2456.38 1658.41,2456.38 ; v1(2865.41,2641.38) 2815.41,2591.38 1941.41,2591.38 1873.41,2523.38 1793.41,2523.38 1726.41,2456.38 1658.41,2456.38 ; v1(3643.41,3910.38) 3663.71,3930.68 IC6.G11@3664.2,3930.68
  L3 w6: pad.1@3196.41,2822.38 3196.41,2873.38 3229.41,2906.38 3459.41,2906.38 3481.41,2884.38 v1(3486.41,2884.38) ; v1(3595.41,2886.38) 3595.41,3023.38 3676.01,3103.98 3676.01,3795.88 3662.21,3809.68 3662.21,3891.07 3643.41,3909.87 v1(3643.41,3910.38)
  Bottom Layer w6: v1(1027.41,2554.38) 1045.41,2572.38 1284.41,2572.38 v1(1300.41,2556.38) ; v1(2865.41,2641.38) 2900.41,2676.38 2962.41,2676.38 2979.41,2693.38 3126.41,2693.38 v3(3196.41,2763.38) pad.1@3196.41,2822.38 ; v1(3486.41,2884.38) 3593.41,2884.38 v1(3595.41,2886.38)
IC6-G12: IC6.G12 pad.1@3432.41,2822.38 | length 1208
  Top Layer w6: v1(3643.41,3870.38) 3664.2,3891.18 IC6.G12@3664.2,3891.28
  Bottom Layer w6: pad.1@3432.41,2822.38 3435.41,2825.38 3435.41,2870.38 3695.41,3130.38 3695.41,3715.38 3686.31,3724.48 3686.31,3800.47 3662.41,3824.37 3662.41,3850.38 3643.41,3869.38 v1(3643.41,3870.38)
IC6-G14: IC6.G14 pad.1@3492.41,2822.38 | length 1100.1
  Top Layer w6: v1(3643.41,3831.38) 3662.21,3812.58 IC6.G14@3664.2,3812.58
  L3 w6: pad.1@3492.41,2822.38 3525.41,2855.38 3525.41,3012.38 3626.41,3113.38 3626.41,3814.38 v1(3643.41,3831.38)
IC6-G16: IC6.G16 J10.19 pad.1@3550.41,2822.38 | length 1505.5
  Top Layer w6: pad.1@3550.41,2822.38 3556.41,2828.38 3556.41,2901.38 3595.41,2940.38 3595.41,3564.38 3627.41,3596.38 3656.41,3596.38 3670.41,3610.38 3670.41,3727.58 IC6.G16@3664.2,3733.78
  Bottom Layer w6: J10.19@3204.41,2502.38 3204.41,2550.38 3397.41,2743.38 3502.41,2743.38 3550.41,2791.38 pad.1@3550.41,2822.38
IC6-H3: IC6.H3 R14.1 | length 2663.7
  Top Layer w10: v1(3606.41,4263.38) 3624.2,4245.58 IC6.H3@3624.8,4245.58
  Top Layer w15: v1(3560.41,4651.38) 3560.41,4857.24 cw(c3833.54,4857.24) 3640.41,5050.37 cw(c3746.64,4944.14) 3746.63,5094.38 ; 3746.63,5094.38 3747.63,5095.38 4265.75,5095.38 4266.75,5096.37 ccw(c4266.75,5122.1) 4284.94,5103.91 4285.41,5104.37 cw(c4338.52,5051.27) 4338.52,5126.38 4482.68,5126.38 ccw(c4482.68,5157.1) 4504.41,5135.38 4574.4,5205.38 ccw(c4549.53,5230.25) 4584.71,5230.25 4584.71,5400.38 4584.9,5400.58 4584.9,5425.97 cw(c4603.73,5425.97) 4590.42,5439.29 4601.71,5450.58 ccw(c4549.32,5502.97) 4623.41,5502.97 4623.41,5504.92 4623.41,5937.38 cw(c4649.96,5937.38) 4631.19,5956.16 4655.41,5980.38 4682.74,5980.38 ccw(c4682.74,5980.75) R14.1@4683,5980.49
  L3 w15: v1(3560.41,4651.38) 3560.41,4461.98 ccw(c3656.01,4461.98) 3588.4,4394.38 3590.34,4392.45 cw(c3573.26,4375.38) 3597.4,4375.38 3597.41,4325.87 ccw(c3617.89,4325.87) 3603.4,4311.38 cw(c3596.16,4304.14) 3606.41,4304.14 v1(3606.41,4263.38) v1@3605.41,4264.37
IC6-H13: IC6.H13 IC21.5 pad.1@560.41,2510.38 pad.1@3138.41,2822.38 | length 4397.8
  Top Layer w5: pad.1@560.41,2510.38 676.41,2510.38 816.2,2650.17 IC21.5@980.17,2650.17 1018.2,2650.17 1038.41,2670.38 1038.41,2688.38 1102.41,2752.38 v1(1145.41,2752.38)
  Top Layer w6: v1(1809.41,2589.38) 1879.41,2589.38 1921.41,2631.38 2782.41,2631.38 v1(2843.41,2692.38) ; v1(3604.41,3831.38) 3624.8,3851.78 IC6.H13@3624.8,3851.87
  L3 w6: pad.1@3138.41,2822.38 3138.41,2869.38 3201.41,2932.38 v1(3442.41,2932.38)
  Bottom Layer w6: v1(1145.41,2752.38) 1210.41,2752.38 1241.41,2783.38 1270.41,2783.38 1304.41,2749.38 1304.41,2699.38 1335.41,2668.38 1576.41,2668.38 1603.41,2641.38 1735.41,2641.38 1787.41,2589.38 v1(1809.41,2589.38) ; v1(2843.41,2692.38) 2856.41,2705.38 2898.41,2705.38 2949.41,2756.38 v3(3114.41,2756.38) 3138.41,2780.38 pad.1@3138.41,2822.38 ; v1(3442.41,2932.38) 3471.13,2932.38 3673.41,3134.65 3673.41,3795.37 3656.41,3812.38 3623.41,3812.38 v1(3604.41,3831.38)
IC6-H16: IC6.H16 J10.20 pad.1@3374.41,2822.38 | length 1504.6
  Top Layer w6: J10.20@3104.41,2502.38 3158.41,2556.38 3243.41,2556.38 3375.41,2688.38 3375.41,2821.38 pad.1@3374.41,2822.38 3386.41,2822.38 3576.41,3012.38 3576.41,3636.38 3624.8,3684.78 IC6.H16@3624.8,3733.78
IC6-K6: IC6.K6 pad.1@2728.41,5413.38 R110.2 | length 3207.6
  Top Layer w6: v1(2564.41,4677.38) 2518.41,4677.38 2447.41,4748.38 2447.41,4861.38 2611.41,5025.38 2611.41,5309.38 2637.41,5335.38 v1(2639.41,5335.38) ; v1(2729.41,5537.38) 2744.41,5552.37 2990.41,5552.37 ; 2990.41,5551.38 2990.41,5552.37 ; R110.2@3057.41,6134.83 3057.41,5619.38 2990.41,5552.37 ; v1(3527.41,4106.38) 3546.01,4124.98 IC6.K6@3546.01,4127.48
  L3 w6: v1(2639.41,5335.38) 2649.41,5335.38 2727.41,5413.38 pad.1@2728.41,5413.38
  Bottom Layer w6: v1(2564.41,4677.38) 2600.41,4641.38 2600.41,4571.38 2981.41,4190.38 3284.41,4190.38 3307.41,4167.38 3379.41,4167.38 3421.91,4124.88 3464.91,4124.88 3483.41,4106.38 v1(3527.41,4106.38) ; pad.1@2728.41,5413.38 2728.41,5536.37 v1(2729.41,5537.38)
IC6-K14: IC6.K14 IC21.8 pad.1@2785.41,2822.38 | length 3650.7
  Top Layer w5: v1(912.41,2571.38) 914.43,2573.4 IC21.8@980.17,2573.4 ; v1(1017.41,2789.38) 1084.41,2789.38 1186.41,2891.38 1415.41,2891.38 1504.41,2802.38 2009.41,2802.38 2084.41,2727.38 2690.41,2727.38 pad.1@2785.41,2822.38
  Top Layer w6: pad.1@2785.41,2822.38 2796.41,2822.38 2864.41,2890.38 2967.41,2890.38 3024.41,2947.38 3024.41,3064.38 3398.41,3438.38 3398.41,3599.38 3526.41,3727.38 3526.41,3792.98 IC6.K14@3546.01,3812.58
  Bottom Layer w6: v1(912.41,2571.38) 927.41,2586.38 980.41,2586.38 992.41,2598.38 992.41,2764.38 v1(1017.41,2789.38)
IC6-K16: IC6.K16 pad.1@3078.41,2822.38 | length 1105.1
  Top Layer w6: pad.1@3078.41,2822.38 3078.41,3092.38 3413.41,3427.38 3413.41,3594.38 3546.01,3726.98 IC6.K16@3546.01,3733.78
IC6-L5: IC6.L5 pad.1@2610.41,5413.38 | length 2200.9
  Top Layer w6: v1(3486.41,4146.38) 3490.21,4150.18 3490.21,4150.38 IC6.L5@3506.71,4166.88
  L3 w6: pad.1@2610.41,5413.38 2610.41,5343.38 2583.41,5316.38 2583.41,5241.38 2676.41,5148.38 2676.41,5147.38 2712.41,5111.38 3261.41,5111.38 3304.41,5154.38 3385.41,5154.38 3432.41,5107.38 3432.41,4386.38 3380.41,4334.38 3380.41,4303.38 3398.41,4285.38 3416.41,4285.38 3428.41,4273.38 3428.41,4252.38 3435.21,4245.58 3454.21,4245.58 3469.41,4230.38 3469.41,4163.38 v1(3486.41,4146.38)
IC6-L7: IC6.L7 pad.1@2137.41,5065.38 | length 1927.8
  Top Layer w6: pad.1@2137.41,5065.38 2182.41,5020.38 2182.41,4942.38 v1(2303.41,4821.38) ; IC6.L7@3506.71,4088.17 3527.41,4067.48 v1(3527.41,4067.38)
  L3 w6: v1(2303.41,4821.38) 2955.41,4169.38 3217.41,4169.38 3272.41,4114.38 3272.41,4086.18 3309.8,4048.78 3401.8,4048.78 3441.41,4088.37 3493.41,4088.37 3514.41,4067.38 v1(3527.41,4067.38)
IC6-L8: IC6.L8 pad.1@2137.41,4476.38 | length 2393.1
  Top Layer w6: v1(3486.41,4029.38) 3505.8,4048.78 IC6.L8@3506.71,4048.78
  L3 w6: pad.1@2137.41,4476.38 2110.41,4449.38 2110.41,3868.38 2126.41,3852.38 2189.41,3852.38 2238.41,3803.38 2320.41,3803.38 2358.41,3841.38 v1(2358.41,3911.38)
  Bottom Layer w6: v1(2358.41,3911.38) 2447.41,3911.38 2569.41,3789.38 3180.41,3789.38 3281.41,3890.38 3497.41,3890.38 3509.41,3902.38 3509.41,4005.38 3486.41,4028.38 v1(3486.41,4029.38)
IC6-L10: IC6.L10 pad.1@2137.41,3826.38 | length 1813.2
  Top Layer w6: v1(3487.41,3911.38) 3516.41,3911.38 3527.41,3922.38 3527.41,3949.28 IC6.L10@3506.71,3969.98
  L3 w6: pad.1@2137.41,3826.38 2174.41,3826.38 2203.41,3797.38 2203.41,3628.38 2241.41,3590.38 2442.49,3590.38 2620.49,3768.37 3272.41,3768.37 3315.41,3811.38 3337.41,3811.38 3348.41,3822.38 3348.41,3878.38 3361.3,3891.28 3467.3,3891.28 v1(3487.41,3911.38)
IC6-L13: IC6.L13 IC21.13 IC29.3 pad.1@2313.41,2825.38 | length 3742.5
  Top Layer w5: v1(1627.41,2853.38) 2028.41,2853.38 2099.41,2782.38 2285.41,2782.38 2313.41,2810.38 pad.1@2313.41,2825.38
  Top Layer w6: IC21.13@1200.64,2573.4 1257.43,2573.4 1299.41,2615.38 1299.41,2701.38 1336.41,2738.38 1534.41,2738.38 v1(1541.41,2731.38) ; v1(2300.41,2373.38) 2300.41,2360.38 2267.41,2327.38 2267.41,2279.38 2302.05,2244.73 IC29.3@2302.05,2210.58 ; IC6.L13@3506.71,3851.87 3506.91,3851.87 v1(3527.41,3831.38)
  Bottom Layer w6: v1(1541.41,2731.38) 1541.41,2760.38 1627.41,2846.38 v1(1627.41,2853.38) ; v1(2300.41,2373.38) 2313.41,2386.38 2313.41,2862.38 2789.41,3338.38 3061.41,3338.38 3204.41,3481.38 3235.41,3481.38 3342.41,3588.38 3342.41,3604.38 3466.41,3728.37 3495,3728.37 3512.11,3745.48 3512.11,3810.08 3527.41,3825.38 v1(3527.41,3831.38)
IC6-L16: IC6.L16 IC21.6 pad.1@2902.41,2822.38 | length 3233
  Top Layer w6: IC21.6@980.17,2624.58 1026.61,2624.58 v1(1032.41,2630.38) ; v1(1261.41,2688.38) 1262.41,2688.38 1329.41,2755.38 1772.41,2755.38 1853.41,2674.38 2748.41,2674.38 2896.41,2822.38 pad.1@2902.41,2822.38 ; v1(2920.41,2945.38) 2920.41,2986.38 3384.41,3450.38 3384.41,3607.38 3506.71,3729.68 IC6.L16@3506.71,3733.78
  L3 w6: pad.1@2902.41,2822.38 2902.41,2927.38 v1(2920.41,2945.38)
  Bottom Layer w6: v1(1032.41,2630.38) 1065.41,2630.38 1123.41,2688.38 v1(1261.41,2688.38)
IC6-M4: IC6.M4 pad.1@2491.41,5416.37 R132.2 | length 3383.4
  Top Layer w6: R132.2@2288.41,6639.29 2288.41,6569.38 2244.41,6525.38 2244.41,5584.37 2360.41,5468.38 2427.41,5468.38 2479.41,5416.37 pad.1@2491.41,5416.37 2491.41,5396.38 2476.41,5381.38 2476.41,5187.38 v1(2482.41,5181.38) ; v1(3448.41,4187.38) IC6.M4@3467.3,4206.28
  Bottom Layer w6: v1(2482.41,5181.38) 2532.41,5181.38 2578.41,5135.38 2578.41,5018.38 2760.41,4836.38 3069.41,4836.38 3261.41,4644.38 3420.41,4644.38 3479.41,4585.38 3479.41,4225.38 3448.41,4194.38 v1(3448.41,4187.38)
IC6-M5: IC6.M5 pad.1@2138.41,5241.38 | length 2119.8
  Top Layer w6: pad.1@2138.41,5241.38 2138.41,5235.38 2193.41,5180.38 2262.41,5180.38 v1(2323.41,5241.38) ; IC6.M5@3467.3,4166.88 3467.91,4166.88 v1(3488.41,4187.38)
  L3 w6: v1(2323.41,5241.38) 2500.41,5241.38 2668.41,5073.38 3017.41,5073.38 v1(3039.41,5051.38)
  Bottom Layer w6: v1(3039.41,5051.38) 3043.41,5051.38 3493.41,4601.38 3493.41,4214.38 3488.41,4209.38 v1(3488.41,4187.38)
IC6-M6: IC6.M6 pad.1@2137.41,5123.38 | length 1893
  Top Layer w6: pad.1@2137.41,5123.38 2204.41,5056.37 2204.41,4977.38 2319.41,4862.38 v1(2333.41,4862.38) ; v1(3448.41,4146.38) IC6.M6@3467.3,4127.48
  L3 w6: v1(2333.41,4862.38) 2333.41,4812.38 2952.41,4193.38 3224.41,4193.38 3288.41,4129.38 3288.41,4098.38 3299.91,4086.88 3374.91,4086.88 3388.41,4100.38 3388.41,4113.38 3421.41,4146.38 v1(3448.41,4146.38)
IC6-M7: IC6.M7 pad.1@2137.41,4651.38 R127.2 | length 1836.1
  Top Layer w6: R127.2@2029.41,4763.38 2029.41,4759.38 pad.1@2137.41,4651.38 ; IC6.M7@3467.3,4088.17 3467.3,4086.48 v1(3486.41,4067.38)
  L3 w6: pad.1@2137.41,4651.38 2183.41,4605.38 2354.41,4605.38 2626.41,4333.38 2674.41,4333.38 2920.41,4087.38 3242.41,4087.38 3256.41,4073.38 3300.41,4029.38 3368.61,4029.38 3388.61,4009.38 3415.41,4009.38 3426.41,4020.38 3426.41,4037.38 3437.31,4048.28 3470.31,4048.28 3486.41,4064.37 v1(3486.41,4067.38)
IC6-M9: IC6.M9 pad.1@2137.41,4180.38 | length 1608.7
  Top Layer w6: IC6.M9@3467.3,4009.38 3467.41,4009.38 v1(3487.41,3989.38)
  L3 w6: v1(2388.41,3994.38) 2648.41,3994.38 2713.41,3929.38 v1(2715.41,3929.38)
  Bottom Layer w6: pad.1@2137.41,4180.38 2142.41,4180.38 2222.41,4100.38 2337.41,4100.38 2388.41,4049.38 2388.41,4011.38 ; v1(2388.41,3994.38) 2388.41,4011.38 ; 2388.41,4008.37 2388.41,4011.38 ; v1(2715.41,3929.38) 2716.41,3929.38 2787.41,3858.38 2994.41,3858.38 3003.41,3849.38 3206.41,3849.38 3266.41,3909.38 3406.41,3909.38 3486.41,3989.38 v1(3487.41,3989.38)
IC6-M10: IC6.M10 pad.1@2137.41,3886.38 | length 1492.4
  Top Layer w6: v1(3447.41,3911.38) 3447.41,3950.08 IC6.M10@3467.3,3969.98
  L3 w6: pad.1@2137.41,3886.38 2155.41,3904.37 2323.86,3904.37 2396.86,3977.38 2635.41,3977.38 2723.41,3889.38 2760.41,3889.38 2799.41,3850.38 3272.41,3850.38 3333.41,3911.38 v1(3447.41,3911.38)
IC6-N3: IC6.N3 pad.1@2433.41,5416.37 R131.2 | length 3276.2
  Top Layer w5: 2433.41,5008.37 2433.41,5156.38 2387.41,5202.38 2387.41,5303.38 2435.41,5351.38 2435.41,5411.55 ccw(c2428.58,5411.55) pad.1@2433.41,5416.37
  Top Layer w6: R131.2@2191.41,6640.29 2191.41,6581.38 2222.41,6550.38 2222.41,5554.38 2327.41,5449.38 2400.41,5449.38 pad.1@2433.41,5416.37 ; 2433.41,5008.37 v1(2459.41,4982.38) ; v1(3409.41,4265.38) 3427.91,4246.88 IC6.N3@3427.91,4245.58
  L3 w6: v1(2459.41,4982.38) 2459.41,4981.38 2663.41,4777.38 2663.41,4572.38 2819.41,4416.37 3180.41,4416.37 3194.41,4402.38 3271.41,4402.38 3303.41,4370.38 3343.41,4370.38 3363.41,4350.38 3363.41,4299.38 3397.41,4265.38 v1(3409.41,4265.38)
IC6-N5: IC6.N5 pad.1@2137.41,5183.38 | length 2002.3
  Top Layer w6: v1(3409.41,4186.38) 3427.91,4167.87 IC6.N5@3427.91,4166.88
  L3 w6: pad.1@2137.41,5183.38 2286.41,5183.38 2371.41,5098.38 2371.41,5037.38 2642.41,4766.38 2642.41,4561.38 2876.41,4327.38 2960.41,4327.38 3009.41,4376.37 3112.41,4376.37 3147.41,4341.38 3264.41,4341.38 3294.41,4311.38 3294.41,4182.38 3312.41,4164.38 3386.41,4164.38 3408.41,4186.38 v1(3409.41,4186.38)
IC6-N6: IC6.N6 pad.1@2137.41,4888.37 | length 1797
  Top Layer w6: IC6.N6@3427.91,4127.48 3427.91,4125.88 v1(3447.41,4106.38)
  L3 w6: pad.1@2137.41,4888.37 2193.41,4832.37 2193.41,4684.38 2249.41,4628.38 2361.41,4628.38 2569.41,4420.38 v1(2600.41,4420.38)
  Bottom Layer w6: v1(2600.41,4420.38) 2609.41,4420.38 2937.41,4092.38 3262.41,4092.38 3305.41,4049.38 3376.41,4049.38 3397.41,4070.38 3411.41,4070.38 v1(3447.41,4106.38)
IC6-N8: IC6.N8 pad.1@2137.41,4358.38 | length 1527.3
  Top Layer w6: IC6.N8@3427.91,4048.78 3427.91,4047.87 v1(3447.41,4028.38)
  Bottom Layer w6: pad.1@2137.41,4358.38 2147.41,4358.38 2192.41,4403.38 2371.41,4403.38 2383.41,4391.38 2573.41,4391.38 2636.41,4328.37 2671.41,4328.37 2926.41,4073.38 3256.41,4073.38 3293.41,4036.38 3387.11,4036.38 3405.1,4054.38 3421.41,4054.38 v1(3447.41,4028.38)
IC6-N9: IC6.N9 pad.1@2137.41,4122.38 | length 1595.7
  Top Layer w6: pad.1@2137.41,4122.38 2148.41,4122.38 2175.41,4095.38 2175.41,4016.37 2195.41,3996.38 2326.41,3996.38 2338.41,3984.37 v1(2361.41,3984.37) ; IC6.N9@3427.91,4009.38 3427.91,4008.88 v1(3447.41,3989.38)
  L3 w6: v1(2361.41,3984.37) 2361.41,3996.38 2384.41,4019.38 2660.41,4019.38 2816.41,3863.38 3267.41,3863.38 3333.41,3929.38 3414.41,3929.38 3447.41,3962.38 v1(3447.41,3989.38)
IC6-N16: IC6.N16 pad.1@2488.41,2825.38 | length 1459.9
  Top Layer w6: v1(3370.41,3696.37) 3390.5,3696.37 IC6.N16@3427.91,3733.78
  L3 w6: pad.1@2488.41,2825.38 2488.41,2850.38 2636.41,2998.38 2893.41,2998.38 3370.41,3475.38 v1(3370.41,3696.37)
IC6-P5: IC6.P5 pad.1@2137.41,5005.38 | length 1748.7
  Top Layer w6: v1(3368.41,4186.38) 3387.91,4166.88 IC6.P5@3388.61,4166.88
  Bottom Layer w6: pad.1@2137.41,5005.38 2161.41,5005.38 2177.41,4989.38 2345.41,4989.38 2404.41,4930.38 2404.41,4772.38 2459.41,4717.38 2579.41,4717.38 2630.41,4666.38 2630.41,4579.38 2999.41,4210.38 3306.41,4210.38 3314.41,4218.38 3336.41,4218.38 v1(3368.41,4186.38)
IC6-P6: IC6.P6 pad.1@2137.41,4711.38 R126.2 | length 1692.2
  Top Layer w6: R126.2@2025.95,4852.38 2046.41,4852.38 2103.41,4795.38 2103.41,4745.38 pad.1@2137.41,4711.38 ; v1(3368.41,4146.38) 3387.3,4127.48 IC6.P6@3388.61,4127.48
  Bottom Layer w6: pad.1@2137.41,4711.38 2175.41,4673.38 2255.41,4673.38 2415.41,4513.38 2626.41,4513.38 2971.41,4168.37 3268.41,4168.37 3290.41,4146.38 v1(3368.41,4146.38)
IC6-P7: IC6.P7 pad.1@2137.41,4533.38 R218.1 | length 1543.8
  Top Layer w6: R218.1@2079.41,4481.38 2079.41,4502.38 2110.41,4533.38 pad.1@2137.41,4533.38 ; v1(3368.41,4068.38) 3388.2,4088.17 IC6.P7@3388.61,4088.17
  Bottom Layer w6: pad.1@2137.41,4533.38 2140.41,4533.38 2172.41,4501.38 2340.41,4501.38 2392.41,4449.38 2608.41,4449.38 2912.41,4145.38 3250.41,4145.38 3306.41,4089.38 3347.41,4089.38 v1(3368.41,4068.38)
IC6-P8: IC6.P8 pad.1@2137.41,4298.38 | length 1501.8
  Top Layer w6: IC6.P8@3388.61,4048.78 3388.61,4048.17 v1(3408.41,4028.38)
  Bottom Layer w6: pad.1@2137.41,4298.38 2307.41,4298.38 2614.41,3991.38 2716.41,3991.38 2727.41,3980.38 2846.41,3980.38 2878.41,3948.38 2954.41,3948.38 3051.41,4045.38 3265.41,4045.38 3292.41,4018.38 3401.41,4018.38 3408.41,4025.38 v1(3408.41,4028.38)
IC6-P9: IC6.P9 pad.1@2137.41,3944.37 | length 1366.8
  Top Layer w6: v1(2395.41,4092.38) 2396.41,4091.38 2739.41,4091.38 2763.41,4067.38 3261.41,4067.38 3299.41,4029.38 3368.61,4029.38 IC6.P9@3388.61,4009.38
  L3 w6: pad.1@2137.41,3944.37 2178.41,3944.37 2236.41,4002.38 2315.41,4002.38 2332.41,4019.38 2332.41,4053.38 2371.41,4092.38 v1(2395.41,4092.38)
IC6-P11: IC6.P11 pad.1@2137.41,3768.37 | length 1584.7
  Top Layer w6: pad.1@2137.41,3768.37 2189.41,3768.37 2198.41,3777.38 2198.41,3867.38 2233.41,3902.38 2322.41,3902.38 2361.41,3863.38 2361.41,3753.38 2392.41,3722.38 2792.41,3722.38 2826.41,3756.38 3147.41,3756.38 3302.41,3911.38 3369.3,3911.38 IC6.P11@3388.61,3930.68
IC6-P16: IC6.P16 pad.1@2430.41,2825.38 | length 1433
  Top Layer w6: pad.1@2430.41,2825.38 2439.41,2834.38 2439.41,2867.38 3040.41,3468.38 3155.41,3468.38 3227.41,3540.38 3227.41,3576.38 3243.41,3592.38 3327.41,3592.38 3335.41,3600.38 3335.41,3693.38 3358.41,3716.38 3377.41,3716.38 3388.61,3727.58 IC6.P16@3388.61,3733.78
IC6-R9: IC6.R9 pad.1@2137.41,4062.38 | length 1312.4
  Top Layer w6: v1(3329.41,3989.38) 3349.21,4009.18 IC6.R9@3349.21,4009.38
  L3 w6: v1(2360.41,4041.38) 2388.41,4069.38 3230.41,4069.38 3310.41,3989.38 v1(3329.41,3989.38)
  Bottom Layer w6: pad.1@2137.41,4062.38 2207.41,4062.38 2236.41,4033.38 2236.41,4022.38 2256.41,4002.38 2317.41,4002.38 2356.41,4041.38 v1(2360.41,4041.38)
IC6-R16: IC6.R16 pad.1@2253.41,2825.38 | length 1540.6
  Top Layer w6: pad.1@2253.41,2825.38 2263.41,2835.38 2263.41,2877.38 2511.41,3125.38 2594.41,3125.38 2745.41,3276.38 2829.41,3276.38 3043.41,3490.38 3150.41,3490.38 3208.41,3548.38 3208.41,3623.38 3240.41,3655.38 3256.41,3655.38 3269.41,3668.38 3283.81,3668.38 IC6.R16@3349.21,3733.78
IC6-T4: IC6.T4 pad.1@2137.41,4948.38 | length 1594.8
  Top Layer w6: v1(3273.41,4236.38) 3303.51,4206.28 IC6.T4@3309.8,4206.28
  L3 w6: pad.1@2137.41,4948.38 2280.41,4948.38 2357.51,4871.29 2357.51,4817.28 2874.41,4300.38 2970.41,4300.38 3024.41,4354.38 3098.41,4354.38 3130.41,4322.38 3253.41,4322.38 3273.41,4302.38 v1(3273.41,4236.38)
IC6-T7: IC6.T7 pad.1@2137.41,4416.37 | length 1482.3
  Top Layer w6: pad.1@2137.41,4416.37 2197.41,4356.38 2197.41,4127.38 2218.41,4106.38 2315.41,4106.38 2343.41,4134.38 3036.41,4134.38 3056.41,4154.38 3243.41,4154.38 3261.41,4136.37 3261.6,4136.37 IC6.T7@3309.8,4088.17
IC6-T8: IC6.T8 pad.1@2137.41,4240.37 | length 1286.9
  Top Layer w6: v1(2363.41,4109.38) 2370.41,4116.38 2761.41,4116.38 2793.41,4084.38 3274.21,4084.38 IC6.T8@3309.8,4048.78
  Bottom Layer w6: pad.1@2137.41,4240.37 2138.41,4240.37 2175.41,4203.38 2319.41,4203.38 2355.41,4167.38 2355.41,4117.38 v1(2363.41,4109.38)
IC6-T9: IC6.T9 pad.1@2137.41,4004.38 | length 1259.2
  Top Layer w6: v1(2202.41,4030.38) 2202.41,4053.38 2244.41,4095.38 2306.41,4095.38 2328.41,4073.38 2722.41,4073.38 2740.41,4055.38 3249.41,4055.38 3295.41,4009.38 IC6.T9@3309.8,4009.38
  Bottom Layer w6: pad.1@2137.41,4004.38 2176.41,4004.38 v1(2202.41,4030.38)
IC7-3: IC6.E7 IC7.3 P1.17 pad.1@4734.41,3878.38 | length 2620.5
  Top Layer w6: IC6.E7@3742.91,4088.17 3746.21,4088.17 v1(3764.4,4106.38) ; pad.1@4734.41,3878.38 4763.41,3907.38 4962.41,3907.38 4971.41,3898.38 ; IC7.3@4972,3797.52 4972,3920.97 5013.41,3962.38 v1(5013.41,3978.38)
  L3 w6: v1(3764.4,4106.38) 3764.4,4106.08 3782.1,4088.37 3929.41,4088.37 3958.41,4059.38 3958.41,3996.38 3980.87,3973.91 4250.93,3973.91 4325.41,4048.37 4627.41,4048.37 4696.41,3979.38 4696.41,3916.38 pad.1@4734.41,3878.38
  Bottom Layer w6: v1(5013.41,3978.38) 5013.41,4265.38 5148.4,4400.37 5329.3,4400.37 5356.81,4427.88 5356.81,4623.78 5384.4,4651.38 P1.17@5392.4,4651.38
IC7-5: IC6.A8 IC7.5 P1.12 pad.1@4734.41,3818.38 | length 2116.7
  Top Layer w6: IC6.A8@3900.4,4048.78 3997,4048.78 4069.41,3976.37 ; 4073.41,3972.38 4069.41,3976.37 ; IC7.5@4920.81,3797.52 4920.81,3862.79 v1(4925.41,3867.38) 4922.41,3867.38 4913.41,3876.38 4854.41,3876.38 4831.41,3853.38 4831.41,3822.38 4827.41,3818.38 pad.1@4734.41,3818.38 4695.41,3857.38 4695.41,3987.38 4652.4,4030.38 4380.4,4030.38 4334.41,3984.37 4273.41,3984.37 4260.4,3971.38 4074.41,3971.38 4069.41,3976.37
  Bottom Layer w6: v1(4925.41,3867.38) 4925.41,3887.38 4972.4,3934.38 5027.41,3934.38 5052.4,3959.37 5052.4,4247.37 5156.4,4351.38 P1.12@5292.4,4351.38
IC7-9: IC6.D8 IC7.9 P1.15 pad.1@4734.41,3582.38 | length 3186.1
  Top Layer w6: IC6.D8@3782.3,4048.78 3782.81,4048.78 v1(3802.41,4068.38) ; IC7.9@4895.23,3565.24 4895.23,3627.2 v1(4895.41,3627.38)
  L3 w6: v1(3802.41,4068.38) 3822.41,4048.37 3885.41,4048.37 4027.41,3906.38 4027.41,3682.38 4146.41,3563.38 4146.41,3505.38 4162.41,3489.38 4400.41,3489.38 4479.41,3410.38 4639.41,3410.38 4682.41,3453.38 4682.41,3530.38 pad.1@4734.41,3582.38
  Bottom Layer w6: pad.1@4734.41,3582.38 4779.41,3627.38 v1(4895.41,3627.38) 4935.41,3587.38 4989.41,3587.38 5083.41,3681.38 5120.41,3681.38 5122.41,3681.38 5239.41,3798.38 5446.41,3798.38 5460.4,3812.38 5460.4,4471.38 P1.15@5392.4,4539.38
IC13-4: IC6.N1 IC13.4 pad.1@2788.41,5413.38 R20.2 | length 2199.7
  Top Layer w6: IC13.4@2493.21,5853.38 2493.21,5881.18 2532.41,5920.37 ; R20.2@2532.41,5967.38 2532.41,5920.37 ; IC6.N1@3427.91,4324.38 3427.91,4550.88 3426.59,4552.19 3078.41,4900.38 3078.41,4996.38 3069.41,5005.38 3069.41,5151.38 3011.41,5209.38 2967.41,5209.38 2948.41,5228.38 2948.41,5330.38 2917.41,5361.38 2840.41,5361.38 pad.1@2788.41,5413.38 2735.41,5466.38 2681.41,5466.38 2647.41,5500.38 2647.41,5805.38 2532.41,5920.37
IC13-5: IC6.M3 IC13.5 pad.1@2670.41,5413.38 R24.2 | length 2833.1
  Top Layer w6: IC13.5@2418.41,5853.38 2411.41,5860.38 2379.41,5860.38 2378.41,5861.38 ; R24.2@2425.01,5967.38 2392.41,5967.38 2378.41,5953.38 2378.41,5861.38 ; pad.1@2670.41,5413.38 2615.41,5468.38 2615.41,5727.38 2536.95,5805.83 2391.95,5805.83 2378.41,5819.38 2378.41,5861.38 ; v1(3448.41,4265.38) 3467.3,4246.48 IC6.M3@3467.3,4245.58
  Bottom Layer w6: pad.1@2670.41,5413.38 2670.41,5401.38 2638.41,5369.38 2605.41,5369.38 2446.41,5210.38 2446.41,5089.38 2735.41,4800.37 3066.41,4800.37 3242.41,4624.37 3377.41,4624.37 3454.41,4547.38 3454.41,4347.38 3467.41,4334.38 3467.41,4284.38 v1(3448.41,4265.38)
IC21-2: IC6.M16 IC21.2 pad.1@2725.41,2822.38 | length 3347.1
  Top Layer w5: IC21.2@986.41,2726.38 903.41,2726.38 894.41,2735.38 894.41,2783.38 923.41,2812.38 1072.41,2812.38 1170.41,2910.38 1419.91,2910.38 1503.91,2826.38 2018.41,2826.38 2089.41,2755.38 2673.41,2755.38 2724.41,2806.38
  Top Layer w6: pad.1@2725.41,2807.38 pad.1@2725.41,2822.38 2728.41,2822.38 3367.41,3461.38 3367.41,3611.38 3467.3,3711.28 IC6.M16@3467.3,3733.78
IC21-4: IC6.J13 IC21.4 pad.1@2842.41,2822.38 | length 3444.1
  Top Layer w5: IC21.4@980.17,2675.76 1018.79,2675.76 1027.41,2684.38 1027.41,2704.38 1196.41,2873.38 1402.41,2873.38 1501.41,2774.38 1786.41,2774.38 1863.41,2697.38 2739.41,2697.38 2842.41,2800.38 pad.1@2842.41,2822.38
  Top Layer w6: v1(3567.41,3831.38) 3585.41,3849.38 IC6.J13@3585.41,3851.87
  Bottom Layer w6: pad.1@2842.41,2822.38 2844.41,2824.38 2844.41,2986.38 3398.41,3540.38 3398.41,3606.38 3478.41,3686.38 3501.41,3686.38 3540.41,3725.38 3540.41,3801.38 3567.41,3828.38 v1(3567.41,3831.38)
IC28-3: IC6.H11 IC28.1 IC28.3 pad.1@2667.41,2822.38 R92.1 TP20.1 | length 2555.3
  Top Layer w6: IC28.1@2190,2387.91 2190,2413.98 2200.41,2424.38 2262.41,2424.38 ; IC28.3@2264.8,2387.91 2264.8,2421.98 2262.41,2424.38 ; TP20.1@2625.41,2425.38 2568.41,2368.38 2389.86,2368.38 R92.1@2362.41,2395.83 2334.95,2395.83 2306.41,2424.38 2262.41,2424.38 ; v1(3605.41,3950.38) 3624.8,3930.98 IC6.H11@3624.8,3930.68
  Bottom Layer w6: TP20.1@2625.41,2425.38 2623.41,2427.38 2623.41,2678.38 2667.41,2722.38 pad.1@2667.41,2822.38 2663.41,2826.38 2663.41,2896.38 3215.41,3448.38 3262.41,3448.38 3372.41,3558.38 3372.41,3606.38 3470.41,3704.37 3494.41,3704.37 3527.41,3737.38 3527.41,3805.38 3546.41,3824.37 3546.41,3890.38 3605.41,3949.38 v1(3605.41,3950.38)
IFCLK: IC1.20 IC6.L1 pad.1@3141.41,5413.38 | length 2693.7
  Top Layer w6: pad.1@3141.41,5413.38 3141.41,5537.38 3250.41,5646.38 3612.41,5646.38 3681.41,5715.38 3681.41,5829.38 3715.41,5863.38 3956.4,5863.38 4039.41,5946.38 4095.41,5946.38 4113.41,5964.38 IC1.20@4113.41,6070.38 ; v1(3145.41,5218.38) 3145.41,5018.38 3188.41,4975.38 3188.41,4884.38 3413.91,4658.88 ; 3408.41,4664.37 3413.91,4658.88 ; IC6.L1@3506.71,4324.38 3506.71,4358.08 3475.41,4389.38 3475.41,4597.38 3413.91,4658.88
  Bottom Layer w6: pad.1@3141.41,5413.38 3141.41,5222.38 v1(3145.41,5218.38)
J17-3: IC6.N11 J17.3 R30.2 | length 1683.5
  Top Layer w6: J17.3@2279.41,3853.38 2306.41,3853.38 2339.41,3820.38 2339.41,3735.38 2383.41,3691.38 2520.41,3691.38 2531.95,3679.83 R30.2@2531.95,3653.38 ; v1(3408.41,3950.38) 3427.91,3930.88 IC6.N11@3427.91,3930.68
  Bottom Layer w6: J17.3@2279.41,3853.38 2335.41,3909.38 2335.41,3910.38 2335.41,3924.38 2385.41,3974.38 2615.41,3974.38 2624.41,3965.38 2718.41,3965.38 2773.41,3910.38 2977.41,3910.38 3006.41,3881.38 3218.41,3881.38 3260.41,3923.38 3381.41,3923.38 v1(3408.41,3950.38)
LVT244_IN4: IC6.M14 IC21.17 pad.1@2370.41,2825.38 | length 4063.6
  Top Layer w6: IC21.17@1200.64,2675.76 1229.02,2675.76 v1(1260.41,2644.38) ; v1(1692.41,2569.38) 1706.41,2555.38 1880.41,2555.38 1933.41,2608.38 2794.41,2608.38 2887.41,2701.38 v1(2887.41,2735.38) ; v1(3407.41,3751.38) 3430.41,3751.38 3447.41,3768.38 3447.41,3792.67 IC6.M14@3467.3,3812.58
  L3 w6: v1(2887.41,2735.38) 2828.41,2735.38 2787.41,2776.38 2419.41,2776.38 pad.1@2370.41,2825.38 2370.41,2867.38 2527.41,3024.38 2895.41,3024.38 3348.41,3477.38 3348.41,3704.37 3363.41,3719.38 3375.41,3719.38 v1(3407.41,3751.38)
  Bottom Layer w6: v1(1260.41,2644.38) 1260.41,2643.38 1282.41,2621.38 1491.41,2621.38 1505.41,2607.38 1654.41,2607.38 v1(1692.41,2569.38)
NetC43_1: C43.1 IC13.1 R25.1 | length 476.8
  Top Layer w6: R25.1@2418.01,5612.78 2418.41,5613.18 2418.41,5660.38 IC13.1@2418.41,5758.88
  Top Layer w10: R25.1@2418.01,5612.78 2418.01,5748.98 2418.41,5749.38 IC13.1@2418.41,5758.88 ; 2418.41,5660.38 2522.41,5660.38 2533,5649.78 C43.1@2533,5584.48
NetC44_2: C44.2 IC6.T2 R21.2 TP21.1 | length 898.1
  Top Layer w6: R21.2@2785.41,4754.38 2785.41,4713.38 2796.41,4702.38 C44.2@2905.41,4702.38 2958.41,4702.38 2992.41,4736.37 TP21.1@3015.41,4736.37 3075.41,4736.37 3233.41,4578.38 3233.41,4418.38 3290.41,4361.38 3290.41,4304.37 IC6.T2@3309.8,4284.98
NetC54_1: C54.1 J1.3 TR2.2 TR2.3
NetC55_2: C55.2 J1.5 TR3.2 TR3.3 | length 21.3
  Bottom Layer w6: J1.5@1284.85,7595.01 1293,7603.16 J1.5@1293,7612.98
NetC71_2: C71.2 IC19.22 IC19.23 L6.1
NetC83_1: C83.1 R56.2 R62.1 | length 699
  Top Layer w5: R62.1@695.41,1355.83 723.86,1355.83 770.41,1402.38 v1(770.41,1411.38) ; R56.2@1090.41,1036.92 1090.41,1064.38 1048.41,1106.38 v1(1048.41,1122.38) 1066.86,1140.83 C83.1@1091.41,1140.83
  Bottom Layer w5: v1(770.41,1411.38) 835.41,1411.38 1048.41,1198.38 v1(1048.41,1122.38)
NetC86_1: C86.1 R57.2 R63.1 | length 847.5
  Top Layer w10: R63.1@668.41,780.29 686.32,780.29 702.41,796.38 702.41,863.38 v1(731.41,892.38) ; R57.2@1102.41,532.92 1102.95,532.92 1145.41,575.38 v1(1145.41,623.38) 1142.15,626.64 C86.1@1102.41,626.64
  Bottom Layer w5: v1(731.41,892.38) 911.41,892.38 1145.41,658.38 v1(1145.41,623.38)
NetC88_2: C88.2 IC23.5 R56.1 | length 297.8
  Top Layer w5: C88.2@971.95,1094.38 973.95,1096.38 1005.79,1096.38 1006.1,1096.69 ; IC23.5@1006.1,1194.17 1006.41,1193.87 1006.41,1097 1006.1,1096.69 ; R56.1@1090.41,979.83 1067.95,979.83 1006.41,1041.38 1006.41,1096.38 1006.1,1096.69
NetC90_1: C90.1 D10.3 D14.1 D14.2 IC23.3 R68.2 R69.2 | length 977.7
  Top Layer w10: D10.3@604.41,1010.38 D10.3@593.41,1021.38 663.41,1021.38 669.91,1027.88 ; C90.1@728.41,1010.38 678.41,1010.38 669.91,1018.88 669.91,1027.88 ; IC23.3@797.12,1244.18 700.93,1244.18 R68.2@678.22,1221.48 669.41,1212.66 669.41,1028.38 669.91,1027.88
  Top Layer w40: D14.1@194.7,1050.14 D14.2@269.51,1050.14 279.17,1050.14 329.41,1100.38 462.41,1100.38 475.22,1087.56 R69.2@475.22,1032.48 488.32,1019.38 490.32,1021.38 D10.3@593.41,1021.38
NetC91_2: C91.2 IC24.5 R57.1 | length 347.7
  Top Layer w10: IC24.5@1006.1,699.37 1035.41,699.37 1046.41,688.38 1046.41,586.38 ; C91.2@1008.95,586.38 1046.41,586.38 ; R57.1@1102.41,475.83 1051.86,475.83 1046.41,481.29 1046.41,586.38
NetC93_1: C93.1 D11.3 IC24.3 R72.2 R73.2 | length 698.9
  Top Layer w10: R73.2@494.95,334.38 497.95,337.38 R73.2@507.41,337.38 ; R73.2@505.41,339.38 518.41,339.38 621.71,442.68 D11.3@621.71,469.94 672.96,469.94 713.41,510.38 ; C93.1@769.86,494.38 729.41,494.38 713.41,510.38 ; IC24.3@786.41,749.38 764.41,749.38 678.41,663.38 R72.2@666.95,663.38 666.95,643.83 713.41,597.38 713.41,510.38
NetC94_2: C94.2 R118.2 | length 95.8
  Top Layer w6: R118.2@3258.95,1851.38 3258.95,1924.92 3263.41,1929.38 C94.2@3263.41,1945.38
NetC96_2: C96.2 J25.9 TR10.2 TR10.3
NetC97_2: C97.2 J25.8 TR11.2 TR11.3
NetC98_2: C98.2 J25.7 TR12.2 TR12.3
NetC99_1: C99.1 J25.6 TP19.1 TR13.2 TR13.3
NetC100_1: C100.1 C101.1 C102.2 C103.2 IC20.11 IC20.14 IC20.16 IC20.20 R86.2 | length 606.5
  Top Layer w20: C100.1@485.63,3471.66 534.12,3471.66 v1(535.41,3470.38) ; C102.2@486.01,2946.17 531.92,2946.17 v1(539.41,2938.68) ; C101.1@593.41,3484.5 646.52,3484.5 v1(651.41,3489.38) ; C103.2@597,2938.68 628.1,2938.68 v1(648.41,2918.38) ; v1(661.41,2964.38) 662.41,2963.38 IC20.20@728.96,2963.38 ; v1(665.41,3413.38) IC20.11@728.96,3413.38 ; IC20.16@728.96,3163.38 809.41,3163.38 v1(814.41,3168.38) ; IC20.14@728.96,3263.38 809.41,3263.38 v1(810.41,3264.38)
  Top Layer w50: v2(798.41,3491.38) 838.01,3530.98 R86.2@838.01,3553.98
NetC100_2: C100.2 C101.2 C102.1 C103.1 IC20.12 IC20.19 | length 358.5
  Top Layer w20: v1(483.41,3347.38) 485.63,3349.6 C100.2@485.63,3396.86 ; C102.1@486.01,3020.97 486.01,3065.99 v1(489.41,3069.38) ; C101.2@593.41,3372.29 593.41,3349.38 v1(620.41,3322.38) ; C103.1@597,3013.48 597,3062.98 v1(602.41,3068.38) ; v1(656.41,3013.48) 656.51,3013.38 IC20.19@733.41,3013.38 ; v1(666.41,3362.38) 667.41,3363.38 IC20.12@728.96,3363.38
NetC104_1: C104.1 D12.3 D14.3 IC23.2 R66.1 R67.1 | length 830.7
  Top Layer w20: R67.1@392.31,1355.96 393.43,1354.83 R66.1@494.41,1354.83 497.41,1351.83 C104.1@589.41,1351.83 589.41,1327.38 622.61,1294.17 IC23.2@797.12,1294.17 ; D12.3@418.41,1252.38 418.41,1290.98
  Top Layer w30: D14.3@232.1,1132.82 232.1,1135.08 363.41,1266.38 D12.3@408.41,1266.38 ; R67.1@392.31,1355.96 392.31,1330.28 418.41,1304.18 D12.3@418.41,1252.38
NetC104_2: C104.2 IC23.1 R66.2 R79.2 | length 586.3
  Top Layer w5: R66.2@494.41,1411.92 495.86,1413.38 584.95,1413.38 C104.2@589.41,1408.92 589.86,1409.38 620.41,1409.38 642.41,1387.38 642.41,1338.38 659.41,1321.38 736.41,1321.38 759.21,1344.18 IC23.1@797.12,1344.18 846.21,1344.18 930.95,1428.92 R79.2@930.95,1466.38
NetC105_1: C105.1 IC24.1 R70.2 R80.1 | length 564.9
  Top Layer w10: R70.2@477.41,839.38 572.41,839.38 C105.1@574.41,837.38 ; R80.1@605.86,929.38 605.86,911.83 574.41,880.38 C105.1@574.41,837.38 ; IC24.1@781.41,850.38 751.41,850.38 720.41,819.38 720.41,780.38 677.41,737.38 627.41,737.38 614.41,750.38 614.41,825.38 602.41,837.38 C105.1@574.41,837.38
NetC105_2: C105.2 D13.3 IC24.2 R70.1 R71.2 | length 824.2
  Top Layer w10: D13.3@467.41,511.28 480.31,511.28 528.49,559.47 528.49,780.29 ; R71.2@479.41,676.92 479.41,780.29 528.49,780.29 ; IC24.2@797.12,799.37 759.4,799.37 738.41,778.38 738.41,762.38 687.41,711.38 597.41,711.38 574.41,734.38 C105.2@574.41,780.29 551.86,780.29 528.49,780.29
NetC106_2: C106.2 R62.2 R79.1 | length 253.6
  Top Layer w5: R62.2@695.41,1412.92 714.99,1412.92 768.45,1466.38 ; C106.2@768.45,1519.38 768.45,1466.38 ; R79.1@873.86,1466.38 768.45,1466.38
NetC107_2: C107.2 R63.2 R80.2 | length 426.7
  Top Layer w10: C107.2@478.95,918.38 499.41,918.38 550.41,969.38 660.41,969.38 ; R80.2@662.95,929.38 662.95,966.83 660.41,969.38 ; R63.2@668.41,837.38 668.41,869.38 703.41,904.38 703.41,958.38 692.41,969.38 660.41,969.38
NetC108_1: C108.1 R130.1 TR3.5 | length 2403
  Top Layer w6: C108.1@1120.41,7557.92 1120.41,7609.38 1192.41,7681.38 1192.41,7736.37 1213.41,7757.38 v1(1307.41,7757.38) 1446.41,7896.37 1848.41,7896.37 1927.41,7817.37 1927.41,7473.38 1960.41,7440.37 1960.41,7211.38 2384.41,6787.38 R130.1@2384.41,6694.92
  Bottom Layer w6: TR3.5@1293,7800.37 1293,7771.78 v1(1307.41,7757.38)
NetC109_1: C109.1 R131.1 TR2.5 | length 1805.6
  Top Layer w6: v1(1452.01,7754.14) 1452.01,7743.98 1359.41,7651.38 1359.41,7311.38 1336.41,7288.37 C109.1@1336.41,7216.92 1349.86,7216.92 1497.41,7069.38 1995.41,7069.38 2191.41,6873.38 R131.1@2191.41,6697.38
  Bottom Layer w6: v1(1452.01,7754.14) TR2.5@1452.01,7801.38
NetC110_1: C110.1 R132.1 TR1.5 | length 1765.7
  Top Layer w6: v1(1595.41,7751.38) 1595.41,7817.38 1630.41,7852.38 1850.6,7852.38 1916.41,7786.58 1916.41,7543.38 ; C110.1@1880.41,7543.92 1915.86,7543.92 1916.41,7543.38 ; R132.1@2288.41,6696.37 2288.41,6824.37 1916.41,7196.38 1916.41,7543.38
  Bottom Layer w6: v1(1595.41,7751.38) 1611,7766.98 TR1.5@1611,7801.38
NetC111_2: C111.2 C135.1 C136.2 J25.10 L1.1 R88.1 TP18.1 | length 280.4
  Top Layer w20: L1.1@477.41,6627.95 548.44,6556.92 R88.1@728.41,6556.92
NetC114_2: C114.2 L3.1 R91.1 | length 194.8
  Top Layer w6: C114.2@1745.95,2384.38 1750.41,2384.38 1755.41,2379.38 L3.1@1755.41,2284.38 1829.41,2284.38 1829.95,2283.83 R91.1@1843.41,2283.83
NetC115_2: C115.2 C116.2 IC28.2 IC29.5 | length 283.1
  Top Layer w6: C116.2@2123.95,2361.38 2123.95,2306.83 2123.95,2264.92 C115.2@2125.5,2263.38 ; 2125.71,2305.07 IC29.5@2227.25,2305.07 2227.25,2312.22 2227.41,2312.38 IC28.2@2227.41,2387.91
NetC117_1: C117.1 R91.2 | length 125.7
  Top Layer w6: R91.2@1843.41,2340.92 1846.29,2343.8 C117.1@1846.29,2465.38
NetC117_2: C117.2 R90.1 | length 102.2
  Top Layer w6: C117.2@1958.49,2465.38 1960.49,2467.38 R90.1@2059.86,2467.38
NetC118_1: C118.1 J39.5 L7.2 | length 333.5
  Top Layer w6: J39.5@1288.4,2259.38 1504.41,2259.38 L7.2@1509.41,2264.38 1509.41,2372.08 C118.1@1511.3,2373.98
NetC119_1: C119.1 L3.2 L7.1 | length 183.1
  Top Layer w6: C119.1@1599.86,2165.38 1599.86,2259.92 L7.1@1595.41,2264.38 1607.41,2276.38 1661.41,2276.38 L3.2@1669.41,2284.38
NetC121_1: C121.1 R93.1 | length 108.7
  Top Layer w15: C121.1@4982.41,1881.83 4984.41,1879.83 R93.1@4984.41,1773.92
NetC121_2: C121.2 IC30.4 R94.2 | length 209.1
  Top Layer w15: R94.2@4980.4,2040.83 4980.4,1940.92 C121.2@4982.41,1938.92 5028.94,1938.92 5054.06,1964.03 IC30.4@5078.41,1964.03
NetC127_2: C127.2 IC32.15 J40.1 | length 505.1
  Top Layer w20: J40.1@4676.4,1461.38 4676.4,1718.38 4707.31,1749.28 C127.2@4743.39,1749.28 4743.38,1913.42 IC32.15@4740.4,1916.4
NetC128_2: C128.2 IC32.5 IC32.14 | length 555.6
  Top Layer w20: IC32.5@4590.41,2294.36 4590.41,2085.38 4690.41,1985.38 IC32.14@4690.41,1916.4 4690.41,1860.38 4634.41,1804.38 C128.2@4633.41,1804.38
NetC129_1: C129.1 D19.1 IC22.11 R112.1 | length 339
  Top Layer w5: C129.1@1279.41,1868.33 1369.91,1868.33 R112.1@1372.41,1865.83 1416.95,1865.83 1433.08,1849.7 D19.1@1457,1849.7 1457,1803.98 1442.41,1789.38 1410.41,1789.38 1403.91,1782.88 IC22.11@1403.91,1736.74
NetC138_1: C138.1 IC8.14 R118.1 | length 223.5
  Top Layer w6: IC8.14@3085.75,1786.38 3148.41,1786.38 3176.41,1758.38 C138.1@3203.86,1758.38 3203.86,1835.92 3201.86,1837.92 R118.1@3201.86,1851.38
NetC141_2: C141.2 IC8.2 | length 114.3
  Top Layer w6: C141.2@2765.95,1863.38 2790.41,1863.38 2817.41,1836.38 IC8.2@2869.06,1836.38
NetC144_2: C144.2 C145.1 L10.1 L11.3 R123.1 | length 7.1
  Top Layer w6: C145.1@2200.86,624.38 C145.1@2205.86,619.38
NetC145_2: C145.2 IC26.3 R123.2 R124.1 | length 859.4
  Top Layer w6: R124.1@2198.86,702.38 2198.86,668.92 2205.41,662.38 2263.41,662.38 ; R123.2@2262.95,543.38 2262.95,613.83 2257.95,618.83 C145.2@2257.95,624.38 2257.95,656.92 2263.41,662.38 ; IC26.3@2701.91,754.58 2701.91,614.89 2686.41,599.38 2359.41,599.38 2348.41,610.38 2348.41,652.38 2338.41,662.38 2263.41,662.38
NetC146_1: C146.1 IC26.1 L11.1
NetC146_2: C146.2 D16.1 L11.4
NetC148_1: C148.1 IC34.4 | length 125.1
  Top Layer w6: IC34.4@2835.41,1029.38 2835.41,1100.38 2839.41,1104.38 C148.1@2887.86,1104.38
NetD7_1: D7.1 R59.2 R60.2 | length 375.6
  Top Layer w20: R60.2@486.81,4529.98 532.01,4529.98 535.41,4533.38 ; R59.2@487.81,4658.98 514.8,4658.98 535.41,4638.38 535.41,4533.38 ; D7.1@667.41,4484.76 563.01,4484.76 535.41,4512.37 535.41,4533.38
NetD8_1: D8.1 IC25.6 IC25.7 R65.2 | length 422.2
  Top Layer w20: R65.2@502.01,5196.98 578.41,5196.98 586.41,5188.98 ; IC25.7@537.61,5031.07 537.61,5107.58 541.41,5111.38 575.41,5111.38 576.41,5112.37 ; IC25.6@587.6,5031.07 586.41,5032.26 586.41,5188.98 ; D8.1@642.41,5184.76 637,5190.18 587.6,5190.18 586.41,5188.98
NetD9_3: D9.3 OP2.5 R60.1 R61.1 | length 1337.1
  Top Layer w20: R60.1@412,4529.98 412,4492.78 428.41,4476.38 481.41,4476.38 495.41,4462.38 D9.3@495.41,4401.38 607.41,4401.38 739.41,4269.38 739.41,3941.38 805,3875.78 R61.1@889.01,3875.78 969,3875.78 981.41,3863.38 984.41,3863.38 984.41,3709.38 1001.41,3692.38 1054.41,3692.38 1056.41,3690.38 OP2.5@1061.41,3690.38
NetD15_1: D15.1 IC8.6 L4.2 L8.1 | length 101.2
  Top Layer w20: 2790.41,1624.38 2794.41,1624.38 2809.41,1639.38 IC8.6@2885.41,1639.38
NetD17_1: D17.1 L1.2 | length 240.8
  Top Layer w6: D17.1@715.59,6824.8 D17.1@717.41,6822.99
  Top Layer w20: L1.2@477.41,6824.8 D17.1@715.59,6824.8
NetD17_2: D17.2 IC27.7 IC27.OUT# | length 294.5
  Top Layer w20: D17.2@717.41,6649.77 730.22,6662.58 787.61,6662.58 811.2,6662.58 ; IC27.7@883.71,6662.58 811.2,6662.58 ; IC27.OUT#@883.71,6712.58 821.6,6712.58 803.41,6694.38 803.41,6670.38 811.2,6662.58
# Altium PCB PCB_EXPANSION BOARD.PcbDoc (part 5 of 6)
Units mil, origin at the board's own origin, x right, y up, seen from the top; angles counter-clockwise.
Board outline 5512.34 x 7953.29 mil, 6 copper layers (Top Layer, L2, L3, L4, L5, Bottom Layer); 420 components, 365 nets, 1860 pads, 895 vias.
Unrouted connection lines stored in the file: 9.

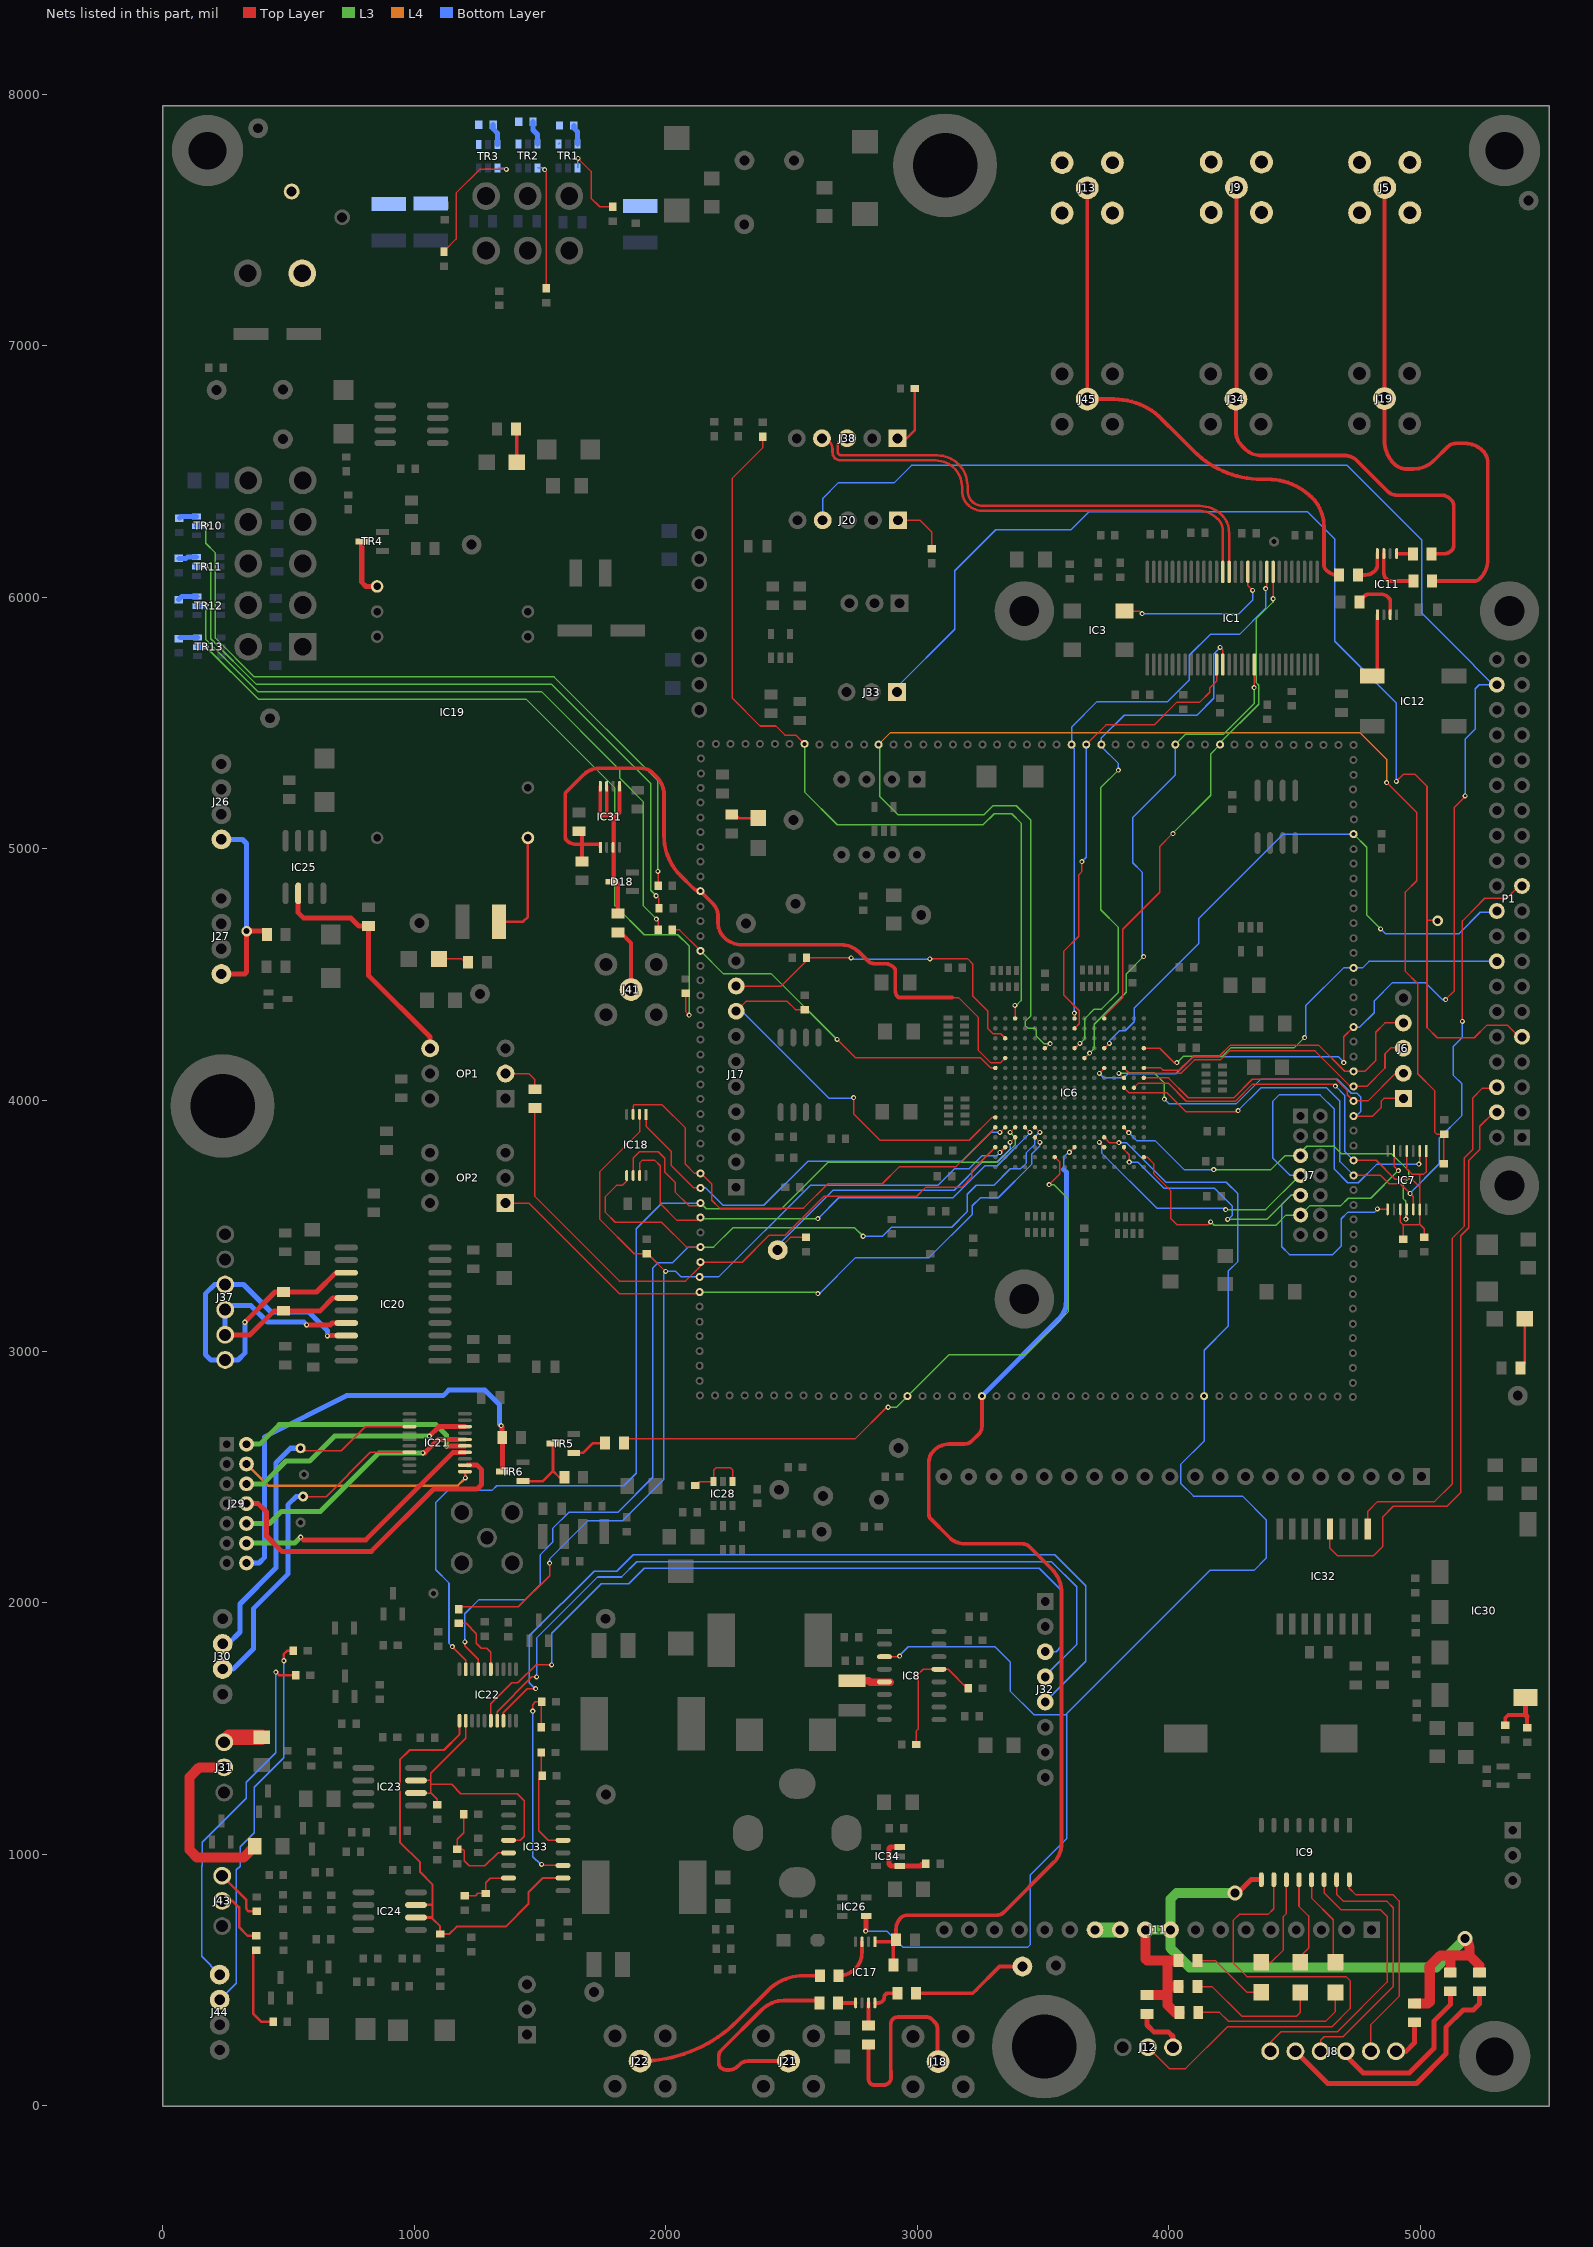
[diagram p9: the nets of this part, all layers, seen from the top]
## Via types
v1: diameter 20, hole 10, Top Layer to Bottom Layer, tented both sides, 808 vias
v2: diameter 60, hole 35, Top Layer to Bottom Layer, 47 vias
v3: diameter 42, hole 24, Top Layer to Bottom Layer, 32 vias
v4: diameter 125.98/125.98/125.98/125.98/125.98/125.98 (per signal layer), hole 125.98, Top Layer to Bottom Layer, 6 vias
v5: diameter 51.18, hole 51.18, Top Layer to Bottom Layer, 2 vias

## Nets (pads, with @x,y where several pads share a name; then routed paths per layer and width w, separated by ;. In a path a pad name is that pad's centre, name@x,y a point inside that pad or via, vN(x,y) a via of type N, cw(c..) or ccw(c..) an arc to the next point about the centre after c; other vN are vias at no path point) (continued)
NetD18_3: D18.3 IC31.3 IC31.5 IC31.7 IC31.8 R100.1 | length 953.7
  Top Layer w10: 1739.02,5151.99 IC31.8@1739.02,5247.93 ; 1790.2,5130.58 1789.41,5131.38 1804.41,5131.38 1815.79,5142.76
  Top Layer w15: IC31.8@1739.02,5247.93 1739.02,5138.76 1746.41,5131.38 1789.41,5131.38 ; 1764.61,5131.58 IC31.7@1764.61,5247.93 ; R100.1@1809.01,4741.78 1809.01,4860.78 1801.71,4868.07 D18.3@1784.96,4868.07 1790.2,4873.32 IC31.3@1790.2,5004.82 1790.2,5011.58 1790.2,5130.58 1803.61,5130.58 1815.79,5142.76 IC31.5@1815.79,5247.93
NetF1_2: F1.2 IC19.14 | length 436.9
  Top Layer w10: F1.2@1336.37,4709.38 1432.41,4709.38 1451.41,4728.37 IC19.14@1451.41,5042.38
NetF2_2: F2.2 J24.1
NetF5_2: F5.2 R23.1 TR2.4
NetF6_2: F6.2 R22.1 TR1.4 | length 4.6
  Bottom Layer w6: TR1.4@1573.6,7801.38 TR1.4@1576.86,7804.64
NetF7_2: F7.2 R32.1 TR3.4
NetIC1_12: IC1.12 IC3.3 | length 656.3
  Top Layer w6: IC3.3@3823.35,5944.15 3883.64,5944.15 v1(3893.41,5934.38) ; IC1.12@4314.41,6100.38 4314.41,6045.38 v1(4333.41,6026.38)
  Bottom Layer w6: v1(3893.41,5934.38) 3916.4,5934.38 4279.41,5934.38 4333.41,5988.38 4333.41,6004.38 v1(4333.41,6026.38)
NetIC1_15: IC1.15 J38.3 | length 1985.7
  Top Layer w10: J38.3@2720.41,6631.38 2712.41,6631.38 ccw(c2712.41,6601.38) 2682.41,6601.38 2682.41,6580.38 ccw(c2699.41,6580.38) 2699.41,6563.38 3078.52,6563.38 cw(c3078.53,6442.5) 3199.41,6442.5 3199.41,6423.38 ccw(c3260.41,6423.38) 3260.41,6362.38 ; 3254.86,6362.38 3260.41,6362.38 ; IC1.15@4239.41,6100.38 4239.41,6256.37 ccw(c4140.4,6256.37) 4210.41,6326.38 ccw(c4123.5,6239.47) 4123.49,6362.38 3260.41,6362.38
NetIC1_16: IC1.16 J38.4 | length 1991.2
  Top Layer w10: J38.4@2636.41,6631.38 J38.4@2620.41,6631.38 cw(c2620.41,6589.38) 2662.41,6589.38 2662.41,6576.1 ccw(c2695.12,6576.1) 2695.12,6543.38 3072.41,6543.38 cw(c3072.41,6438.38) 3177.41,6438.38 3177.41,6423.41 ccw(c3257.44,6423.41) 3257.44,6343.37 4115.57,6343.38 cw(c4115.57,6232.71) 4193.82,6310.96 4197.41,6307.38 cw(c4156.36,6266.34) 4214.4,6266.34 IC1.16@4214.41,6100.38
NetIC6_A6: IC6.A6 J6.4 pad.1@4734.41,4114.38 | length 1264.6
  Top Layer w6: IC6.A6@3900.4,4127.48 3968.31,4127.48 3977.41,4118.38 4041.41,4118.38 4097.41,4174.38 4200.41,4174.38 4243.41,4217.38 4596.4,4217.38 4699.41,4114.38 pad.1@4734.41,4114.38 4779.41,4114.38 4822.41,4157.38 4822.41,4269.38 4859.41,4306.38 J6.4@4932.4,4306.38
NetIC6_A7: IC6.A7 J6.2 pad.1@4734.41,3996.38 | length 1185.4
  Top Layer w6: IC6.A7@3900.4,4088.17 3998.6,4088.17 4077.41,4009.38 4258.41,4009.38 4331.41,4082.38 4664.41,4082.38 4709.41,4037.38 4709.41,4021.38 pad.1@4734.41,3996.38 4791.41,3996.38 4901.41,4106.38 J6.2@4932.4,4106.38
NetIC6_C6: IC6.C6 J6.3 pad.1@4734.41,4054.38 | length 1312
  Top Layer w6: IC6.C6@3821.6,4127.48 3842.71,4106.38 4048.41,4106.38 4101.41,4159.38 4205.41,4159.38 4241.41,4195.38 4581.41,4195.38 4722.41,4054.38 pad.1@4734.41,4054.38 4786.41,4054.38 4859.41,4127.38 4859.41,4184.37 4882.41,4207.38 4931.41,4207.38 J6.3@4932.4,4206.38
NetIC6_C7: IC6.C7 J6.1 pad.1@4734.41,3936.37 | length 1489.6
  Top Layer w6: v1(3801.41,4106.38) 3819.61,4088.17 IC6.C7@3821.6,4088.17 ; pad.1@4734.41,3936.37 4810.41,3936.37 4845.41,3971.38 4845.41,3996.38 4855.41,4006.38 J6.1@4932.4,4006.38
  L3 w6: v1(3801.41,4106.38) 3942.41,4106.38 3982.41,4066.38 v1(3982.41,4003.38) 3982.41,4009.38 v1@3981.91,4009.88
  Bottom Layer w6: v1(3982.41,4003.38) 4001.41,3984.37 4267.41,3984.37 4366.41,4083.38 4669.41,4083.38 4725.41,4027.38 4748.4,4027.38 4762.41,4013.38 4762.41,3953.38 4745.41,3936.37 pad.1@4734.41,3936.37
NetIC6_L4: IC6.L4 pad.1@2845.41,5413.38 R1.2 R2.1 | length 5722.1
  Top Layer w6: IC6.L4@3506.71,4206.28 3509.3,4206.28 v1(3527.41,4224.37) ; v1(4865.41,5262.38) 4866.41,5262.38 4985.41,5143.38 4985.41,4872.37 4940.4,4827.38 4940.4,4511.38 4989.41,4462.38 4989.41,4104.37 5056.41,4037.38 5056.41,3873.38 5065.95,3863.84 R1.2@5095.41,3863.84 ; R2.1@5093.41,3746.92 R1.2@5093.41,3865.83
  L3 w6: pad.1@2845.41,5413.38 2849.41,5409.38 2849.41,5208.37 2923.41,5134.38 3264.41,5134.38 3300.41,5170.38 3393.41,5170.38 3450.41,5113.38 3450.41,4334.38 3427.91,4311.87 3427.91,4296.88 3439.41,4285.38 3466.91,4285.38 3468.91,4283.38 ; 3467.41,4284.38 3473.41,4278.38 3473.41,4253.38 3502.41,4224.37 v1(3527.41,4224.37) v1@3527.41,4224.88
  L4 w6: pad.1@2845.41,5413.38 2893.41,5461.38 4759.41,5461.38 4865.41,5355.38 v1(4865.41,5262.38)
NetIC6_P13: IC6.P13 R31.1 TP6.1 | length 1283.2
  Top Layer w6: TP6.1@2444.41,3403.38 2494.95,3453.92 R31.1@2556.86,3453.92 ; v1(3368.41,3831.38) 3388.61,3851.57 IC6.P13@3388.61,3851.87
  Bottom Layer w6: TP6.1@2435.41,3414.38 2437.41,3414.38 2664.41,3641.38 3146.41,3641.38 3259.41,3754.38 3317.41,3754.38 3368.41,3805.38 v1(3368.41,3831.38)
NetIC8_5: IC8.5 L4.1 | length 154.9
  Top Layer w30: L4.1@2739.41,1691.38 2806.41,1691.38 2813.41,1684.38 IC8.5@2891.41,1684.38
NetIC8_13: IC8.13 R119.1 R120.2 | length 520.7
  Top Layer w6: R120.2@2994.95,1437.38 2994.95,1490.49 3002.41,1497.95 3002.41,1715.38 3023.41,1736.38 IC8.13@3085.75,1736.38 3122.41,1736.38 3198.41,1660.38 R119.1@3201.86,1660.38
NetIC9_9: IC9.9 J11.9 J11.10 R3.1 R7.1 R8.1 R12.1 R15.1 R16.1 R17.1 | length 3132
  Top Layer w20: v2(4262.41,846.38) 4273.23,846.38 4326.53,899.68 IC9.9@4367.41,899.68
  Top Layer w40: J11.10@3906.41,700.38 3906.41,584.38 3912.8,577.98 3995.01,577.98 ; R12.1@3913.01,440.78 3985,440.78 ; R16.1@4039,474.98 3997,474.98 3995.01,476.98 ; R17.1@4039,577.98 3995.01,577.98 ; R15.1@4042,371.98 4024.8,371.98 3995.01,401.78 3995.01,476.98 ; R8.1@4977.01,407.78 5030.81,407.78 5037.41,414.38 5037.41,556.38 5079.41,598.38 5195.41,598.38 ; R7.1@5119.01,530.78 5119.01,584.78 ; v2(5177.41,665.38) cw(c5133.95,621.92) 5195.41,621.92 5195.41,598.38 ; R3.1@5235.01,530.78 5235.01,558.78 5195.41,598.38 ; 3995.01,476.98 3995.01,577.98
  L3 w40: J11.10@3906.41,700.38 J11.9@4006.41,700.38 ; v2(4262.41,846.38) 4029.84,846.38 4006.41,822.95 J11.9@4006.41,700.38 ; v2(5177.41,665.38) 5063.41,551.38 4082.41,551.38 4006.41,627.38 J11.9@4006.41,700.38
NetIC9_10: IC9.10 J12.2 | length 2008.4
  Top Layer w6: J12.2@3916.4,233.38 4001.41,148.38 4066.41,148.38 4233.41,315.38 4648.41,315.38 4720.41,387.38 4720.41,498.38 4704.41,514.38 4310.41,514.38 4255.41,569.38 4255.41,737.38 4279.41,761.38 4394.41,761.38 4417.41,784.38 IC9.10@4417.41,899.68
NetIC9_11: IC9.11 LED7.1 | length 392.6
  Top Layer w6: LED7.1@4367.41,571.38 4406.41,571.38 4455.41,620.38 4455.41,753.38 4467.41,765.38 IC9.11@4467.41,899.68
NetIC9_12: IC9.12 LED4.1 | length 358
  Top Layer w6: IC9.12@4517.41,899.68 4517.41,793.38 4555.41,755.38 4555.41,627.38 4522.41,594.38 LED4.1@4522.41,571.12
NetIC9_13: IC9.13 LED6.1 | length 367.9
  Top Layer w6: IC9.13@4567.41,899.68 4567.41,826.38 4653.41,740.38 4653.41,594.38 4662.41,585.38 LED6.1@4662.41,571.12
NetIC9_14: IC9.14 J8.6 | length 1201.2
  Top Layer w6: J8.6@4403.41,217.38 4405.41,219.38 4405.41,254.38 4446.41,295.38 4670.41,295.38 4867.41,492.38 4867.41,754.38 4841.41,780.38 4684.4,780.38 4617.41,847.38 IC9.14@4617.41,899.68
NetIC9_15: IC9.15 J8.4 | length 1039.9
  Top Layer w6: J8.4@4603.41,217.38 4603.41,261.38 4617.41,275.38 4692.4,275.38 4892.4,475.38 4892.4,788.38 4867.41,813.38 4695.41,813.38 4667.41,841.38 IC9.15@4667.41,899.68
NetIC9_16: IC9.16 J8.2 | length 897.4
  Top Layer w6: IC9.16@4717.41,899.68 4717.41,865.38 4742.41,840.38 4890.41,840.38 4915.41,815.38 4915.41,435.38 4803.41,323.38 J8.2@4803.41,217.38
NetIC11_1: IC11.1 IC12.3 | length 282
  Top Layer w15: IC12.3@4808.8,5686.38 4819.41,5686.38 IC12.3@4829.01,5676.76 ; IC11.1@4829.01,5929.82 IC12.3@4829.01,5676.76 ; IC12.3@4832.41,5673.38 IC12.3@4829.01,5676.76
NetIC11_3: IC11.3 R14.2 | length 202.9
  Top Layer w15: R14.2@4757.81,5980.49 cw(c4765.76,5980.49) 4760.14,5986.11 4778.41,6004.38 cw(c4795.31,5987.48) 4795.31,6011.38 4843.41,6011.38 cw(c4843.41,5972.75) 4870.72,6000.07 4876.4,5994.38 cw(c4867.25,5985.21) 4880.2,5985.21 IC11.3@4880.2,5929.82
NetIC11_5: IC11.5 R18.1 | length 61.9
  Top Layer w15: IC11.5@4908.1,6171.98 R18.1@4970,6171.98
NetIC11_7: IC11.7 R13.1 | length 213
  Top Layer w15: IC11.7@4854.61,6172.93 4854.61,6096.02 ccw(c4888.05,6096.02) 4864.4,6072.37 ccw(c4884.68,6092.66) 4884.68,6063.98 R13.1@4972.01,6063.98
NetIC11_8: IC11.8 R19.2 | length 154.9
  Top Layer w15: R19.2@4762.43,6092.38 ccw(c4762.43,6077.36) R19.2@4751.81,6087.98 4779.81,6087.98 ccw(c4779.81,6143.96) 4819.4,6104.37 ccw(c4796.2,6127.59) 4829.02,6127.59 IC11.8@4829.01,6172.93
NetIC17_3: IC17.3 R49.2 | length 187.9
  Top Layer w15: R49.2@2686.81,517.98 ccw(c2686.81,610.78) 2779.61,610.78 IC17.3@2779.61,652.93
NetIC17_5: IC17.5 R50.2 | length 69.3
  Top Layer w15: R50.2@2684.81,409.98 ccw(c2685.19,410.36) 2685.19,409.82 IC17.5@2754.02,409.82
NetIC17_7: IC17.7 R39.2 | length 90.2
  Top Layer w15: IC17.7@2805.2,409.82 2805.2,321.24 ccw(c2807.26,321.24) R39.2@2805.8,319.78
NetIC17_8: IC17.8 R38.1 | length 111.6
  Top Layer w15: IC17.8@2830.79,409.82 2844.85,409.82 ccw(c2844.85,433.38) 2868.41,433.38 cw(c2883.41,433.38) 2883.41,448.38 R38.1@2920.41,448.38
NetIC19_1: IC19.1 TR4.3 | length 230
  Top Layer w20: TR4.3@790.41,6221.38 790.41,6059.38 807.41,6042.38 IC19.1@851.41,6042.38
NetIC20_13: IC20.13 IC20.18 J37.1 J37.4 R85.1 | length 1699.6
  Top Layer w20: v1(325.41,3116.38) 445.81,3236.78 R85.1@479.01,3236.78 610.81,3236.78 687.41,3313.38 IC20.13@728.96,3313.38 ; v1(653.41,3062.38) 654.41,3063.38 IC20.18@728.96,3063.38
  Bottom Layer w20: v1(325.41,3116.38) 325.41,2993.38 298.41,2966.38 190.41,2966.38 168.41,2988.38 168.41,3229.38 205.41,3266.38 320.41,3266.38 429.41,3157.38 579.41,3157.38 653.41,3083.38 v1(653.41,3062.38)
NetIC20_15: IC20.15 IC20.17 J37.2 J37.3 R85.2 | length 1165
  Top Layer w20: J37.2@247.41,3066.38 346.41,3066.38 442,3161.98 R85.2@479.01,3161.98 625,3161.98 676.41,3213.38 IC20.15@728.96,3213.38 ; v1(571.41,3106.38) 665.41,3106.38 672.41,3113.38 IC20.17@728.96,3113.38
  Bottom Layer w20: J37.2@247.41,3066.38 247.41,3075.38 J37.3@247.41,3166.38 263.41,3182.38 350.41,3182.38 415.41,3117.38 560.41,3117.38 v1(571.41,3106.38)
NetIC21_3: IC21.3 J30.2 pad.1@547.41,2615.38 | length 1419.4
  Top Layer w5: pad.1@547.41,2615.38 557.41,2605.38 708.41,2605.38 804.38,2701.35 IC21.3@980.17,2701.35
  Bottom Layer w20: J30.2@237.41,1837.38 259.41,1837.38 306.41,1884.38 306.41,1996.38 448.81,2138.78 448.81,2556.78 507.41,2615.38 pad.1@547.41,2615.38
NetIC21_7: IC21.7 J30.3 pad.1@557.41,2423.38 | length 1355.1
  Top Layer w5: pad.1@557.41,2423.38 648.41,2423.38 824.02,2598.99 IC21.7@980.17,2598.99
  Bottom Layer w20: J30.3@237.41,1737.38 279.41,1737.38 359.41,1817.38 359.41,1977.38 496.41,2114.38 496.41,2390.38 529.41,2423.38 pad.1@557.41,2423.38
NetIC21_11: IC21.11 J29.4 | length 943.5
  Top Layer w10: IC21.11@1200.66,2522.22 1202.41,2520.48 v1(1202.41,2497.38)
  L4 w10: J29.4@332.41,2552.64 417.86,2467.18 1172.21,2467.18 v1(1202.41,2497.38)
NetIC21_12: IC21.12 J29.8 | length 1302.3
  Top Layer w20: J29.8@332.41,2395.16 378.63,2395.16 411.41,2362.38 411.41,2266.38 472.41,2205.38 828.41,2205.38 1075.41,2452.38 1248.41,2452.38 1267.41,2471.38 1267.41,2529.38 1247.41,2549.38 IC21.12@1211.41,2549.38
NetIC21_14: IC21.14 J29.12 | length 1027
  Top Layer w20: v1(547.41,2262.38) 558.41,2251.38 806.41,2251.38 1154.02,2598.99 IC21.14@1200.64,2598.99
  L3 w20: J29.12@332.41,2237.68 522.71,2237.68 v1(547.41,2262.38)
NetIC21_15: IC21.15 J29.2 | length 962.4
  Top Layer w20: v1(1127.41,2623.38) 1128.61,2624.58 IC21.15@1200.64,2624.58
  L3 w20: J29.2@332.41,2631.38 384.41,2631.38 462.41,2709.38 1085.41,2709.38 1127.41,2667.38 v1(1127.41,2623.38)
NetIC21_16: IC21.16 J29.10 | length 1006.5
  Top Layer w20: v1(1033.41,2597.38) 1041.41,2597.38 1094.2,2650.17 IC21.16@1200.64,2650.17
  L3 w20: J29.10@332.41,2316.42 423.44,2316.42 471.41,2364.38 626.41,2364.38 859.41,2597.38 v1(1033.41,2597.38)
NetIC21_18: IC21.18 J29.6 | length 962.5
  Top Layer w20: v1(1059.41,2663.38) 1097.38,2701.35 IC21.18@1200.64,2701.35
  L3 w20: J29.6@332.41,2473.9 398.93,2473.9 489.41,2564.38 583.41,2564.38 682.41,2663.38 v1(1059.41,2663.38)
NetIC22_6: IC22.6 J32.3 | length 2965.4
  Top Layer w5: IC22.6@1303.91,1532.01 1303.91,1599.88 1386.41,1682.38 1411.41,1682.38 1483.41,1754.38 v1(1545.41,1754.38)
  Bottom Layer w5: v1(1545.41,1754.38) 1545.41,1879.38 1742.41,2076.38 1851.41,2076.38 1913.41,2138.38 3485.41,2138.38 3572.41,2051.38 3572.41,1827.38 3551.41,1806.38 J32.3@3508.41,1806.38
NetIC22_7: IC22.7 J32.4 | length 3128.8
  Top Layer w5: IC22.7@1328.91,1532.01 1328.91,1567.88 1467.41,1706.38 v1(1485.41,1706.38)
  Bottom Layer w6: v1(1485.41,1706.38) 1485.41,1860.38 1728.41,2103.38 1823.41,2103.38 1884.41,2164.38 3533.41,2164.38 3633.41,2064.38 3633.41,1835.38 3508.41,1710.38 J32.4@3508.41,1706.38
NetIC22_8: IC22.8 J32.5 | length 3344.5
  Top Layer w5: IC22.8@1353.91,1532.01 1353.91,1563.88 1449.41,1659.38 v1(1481.41,1659.38)
  Bottom Layer w5: v1(1481.41,1659.38) 1480.41,1659.38 1457.41,1682.38 1457.41,1869.38 1714.41,2126.38 1804.41,2126.38 1869.41,2191.38 3546.41,2191.38 3669.41,2068.38 3669.41,1767.38 J32.5@3508.41,1606.38
NetIC22_15: IC22.15 R114.1 | length 265.5
  Top Layer w5: R114.1@1175.41,1918.83 1205.95,1918.83 1246.41,1878.38 1246.41,1840.38 1266.41,1820.38 1287.41,1820.38 1303.91,1803.87 IC22.15@1303.91,1736.74
NetIC25_2: IC25.2 OP1.4 R58.2 | length 967.2
  Top Layer w20: IC25.2@537.61,4822.09 537.61,4745.17 559.41,4723.38 747.41,4723.38 778.81,4691.98 R58.2@818.01,4691.98 818.01,4494.78 1062.41,4250.38 OP1.4@1062.41,4205.38
NetIC28_4: IC28.4 IC28.6 R90.2 | length 254.8
  Top Layer w6: R90.2@2116.95,2467.38 2131.97,2482.4 IC28.6@2190,2482.4 2190,2528.98 2198.41,2537.38 2257.41,2537.38 2264.8,2529.98 IC28.4@2264.8,2482.4
NetIC30_1: IC30.1 R95.1 R96.1 | length 237.3
  Top Layer w15: R95.1@5337.41,1513.47 5337.41,1542.38 5349.41,1554.38 5418.41,1554.38 ; R96.1@5424.41,1503.92 5424.41,1548.38
  Top Layer w20: IC30.1@5418.41,1623.88 5418.41,1554.38 5424.41,1548.38
NetIC33_5: IC33.5 R54.2 R55.1 | length 424.6
  Top Layer w5: R55.1@1195.86,1159.38 1195.86,1086.83 1170.41,1061.38 R54.2@1170.41,1020.92 1190.86,1020.92 1197.41,1014.38 1197.41,975.38 1218.41,954.38 1280.41,954.38 1332.41,1006.38 IC33.5@1374.06,1006.38
NetIC33_7: IC33.7 R102.2 R103.2 | length 228.7
  Top Layer w5: R103.2@1199.41,835.92 1242.95,835.92 1251.95,844.92 R102.2@1283.41,844.92 1283.41,887.38 1302.41,906.38 IC33.7@1374.06,906.38
NetIC33_11: IC33.11 R47.1 R48.1 | length 879.9
  Top Layer w5: v1(1470.41,1570.38) 1470.41,1596.38 1480.41,1606.38 R47.1@1504.86,1606.38 ; R48.1@1504.86,1506.38 R47.1@1504.86,1606.38 ; v1(1505.41,960.38) 1509.41,956.38 IC33.11@1590.75,956.38 ; R47.1@1505.86,1607.38 R47.1@1504.86,1606.38
  Bottom Layer w5: v1(1470.41,1570.38) 1470.41,991.38 1501.41,960.38 v1(1505.41,960.38)
NetIC33_13: IC33.13 R105.1 R106.1 | length 430.3
  Top Layer w5: R105.1@1503.86,1405.38 1503.86,1317.38 R106.1@1507.86,1313.38 1494.41,1299.92 1494.41,1094.38 1532.41,1056.38 IC33.13@1590.75,1056.38
NetIC34_1: IC34.1 IC34.3 R125.1 | length 258.9
  Top Layer w20: IC34.3@2929.9,1029.38 2893.41,1029.38 2887.41,1023.38 2887.41,962.38 2895.21,954.58 IC34.1@2929.9,954.58 3012.6,954.58 3020.41,962.38 R125.1@3033.86,962.38
NetJ5_1: J5.1 J5.2 J5.3 J5.4
NetJ5_5: J5.5 J19.5 R13.2 | length 2224.4
  Top Layer w15: J5.5@4858.41,7628.38 4858.41,7613.38 4857.41,7612.38 J19.5@4857.41,6789.38 4857.41,6622.12 ccw(c4987.15,6622.12) 4895.41,6530.38 ccw(c4946.1,6581.08) 4946.1,6509.38 4957.41,6509.38 4970.91,6509.38 ccw(c4970.91,6628.87) 5055.41,6544.38 5107.56,6596.53 cw(c5143.41,6560.68) 5143.41,6611.38 5175.97,6611.38 cw(c5175.97,6508.94) 5248.41,6581.37 cw(c5200.12,6533.09) 5268.4,6533.09 5268.4,6492.38 5268.4,6149.22 cw(c5162.57,6149.22) 5237.41,6074.38 5235.53,6072.5 cw(c5214.96,6093.07) 5214.96,6063.98 R13.2@5046.81,6063.98
NetJ8_1: J8.1 R8.2 | length 169.5
  Top Layer w20: J8.1@4903.41,217.38 4943.41,217.38 4977.01,250.98 R8.2@4977.01,332.98
NetJ8_3: J8.3 R7.2 | length 690.5
  Top Layer w20: J8.3@4703.41,217.38 4703.41,200.38 4772.4,131.38 4956.4,131.38 5053.41,228.38 5053.41,337.38 5119.01,402.98 R7.2@5119.01,455.98
NetJ8_5: J8.5 R3.2 | length 1027.9
  Top Layer w20: J8.5@4503.41,217.38 4631.41,89.38 4984.41,89.38 5101.41,206.38 5101.41,312.38 5171.41,382.38 5211.41,382.38 5235.01,405.98 R3.2@5235.01,455.98
NetJ9_1: J9.1 J9.2 J9.3 J9.4
NetJ9_5: J9.5 J34.5 R18.2 | length 2234.1
  Top Layer w15: J9.5@4268.4,7629.38 4268.4,6792.21 cw(c4261.58,6792.21) J34.5@4266.41,6787.38 4266.41,6659.32 ccw(c4348.34,6659.32) 4290.4,6601.38 4302.95,6588.83 ccw(c4364.4,6650.29) 4364.4,6563.38 4512.41,6563.38 4696.29,6563.38 cw(c4696.29,6488.26) 4749.4,6541.38 4870.56,6420.23 ccw(c4906.41,6456.07) 4906.41,6405.37 5081.41,6405.38 cw(c5081.41,6349.85) 5120.67,6389.12 5122.41,6387.38 5122.58,6387.2 ; R18.2@5044.8,6171.98 5090.64,6171.98 ccw(c5090.64,6221.14) 5125.4,6186.38 ccw(c5108.5,6203.28) 5132.4,6203.28 5132.4,6301.38 5132.4,6363.48 ccw(c5098.85,6363.48) 5122.57,6387.21
NetJ11_11: J11.11 J11.12 | length 100
  L3 w60: J11.12@3706.41,700.38 J11.11@3806.41,700.38
NetJ12_1: J12.1 R12.2 | length 209.4
  Top Layer w20: R12.2@3913.01,365.98 3913.01,321.78 3941.41,293.38 3999.41,293.38 4016.41,276.38 J12.1@4016.41,233.38
NetJ13_1: J13.1 J13.2 J13.3 J13.4
NetJ13_5: J13.5 J45.5 R19.1 | length 2217.4
  Top Layer w15: J13.5@3675.41,7627.38 J45.5@3675.41,6787.38 3780.99,6787.38 cw(c3780.99,6783.96) 3783.41,6786.38 cw(c3783.41,6520.82) 3971.19,6708.6 4034.41,6645.38 4099.69,6580.1 ccw(c4369.41,6849.82) 4369.41,6468.37 4393.17,6468.38 cw(c4393.17,6219.14) 4569.41,6395.38 cw(c4455.94,6281.91) 4616.4,6281.91 4616.41,6165.38 4616.41,6130.52 ccw(c4650.55,6130.52) 4626.4,6106.38 ccw(c4670.82,6150.79) 4670.82,6087.98 R19.1@4677,6087.98
NetJ18_5: J18.5 R39.1 | length 830.5
  Top Layer w15: R39.1@2805.8,244.98 2805.8,105.98 ccw(c2806.41,105.98) 2806.41,105.38 ccw(c2828.41,105.38) 2828.41,83.38 2866.41,83.38 ccw(c2866.41,112.38) 2895.41,112.38 2895.41,137.38 cw(c2895.41,138.38) 2894.41,138.38 2894.41,326.38 cw(c2921.41,326.38) 2921.41,353.38 3038.09,353.38 cw(c3038.09,326.06) 3057.41,345.38 3068.38,334.4 cw(c3039.37,305.38) 3080.41,305.38 3080.41,181.21 ccw(c3087.23,181.21) J18.5@3082.41,176.38
NetJ20_1: J20.1 R110.1 | length 219.9
  Top Layer w6: J20.1@2923.41,6305.38 3010.41,6305.38 3057.41,6258.38 R110.1@3057.41,6191.92
NetJ21_5: J21.5 R50.1 | length 838.2
  Top Layer w15: 2372.41,373.38 2382.05,383.02 ; J21.5@2487.41,178.38 2374.03,178.38 2327.62,178.38 ccw(c2327.62,127.17) 2291.4,163.38 2286.25,158.23 cw(c2250.41,194.08) 2250.41,143.38 2240.72,143.38 cw(c2240.72,175.52) 2217.99,152.79 2217.41,153.38 cw(c2234.3,170.28) 2210.4,170.28 2210.41,200.38 cw(c2236.96,200.38) 2218.19,219.16 2382.05,383.02 ; R50.1@2610,409.98 ccw(c2587.32,387.29) 2587.32,419.38 2477.41,419.38 2469.82,419.38 ccw(c2469.82,295.25) 2382.05,383.02
NetJ22_5: J22.5 R49.1 | length 823.1
  Top Layer w15: J22.5@1897.41,178.38 ccw(c1897.41,726.41) 2284.92,338.89 2405.41,459.38 cw(c2546.88,317.9) 2546.88,517.98 R49.1@2612,517.98
NetJ26_4: J26.4 J27.4 R59.1 | length 807.3
  Top Layer w20: J27.4@232.41,4501.38 325.41,4501.38 332.41,4508.38 v3(332.41,4671.38) 400.6,4671.38 R59.1@413,4658.98
  Bottom Layer w20: J26.4@232.41,5036.38 316.41,5036.38 332.41,5020.38 v3(332.41,4671.38)
NetJ29_14: J29.14 R43.1 TR6.3 | length 1837
  Top Layer w20: v1(1344.41,2705.38) 1349,2700.78 R43.1@1349,2657.98 1349.41,2657.58 TR6.3@1349.41,2522.38
  Bottom Layer w20: J29.14@332.41,2158.94 381.96,2158.94 404.41,2181.38 404.41,2660.39 729.78,2824.28 1114.31,2824.28 1136.41,2846.38 1280.41,2846.38 1338.41,2788.38 1338.41,2711.38 v1(1344.41,2705.38)
NetJ31_2: J31.2 R69.1 | length 729.3
  Top Layer w40: 105.41,1018.38 136.41,987.38 319.89,987.38 R69.1@364.99,1032.48 ; 105.41,1023.38 105.41,1307.38 144.41,1346.38 J31.2@243.41,1346.38
NetJ31_3: J31.3 R67.2 | length 157.1
  Top Layer w60: J31.3@243.41,1446.38 263.22,1466.19 R67.2@392.31,1466.19
NetJ33_1: J33.1 P1.9 | length 4873.9
  Top Layer w6: v1(4904.41,5267.38) 4932.4,5295.38 4978.41,5295.38 5026.41,5247.38 5026.41,4714.38 ; v3(5068.4,4712.37) 5066.41,4714.38 5026.41,4714.38 ; P1.9@5392.4,4251.38 5345.4,4298.38 5265.41,4298.38 5214.41,4247.38 5193.41,4247.38 5067.41,4247.38 5026.41,4288.37 5026.41,4714.38
  Bottom Layer w6: J33.1@2918.41,5622.38 2918.41,5642.38 3148.41,5872.37 3148.41,6104.37 3311.41,6267.38 3610.41,6267.38 3681.41,6338.38 4552.41,6338.38 4659.41,6231.38 4659.41,5824.37 4904.41,5579.38 v1(4904.41,5267.38)
NetJ38_1: J38.1 R87.2 | length 248.5
  Top Layer w10: J38.1@2920.41,6631.38 2957.41,6631.38 2989.95,6663.92 R87.2@2989.95,6829.38
NetJ41_5: J41.5 R100.2 | length 255
  Top Layer w15: R100.2@1809.01,4666.97 1818.81,4666.97 1861.41,4624.37 J41.5@1861.41,4439.38
NetJ43_2: J43.2 R133.2 | length 238
  Top Layer w10: J43.2@235.41,815.38 276.41,815.38 302.41,789.38 302.41,711.38 336.86,676.92 R133.2@370.41,676.92
NetJ43_3: J43.3 R99.1 | length 216.7
  Top Layer w10: J43.3@235.41,915.38 330.41,820.38 330.41,784.38 340.95,773.83 R99.1@372.41,773.83
NetJ44_1: J44.1 R109.1 | length 1438.9
  Top Layer w10: v1(449.41,1725.38) 461.41,1713.38 R109.1@527.86,1713.38
  Bottom Layer w5: J44.1@225.41,522.38 153.41,594.38 153.41,952.38 156.41,955.38 156.41,1048.38 331.41,1223.38 331.41,1287.38 449.41,1405.38 v1(449.41,1725.38)
NetJ44_2: J44.2 R111.1 | length 1523
  Top Layer w5: R111.1@517.86,1808.83 R111.1@517.86,1809.38
  Top Layer w10: v1(480.41,1770.38) 480.41,1796.38 493.41,1809.38 R111.1@517.86,1809.38
  Bottom Layer w5: J44.2@225.41,422.38 291.41,488.38 291.41,938.38 306.41,953.38 306.41,1030.38 362.41,1086.38 362.41,1267.38 480.41,1385.38 v1(480.41,1770.38)
NetLED1_2: LED1.2 R4.1 | length 111.1
  Top Layer w10: R4.1@2262.01,5134.78 2277,5134.78 2290.66,5121.12 LED1.2@2367.41,5121.12
NetLED2_2: LED2.2 R53.1 | length 125.6
  Top Layer w6: LED2.2@1097.14,4561.38 1187.41,4561.38 1210.8,4537.98 R53.1@1213,4537.98
NetLED3_2: LED3.2 R52.2 | length 133
  Top Layer w15: R52.2@1403.81,6667.98 1407.14,6664.64 LED3.2@1407.14,6536.37
NetLED4_2: LED4.2 R16.2 | length 543.4
  Top Layer w6: R16.2@4113.81,474.98 4171.8,474.98 4289.41,357.38 4508.4,357.38 4522.41,371.38 LED4.2@4522.41,451.64
NetLED5_2: LED5.2 R64.2 | length 203.6
  Top Layer w10: R64.2@5397.81,2933.98 5415.15,2951.32 LED5.2@5415.15,3130.38
NetLED6_2: LED6.2 R15.2 | length 651.9
  Top Layer w6: R15.2@4116.8,371.98 4201.8,371.98 4236.4,337.38 4624.41,337.38 4662.41,375.38 LED6.2@4662.41,451.64
NetLED7_2: LED7.2 R17.2 | length 305.8
  Top Layer w6: R17.2@4113.81,577.98 4184.8,577.98 4310.89,451.9 LED7.2@4367.41,451.9
NetOP1_2: OP1.2 R42.1 | length 164.8
  Top Layer w6: OP1.2@1362.41,4105.38 1454.41,4105.38 1479.01,4080.78 R42.1@1479.01,4042.78
NetR22_2: R22.2 TR1.6 | length 80
  Bottom Layer w20: R22.2@1633.95,7875.38 1633.95,7864.83 1648.41,7850.38 TR1.6@1648.41,7801.38
NetR23_2: R23.2 TR2.6 | length 96.4
  Bottom Layer w20: R23.2@1471.5,7890.38 1471.5,7857.29 1489.41,7839.38 TR2.6@1489.41,7801.38
NetR32_2: R32.2 TR3.6 | length 85.2
  Bottom Layer w20: R32.2@1312.95,7878.38 1312.95,7861.83 1330.41,7844.38 TR3.6@1330.41,7800.37
NetR33_1: R33.1 TR5.1 | length 140.6
  Top Layer w10: TR5.1@1633.64,2596.67 1670.7,2596.67 1710.01,2635.98 R33.1@1758,2635.98
NetR38_2: R38.2 TP22.1 | length 477.4
  Top Layer w15: R38.2@2995.21,448.38 3220.41,448.38 3236.41,464.38 ; 3228.41,456.38 3326.41,554.38 TP22.1@3417.41,554.38
NetR44_1: R44.1 TR5.3 TR6.1 | length 300.2
  Top Layer w10: TR6.1@1432.08,2484.98 1511,2484.98 1550.96,2524.94 ; TR5.3@1550.96,2634.08 1550.96,2548.82 1550.96,2524.94 ; R44.1@1596.24,2499.98 1575.92,2499.98 1550.96,2524.94
NetR73_1: R73.1 R133.1 | length 350
  Top Layer w10: R133.1@370.41,619.83 358.41,607.83 358.41,368.38 392.41,334.38 R73.1@437.86,334.38
NetR75_2: R75.2 TR10.6 | length 70.8
  Bottom Layer w20: R75.2@65.41,6313.92 72.26,6320.78 TR10.6@133.38,6320.78
NetR76_2: R76.2 TR13.6 | length 68.9
  Bottom Layer w20: R76.2@68.26,5839.78 TR13.6@137.16,5839.78
NetR77_2: R77.2 TR12.6 | length 78.1
  Bottom Layer w20: R77.2@62.41,5989.92 75.26,6002.78 TR12.6@135.16,6002.78
NetR78_2: R78.2 TR11.6 | length 71.8
  Bottom Layer w20: R78.2@63.41,6153.92 91.95,6153.92 96.8,6158.78 TR11.6@133.16,6158.78
NetR81_2: R81.2 TR1.1 | length 318.1
  Top Layer w6: v1(1650.41,7744.37) 1702.41,7692.38 1702.41,7586.38 1736.86,7551.92 R81.2@1788.41,7551.92
  Bottom Layer w6: TR1.1@1648.41,7706.89 1648.41,7742.38 v1(1650.41,7744.37)
NetR82_2: R82.2 TR2.1 | length 505.5
  Top Layer w6: v1(1517.41,7699.38) 1524.41,7692.38 R82.2@1524.41,7227.92
  Bottom Layer w6: TR2.1@1489.41,7706.89 1509.89,7706.89 v1(1517.41,7699.38)
NetR83_2: R83.2 TR3.1 | length 529.6
  Top Layer w6: R83.2@1117.41,7372.92 1117.41,7375.38 1165.41,7423.38 1165.41,7606.38 1259.41,7700.38 v1(1365.41,7700.38)
  Bottom Layer w6: TR3.1@1330.41,7705.89 1359.89,7705.89 v1(1365.41,7700.38)
NetR126_1: R126.1 TR10.5 | length 2915.5
  Top Layer w6: v1(1968.41,4909.38) 1968.86,4908.92 R126.1@1968.86,4852.38
  L3 w6: v1(170.41,6286.38) 170.41,6213.69 208.8,6175.3 208.8,5836.8 363.3,5682.3 1555.4,5682.3 1968.41,5269.29 v1(1968.41,4909.38)
  Bottom Layer w20: TR10.5@133.38,6283.38 167.41,6283.38 v1(170.41,6286.38)
NetR127_1: R127.1 TR11.5 | length 2835.6
  Top Layer w6: v1(1961.41,4812.38) 1972.32,4801.46 R127.1@1972.32,4763.38
  L3 w6: v1(169.41,6126.38) 190,6105.78 190,5834.5 372,5652.5 1545.6,5652.5 1939.41,5258.69 1939.41,4834.38 v1(1961.41,4812.38)
  Bottom Layer w20: TR11.5@133.16,6121.38 164.41,6121.38 v1(169.41,6126.38)
NetR128_1: R128.1 TR12.5 | length 2734
  Top Layer w6: v1(1962.41,4719.38) 1968.86,4712.92 R128.1@1968.86,4676.38
  L3 w6: v1(170.41,5968.37) 170.41,5830.89 377.3,5624 1504.9,5624 1816.2,5312.7 1816.2,5280.3 1909.41,5187.09 1909.41,4773.38 1962.41,4720.37 v1(1962.41,4719.38)
  Bottom Layer w20: TR12.5@135.16,5965.38 167.41,5965.38 v1(170.41,5968.37)
NetR218_2: R218.2 TR13.5 | length 3089
  Top Layer w6: R218.2@2079.41,4424.29 2079.41,4350.38 v1(2092.41,4337.38)
  L3 w6: v1(170.41,5802.38) 378.48,5594.3 1443.48,5594.3 1797.41,5240.37 1797.41,4773.38 1913.41,4657.38 2047.41,4657.38 2092.41,4612.38 v1(2092.41,4337.38)
  Bottom Layer w20: TR13.5@137.16,5802.38 v1(170.41,5802.38)
OE: IC6.B8 IC7.1 IC7.4 IC7.10 IC7.13 pad.1@4734.41,3760.37 R5.1 R6.1 | length 2211.5
  Top Layer w6: IC6.B8@3861,4048.78 3879.6,4067.38 3997.41,4067.38 4069.41,3995.38 4264.41,3995.38 4332.4,4063.38 4654.41,4063.38 v1(4662.41,4055.38) ; pad.1@4734.41,3760.37 4824.41,3760.37 4899.41,3685.38 4966.41,3685.38 4997.59,3654.19 4997.59,3649.56 ; IC7.10@4920.81,3565.24 4920.81,3514.6 4925.22,3510.19 ; R5.1@4932.4,3445.92 4932.4,3503.01 4925.22,3510.19 ; IC7.4@4946.41,3797.52 4946.41,3725.38 4966.41,3705.38 4997.41,3705.38 ; R6.1@5015.41,3453.92 5015.41,3488.38 4997.59,3506.19 4997.59,3508.19 ; IC7.1@5023.18,3797.52 5023.18,3714.15 5014.41,3705.38 4997.41,3705.38 ; 4925.22,3510.19 4932.04,3503.38 4992.77,3503.38 4997.59,3508.19 ; 4997.41,3705.38 4997.59,3705.19 4997.59,3649.56 ; 4997.59,3508.19 IC7.13@4997.59,3565.24 4997.59,3649.56
  Bottom Layer w6: v1(4662.41,4055.38) 4699.41,4018.38 4699.41,3795.38 pad.1@4734.41,3760.37
OPA1_OUTB: C83.2 IC22.2 IC23.6 IC23.7 IC33.4 | length 1131.2
  Top Layer w5: IC23.6@1006.1,1244.18 1062.21,1244.18 1064.41,1246.38 ; IC23.7@1006.1,1294.17 1064.2,1294.17 ; 1064.41,1278.38 1147.41,1278.38 1184.41,1241.38 1409.26,1241.38 1437.41,1213.23 1437.41,1072.38 1421.41,1056.38 IC33.4@1374.06,1056.38 ; C83.2@1091.41,1197.92 1091.41,1219.38 1064.41,1246.38 ; IC22.2@1203.91,1532.01 1203.91,1461.88 1064.41,1322.38 1064.41,1246.38
OPA2_OUTB: C86.2 IC22.1 IC24.6 IC24.7 IC33.10 | length 1823.7
  Top Layer w8: IC22.1@1178.91,1532.01 1178.91,1476.88 1117.41,1415.38 981.41,1415.38 942.41,1376.38 942.41,1048.38 1022.41,968.38 1022.41,930.38 1071.41,881.38 1071.41,745.38 1102.41,714.38 C86.2@1102.41,683.73 1137.75,683.73 1167.41,713.38 1362.41,713.38 1453.41,804.38 1453.41,849.38 1510.41,906.38 IC33.10@1590.75,906.38
  Top Layer w10: IC24.6@1006.1,749.38 1068.41,749.38 ; IC24.7@1006.1,799.37 1068.41,799.37
P1-16: IC6.A4 P1.16 pad.1@4734.41,4525.38 | length 1654.4
  Top Layer w6: IC6.A4@3900.4,4206.28 3963.51,4206.28 4021.41,4148.38 v1(4031.41,4148.38)
  L3 w6: v1(4031.41,4148.38) 4032.41,4148.38 4058.41,4174.38 4213.41,4174.38 4247.41,4208.37 4499.41,4208.37 v1(4539.41,4248.37)
  Bottom Layer w6: v1(4539.41,4248.37) 4544.41,4253.38 4544.41,4375.38 4694.41,4525.38 4769.41,4525.38 4795.41,4551.38 P1.16@5292.4,4551.38
P1-20: IC6.E4 P1.20 pad.1@4734.41,5057.38 | length 2357.9
  Top Layer w6: IC6.E4@3742.91,4206.28 3744.31,4206.28 v1(3763.41,4225.38)
  L3 w6: pad.1@4734.41,5057.38 4786.41,5005.38 4786.41,4736.37 v1(4842.41,4680.37)
  Bottom Layer w6: v1(3763.41,4225.38) 3765.74,4227.71 3765.74,4237.91 3803.21,4275.38 3826.41,4275.38 3862.41,4311.38 3862.41,4366.38 4118.41,4622.38 4118.41,4721.38 4454.41,5057.38 pad.1@4734.41,5057.38 ; v1(4842.41,4680.37) 4862.38,4660.4 5152.43,4660.4 5238.41,4746.38 5287.41,4746.38 P1.20@5292.41,4751.38
P1-21: IC6.C8 IC7.12 P1.21 pad.1@4734.41,3700.38 | length 3080.6
  Top Layer w6: IC6.C8@3821.6,4048.78 3842.01,4028.38 3993.41,4028.38 4067.41,3954.38 4271.41,3954.38 v1(4275.41,3958.38) ; pad.1@4734.41,3700.38 4842.41,3700.38 4875.41,3667.38 4920.41,3667.38 v1(4959.41,3628.38) 4972,3615.78 IC7.12@4972,3565.24 ; v1(5167.41,4312.37) 5167.41,4712.37 5236.4,4781.38 5236.4,4782.38 5256.41,4802.38 5343.41,4802.38 P1.21@5392.4,4851.38
  Bottom Layer w6: v1(4275.41,3958.38) 4365.41,4048.37 4627.41,4048.37 4680.41,3995.38 4680.41,3755.38 4734.41,3701.38 pad.1@4734.41,3700.38 ; v1(4959.41,3628.38) 4959.41,3630.38 5075.41,3746.38 5075.41,3848.37 5165.41,3938.38 5165.41,4064.37 5131.7,4098.09 5131.7,4213.67 5167.41,4249.38 v1(5167.41,4312.37)
PKTEND: IC1.46 IC6.G5 pad.1@4025.41,5413.38 | length 1969.7
  Top Layer w6: IC6.G5@3664.2,4166.88 3664.91,4166.88 v1(3684.41,4186.38) ; v1(4339.31,5640.28) 4339.31,5731.9 IC1.46@4339.41,5732
  L3 w6: v1(3684.41,4186.38) 3703.51,4205.48 3703.51,4301.48 3830.41,4428.38 3830.41,4501.38 v1(3899.41,4570.38) ; pad.1@4025.41,5413.38 4067.41,5455.38 4218.11,5455.38 4339.31,5576.58 v1(4339.31,5640.28)
  Bottom Layer w6: v1(3899.41,4570.38) 3893.41,4576.37 3893.41,4906.38 3856.41,4943.38 3856.41,5124.38 3857.41,5124.38 4025.41,5292.38 pad.1@4025.41,5413.38
R26-2: IC6.R3 J17.9 R26.2 | length 1374.4
  Top Layer w6: J17.9@2279.41,4453.38 2458.41,4453.38 2558.95,4553.92 R26.2@2558.95,4566.38 2735.41,4566.38 v1(2736.41,4565.38) ; v1(3049.41,4561.38) 3050.41,4562.38 3199.41,4562.38 3219.41,4542.38 3219.41,4414.38 3279.41,4354.38 3279.41,4284.38 3300.41,4263.38 3331.41,4263.38 IC6.R3@3349.21,4245.58
  Bottom Layer w6: v1(2736.41,4565.38) 2741.41,4560.37 3048.41,4560.37 v1(3049.41,4561.38)
R27-2: IC6.T11 J17.8 R27.2 | length 1612.5
  Top Layer w6: J17.8@2279.41,4353.38 2318.41,4392.37 2482.41,4392.37 2514.95,4359.84 R27.2@2552.41,4359.84 ; v1(2746.41,4009.38) 2746.41,3945.38 2851.41,3840.37 3206.41,3840.37 3296.71,3930.68 IC6.T11@3309.8,3930.68
  Bottom Layer w6: J17.8@2286.41,4346.38 2309.41,4346.38 2648.81,4006.98 2744.01,4006.98 v1(2746.41,4009.38)
R33-2: IC6.K15 pad.1@2960.41,2822.38 R33.2 | length 2667.3
  Top Layer w6: R33.2@1832.81,2635.98 1849.21,2652.38 2752.41,2652.38 2878.41,2778.38 v1(2883.41,2778.38) ; v1(3523.41,3663.38) 3565.81,3705.78 3565.81,3753.38 IC6.K15@3546.01,3773.17
  L3 w6: v1(2883.41,2778.38) 2916.41,2778.38 pad.1@2960.41,2822.38 3125.41,2987.38 3429.41,2987.38 3599.41,3157.38 3599.41,3607.38 3543.41,3663.38 v1(3523.41,3663.38)
R36-1: IC6.H14 IC17.1 pad.1@3256.41,2822.38 R36.1 R37.1 | length 4497.9
  Top Layer w6: v1(3604.41,3792.37) 3624.61,3812.58 IC6.H14@3624.8,3812.58
  Top Layer w15: 2837.85,652.93 2895.58,652.93 ccw(c2895.58,680.41) R36.1@2915,660.98 ; R37.1@2905,560.98 2904.41,561.58 2904.41,636.24 2905,636.84 cw(c2939.14,636.84) R36.1@2915,660.98 ; pad.1@3256.41,2822.38 3256.41,2701.35 cw(c3215.44,2701.35) 3244.41,2672.38 3216.01,2643.98 cw(c3187.99,2672.01) 3187.99,2632.38 3126.82,2632.38 ccw(c3126.82,2628.96) 3124.41,2631.38 ccw(c3124.41,2549.3) 3066.36,2607.34 3065.41,2606.38 ccw(c3113.69,2558.09) 3045.4,2558.09 3045.41,2351.79 ccw(c3048.82,2351.79) 3046.41,2349.38 ccw(c3065.72,2349.38) 3052.07,2335.72 3126.41,2261.38 ccw(c3189.18,2324.15) 3189.18,2235.38 3417.85,2235.38 cw(c3417.85,2197.82) 3444.4,2224.38 3534.64,2134.15 cw(c3441.04,2040.55) 3573.41,2040.55 3573.41,1044.38 cw(c3464.77,1044.38) 3541.59,967.56 3344.41,770.38 cw(c3315.44,799.35) 3315.44,758.38 2959.96,758.38 ccw(c2959.96,720.82) 2933.4,747.38 ccw(c2977.83,702.95) 2915,702.95 R36.1@2915,660.98
  Bottom Layer w6: 3581.41,3724.38 3581.41,3773.38 3600.41,3792.37 v1(3604.41,3792.37)
  Bottom Layer w20: pad.1@3256.41,2822.38 3563.12,3129.09 ccw(c3492.41,3199.8) 3592.41,3199.8 3592.41,3713.38 3581.41,3724.38
R98-1: IC6.R5 IC31.1 pad.1@2137.41,4830.38 R97.2 R98.1 | length 3064.5
  Top Layer w6: 3138.41,4407.38 3163.41,4407.38 3242.41,4328.37 3242.41,4197.38 3292.41,4147.38 3329.71,4147.38 IC6.R5@3349.21,4166.88
  Top Layer w15: R97.2@1655.01,5068.98 1666.01,5057.98 1666.01,5016.98 ; R98.1@1666.01,4948.78 1666.01,5016.98 ; IC31.1@1739.02,5004.82 1739.02,5012.76 1734.8,5016.98 1666.01,5016.98 ; 3138.41,4407.38 2931.06,4407.38 cw(c2931.06,4421.03) 2921.41,4411.38 cw(c2943.34,4433.32) 2912.32,4433.32 2912.32,4514.52 ccw(c2895.55,4514.52) 2907.41,4526.38 ccw(c2868.78,4487.75) 2868.78,4542.38 2830.41,4542.38 cw(c2830.41,4583.42) 2801.38,4554.4 2767.41,4588.38 ccw(c2697.39,4518.37) 2697.39,4617.38 2302.83,4617.38 cw(c2302.83,4719.8) 2230.41,4647.38 cw(c2285.93,4702.9) 2207.41,4702.9 2207.41,4730.38 ccw(c2134.98,4730.38) 2186.19,4781.59 pad.1@2137.41,4830.38 cw(c2137.41,4871.42) 2108.38,4842.4 2057.41,4893.38 cw(c2214.33,5050.3) 1992.4,5050.3 1992.41,5214.38 ccw(c1893.43,5214.38) 1963.42,5284.37 1947.41,5300.38 ccw(c1901.53,5254.51) 1901.53,5319.38 1736.59,5319.38 ccw(c1736.59,5227.2) 1671.41,5292.38 1599.4,5220.38 1599.4,5045.45 ccw(c1616.48,5045.45) 1604.41,5033.38 ccw(c1644,5072.97) 1644,5016.98 1666.01,5016.98
R128-2: IC6.T6 pad.1@2137.41,4593.38 R128.2 | length 1511.2
  Top Layer w6: R128.2@2025.95,4676.38 2054.41,4676.38 pad.1@2137.41,4593.38 ; v1(2680.41,4241.38) 2753.41,4168.37 3250.41,4168.37 3291.3,4127.48 IC6.T6@3309.8,4127.48
  L3 w6: pad.1@2137.41,4593.38 2229.41,4501.38 2419.41,4501.38 2679.41,4241.38 v1(2680.41,4241.38)
R130-2: IC6.P1 pad.1@2551.41,5416.37 R130.2 | length 3383.9
  Top Layer w6: R130.2@2384.41,6637.83 2384.41,6593.38 2264.41,6473.38 2264.41,5597.38 2374.41,5487.38 2437.41,5487.38 2473.41,5451.38 2516.41,5451.38 pad.1@2551.41,5416.37 ; v1(3387.41,4376.37) 3388.61,4375.18 IC6.P1@3388.61,4324.38
  L3 w6: pad.1@2551.41,5416.37 2551.41,5224.37 2681.41,5094.38 3261.41,5094.38 3305.41,5138.38 3375.41,5138.38 3412.41,5101.38 3412.41,4395.38 3393.41,4376.37 v1(3387.41,4376.37)
RTC_CLK: IC32.1 P1.6 | length 2121.9
  Top Layer w6: IC32.1@4790.41,2294.36 4790.41,2364.38 4829.41,2403.38 5056.41,2403.38 5127.41,2474.38 5127.41,3451.38 5175.41,3499.38 5175.41,3770.38 5207.41,3802.38 5207.41,4007.38 5247.41,4047.38 5288.4,4047.38 P1.6@5292.4,4051.38
RTC_SDA: IC32.4 P1.4 | length 2323.8
  Top Layer w6: IC32.4@4640.41,2269.38 4640.41,2217.38 4669.41,2188.38 4814.41,2188.38 4851.41,2225.38 4851.41,2343.38 4892.4,2384.38 5105.41,2384.38 5160.41,2439.38 5160.41,3460.38 5192.41,3492.38 5192.41,3759.38 5236.4,3803.38 5236.4,3895.38 P1.4@5292.4,3951.38
SD: IC6.E6 J20.4 P1.38 pad.1@4734.41,4290.38 | length 6427.4
  Top Layer w6: v1(3723.41,4106.38) 3742.91,4125.88 IC6.E6@3742.91,4127.48 ; v1(4695.41,4148.38) 4695.41,4251.38 pad.1@4734.41,4290.38 ; v1(5100.4,4399.38) 5135.41,4434.38 5135.41,5164.38 5178.41,5207.38 v1(5178.41,5209.38)
  Bottom Layer w6: J20.4@2623.41,6305.38 2623.41,6392.37 2686.41,6455.38 2908.41,6455.38 2976.41,6523.38 4709.41,6523.38 5006.41,6226.38 5006.41,5935.38 5212.4,5729.38 5212.4,5728.37 5289.41,5651.38 P1.38@5279.41,5661.38 ; v1(3723.41,4106.38) 3741.41,4088.37 3821.41,4088.37 3837.41,4104.37 4027.41,4104.37 4095.41,4172.38 4674.41,4172.38 4695.41,4151.38 v1(4695.41,4148.38) ; pad.1@4734.41,4290.38 4759.41,4290.38 4816.41,4347.38 4816.41,4394.38 4889.41,4467.38 5019.41,4467.38 5087.41,4399.38 v1(5100.4,4399.38) ; v1(5178.41,5209.38) 5178.41,5435.38 5218.41,5475.38 5218.41,5635.38 5234.41,5651.38 P1.38@5292.4,5651.38
SERIAL_EXP_RX: IC6.M13 OP2.1 pad.1@2134.41,3236.38 | length 2610.2
  Top Layer w6: OP2.1@1361.41,3590.38 1454.41,3590.38 1815.41,3229.38 2127.41,3229.38 pad.1@2134.41,3236.38 ; IC6.M13@3467.3,3851.87 3467.3,3851.48 v1(3487.41,3831.38)
  L3 w6: pad.1@2134.41,3236.38 2598.41,3236.38 v1(2604.41,3230.38)
  Bottom Layer w6: v1(2604.41,3230.38) 2611.41,3230.38 2754.41,3373.38 3046.41,3373.38 3218.41,3545.38 3218.41,3579.38 3250.41,3611.38 3321.41,3611.38 3455.41,3745.38 3455.41,3786.38 3487.41,3818.38 v1(3487.41,3831.38)
SERIAL_EXP_TX: IC6.T14 pad.1@2137.41,3355.38 R42.2 | length 2567
  Top Layer w6: R42.2@1479.01,3967.98 1479.01,3616.78 1815.41,3280.38 2078.41,3280.38 2137.41,3339.38 pad.1@2137.41,3355.38 2303.41,3355.38 2410.41,3462.38 2473.41,3462.38 2628.41,3617.38 2997.41,3617.38 3032.41,3652.38 3175.41,3652.38 3216.41,3693.38 3216.41,3720.37 3256.41,3760.37 3257.6,3760.37 IC6.T14@3309.8,3812.58
SHDN#: IC6.E13 IC8.3 IC26.4 pad.1@4140.4,2822.38 | length 6123.7
  Top Layer w6: IC8.3@2869.06,1786.38 2927.41,1786.38 v1(2929.41,1788.38) ; IC6.E13@3742.91,3851.87 3764.4,3830.38 v1(3801.41,3830.38)
  Top Layer w20: v1(2794.41,695.38) 2796.41,697.38 IC26.4@2796.41,754.58
  Bottom Layer w6: v1(2794.41,695.38) 2878.41,695.38 2943.41,630.38 3437.41,630.38 3449.41,642.38 3449.41,919.38 3594.41,1064.38 3594.41,1560.38 ; v1(2929.41,1788.38) 2929.41,1792.38 2963.41,1826.38 3308.41,1826.38 3368.41,1766.38 3368.41,1650.38 3462.41,1556.38 3590.41,1556.38 3594.41,1560.38 ; v1(3801.41,3830.38) 3831.41,3830.38 3988.4,3673.38 4228.4,3673.38 4274.41,3627.38 4274.41,3358.38 4235.41,3319.38 4235.41,3100.38 4140.4,3005.38 4140.4,2644.38 4046.41,2550.38 4046.41,2476.38 4097.41,2425.38 4292.4,2425.38 4387.41,2330.38 4387.41,2178.38 4338.41,2129.38 4162.41,2129.38 3594.41,1561.38 3594.41,1560.38
SLRD: IC1.8 IC6.E1 pad.1@4203.41,5413.38 | length 2064.3
  Top Layer w6: IC6.E1@3742.91,4324.38 3742.91,4333.88 3816.41,4407.38 3816.41,4679.38 3963.41,4826.38 3963.41,5008.37 4014.41,5059.38 v1(4016.41,5059.38) ; v1(4414.41,5993.38) IC1.8@4414.41,6100.38
  L3 w6: v1(4016.41,5059.38) 4016.41,5062.38 4166.41,5212.38 4166.41,5376.37 pad.1@4203.41,5413.38 4203.41,5420.38 4357.31,5574.28 4357.31,5649.03 4346.51,5659.83 4346.51,5912.48 4414.41,5980.38 v1(4414.41,5993.38)
SLWR: IC1.9 IC6.H1 pad.1@3613.41,5413.38 | length 2334.7
  Top Layer w6: v1(3624.41,4345.38) 3624.8,4344.98 IC6.H1@3624.8,4324.38 ; v1(4384.41,6033.38) 4389.41,6038.38 IC1.9@4389.41,6100.38
  Bottom Layer w6: v1(3624.41,4345.38) 3624.41,5396.86 3613.41,5407.86 3613.41,5483.38 3714.41,5584.37 3995.41,5584.37 4081.41,5670.38 4081.41,5768.37 4164.4,5851.38 4280.41,5851.38 4384.41,5955.38 4384.41,6009.38 v1(4384.41,6033.38)
SPI_CK: IC6.P12 IC18.6 IC22.19 pad.1@2137.41,3590.38 | length 4775.2
  Top Layer w5: v1(1150.41,1826.38) 1203.91,1772.87 IC22.19@1203.91,1736.74
  Top Layer w6: IC18.6@1869.61,3699.82 1869.61,3768.58 1895.41,3794.38 1969.41,3794.38 1995.41,3768.37 1995.41,3714.38 2036.41,3673.38 2036.41,3634.38 2090.41,3580.38 2127.41,3580.38 pad.1@2137.41,3590.38 ; v1(3368.41,3871.38) 3388.31,3891.28 IC6.P12@3388.61,3891.28
  L3 w6: pad.1@2137.41,3590.38 2160.41,3567.38 2459.41,3567.38 2645.41,3753.38 3320.41,3753.38 3388.61,3821.58 3388.61,3851.57 3368.8,3871.38 v1(3368.41,3871.38)
  Bottom Layer w6: v1(1150.41,1826.38) 1137.41,1839.38 1137.41,2079.38 1084.41,2132.38 1084.41,2399.38 1134.01,2448.98 1310.01,2448.98 1327.41,2466.38 1832.41,2466.38 1882.21,2516.18 1882.21,3488.18 1983.41,3589.38 2136.41,3589.38 pad.1@2137.41,3590.38
SPI_MISO: IC6.R14 IC18.2 pad.1@2134.41,3296.38 R114.2 R115.2 | length 4302
  Top Layer w5: R114.2@1175.41,1975.92 1183.86,1984.38 1412.91,1984.38 1537.41,2108.88 v1(1537.41,2158.38)
  Top Layer w6: IC18.2@1895.2,3942.94 1895.2,3873.17 1737.41,3715.38 1737.41,3525.38 1873.95,3388.83 R115.2@1923.41,3388.83 1927.95,3388.83 v1(1998.41,3318.38)
  Top Layer w10: v1(3328.41,3791.38) 3349.21,3812.17 IC6.R14@3349.21,3812.58
  Bottom Layer w6: v1(1537.41,2158.38) 1537.41,2175.38 1688.41,2326.38 1826.41,2326.38 1990.41,2490.38 1990.41,3307.86 1998.41,3315.86 v1(1998.41,3318.38) 2039.02,3318.38 2061.02,3296.38 2209.41,3296.38 2574.41,3661.38 3082.41,3661.38 3148.41,3727.38 3206.41,3727.38 3257.41,3778.38 3315.41,3778.38 v1(3328.41,3791.38)
SPI_MOSI: IC6.M12 IC18.5 IC22.17 pad.1@2137.41,3415.38 | length 4666.7
  Top Layer w5: v1(1200.41,1845.38) 1200.41,1829.38 1254.41,1775.38 IC22.17@1254.41,1751.38
  Top Layer w6: IC18.5@1844.02,3699.82 1844.02,3677.99 1826.41,3660.38 1803.41,3660.38 1759.41,3616.38 1759.41,3553.38 1798.41,3514.38 1982.41,3514.38 2081.41,3415.38 pad.1@2137.41,3415.38 ; IC6.M12@3467.3,3891.28 3487.21,3871.38 v1(3487.41,3871.38)
  L3 w6: pad.1@2137.41,3415.38 2189.41,3415.38 2266.41,3492.38 2750.41,3492.38 v1(2784.41,3458.38)
  Bottom Layer w6: v1(1200.41,1845.38) 1200.41,1957.38 1256.41,2013.38 1440.41,2013.38 1499.41,2072.38 1499.41,2191.38 1549.41,2241.38 1549.41,2296.38 1613.41,2360.38 1808.41,2360.38 1947.7,2499.67 1947.7,3332.67 1967.41,3352.38 2025.41,3352.38 2088.41,3415.38 pad.1@2137.41,3415.38 ; v1(2784.41,3458.38) 2861.41,3458.38 2897.41,3494.38 3136.41,3494.38 3198.41,3556.38 3198.41,3625.38 3234.41,3661.38 3304.41,3661.38 3369.41,3726.38 3410.41,3726.38 3433.41,3749.38 3433.41,3791.38 3467.41,3825.38 3467.41,3854.38 3484.41,3871.38 v1(3487.41,3871.38)
SRAM_CS#: IC6.R12 IC18.1 pad.1@2137.41,3650.38 | length 1766.8
  Top Layer w6: IC18.1@1920.79,3942.94 1920.79,3898.76 1920.79,3895.99 2020.41,3796.38 2020.41,3740.38 2110.41,3650.38 pad.1@2137.41,3650.38 ; v1(3328.41,3871.38) 3348.31,3891.28 IC6.R12@3349.21,3891.28
  Bottom Layer w6: pad.1@2137.41,3650.38 2158.41,3650.38 2227.41,3581.38 2389.41,3581.38 2564.41,3756.38 3177.41,3756.38 3292.41,3871.38 v1(3328.41,3871.38)
SRAM_HOD#: IC6.N12 IC18.7 pad.1@2137.41,3533.38 | length 1973.3
  Top Layer w6: IC18.7@1895.2,3699.82 1895.2,3750.17 1906.41,3761.38 1954.41,3761.38 1977.41,3738.38 1977.41,3588.38 2044.41,3521.38 2125.41,3521.38 pad.1@2137.41,3533.38 ; IC6.N12@3427.91,3891.28 3427.91,3890.88 v1(3447.41,3871.38)
  L3 w6: pad.1@2137.41,3533.38 2142.41,3528.38 v1(2604.41,3528.38)
  Bottom Layer w6: v1(2604.41,3528.38) 2687.41,3611.38 3141.41,3611.38 3268.41,3738.38 3317.41,3738.38 3447.41,3868.38 v1(3447.41,3871.38)
SRAM_SIO2: IC6.T12 IC18.3 pad.1@2137.41,3708.38 | length 1901.4
  Top Layer w6: IC18.3@1869.61,3942.94 1869.61,3976.58 1874.41,3981.38 1984.41,3981.38 2077.41,3888.37 2077.41,3744.37 2113.41,3708.38 pad.1@2137.41,3708.38 2140.41,3708.38 2182.41,3666.38 2182.41,3601.38 2213.41,3570.38 2547.41,3570.38 2644.41,3667.38 2860.41,3667.38 2928.41,3735.38 3153.91,3735.38 IC6.T12@3309.8,3891.28
TCK: IC6.C14 IC7.8 J7.9 | length 1776.9
  Top Layer w6: IC6.C14@3821.6,3812.58 3821.6,3803.18 3840.41,3784.37 3842.41,3782.38 v1(3842.41,3753.38) ; v1(4829.41,3567.38) 4831.55,3565.24 IC7.8@4869.63,3565.24
  L3 w6: v1(4233.41,3525.38) 4389.41,3525.38 4485.44,3621.42 J7.9@4523.67,3621.42
  Bottom Layer w6: v1(3842.41,3753.38) 3876.4,3753.38 3980.4,3649.38 4181.41,3649.38 4252.4,3578.38 4252.4,3541.38 4236.4,3525.38 v1(4233.41,3525.38) ; J7.9@4523.67,3621.42 4485.44,3621.42 4448.41,3584.38 4448.41,3416.38 4479.41,3385.38 4651.41,3385.38 4685.41,3419.38 4685.41,3528.38 4710.41,3553.38 4817.41,3553.38 4829.41,3565.38 v1(4829.41,3567.38)
TDI: IC6.C12 IC7.11 J7.5 | length 1536.2
  Top Layer w6: IC6.C12@3821.6,3891.28 3821.6,3889.18 v1(3840.41,3870.38) ; v1(4942.41,3526.38) 4946.41,3530.38 IC7.11@4946.41,3565.24
  L3 w6: v1(4178.41,3723.38) 4405.78,3723.38 4461.3,3778.9 J7.5@4523.67,3778.9 4523.67,3791.64 4548.45,3816.42 4656.36,3816.42 4686.41,3786.38 4885.41,3786.38 4954.41,3717.38 4954.41,3689.38 4931.41,3666.38 4931.41,3608.38 4942.41,3597.38 v1(4942.41,3526.38)
  Bottom Layer w6: v1(3840.41,3870.38) 3873.41,3837.38 3946.41,3837.38 4060.4,3723.38 v1(4178.41,3723.38)
TDO: IC6.E14 IC7.2 J7.7 | length 2339.5
  Top Layer w6: v1(3723.41,3831.38) 3742.21,3812.58 IC6.E14@3742.91,3812.58 ; v1(4994.41,3745.38) 4997.59,3748.56 IC7.2@4997.59,3797.52
  L3 w6: v1(4225.41,3564.38) 4384.41,3564.38 4520.18,3700.16 J7.7@4523.67,3700.16
  Bottom Layer w6: v1(3723.41,3831.38) 3732.4,3822.38 3732.4,3789.38 3951.41,3570.38 4217.41,3570.38 4223.41,3564.38 v1(4225.41,3564.38) ; J7.7@4523.67,3700.16 4482.62,3700.16 4412.4,3770.38 4412.4,3994.38 4438.41,4020.38 4601.41,4020.38 4657.41,3964.38 4657.41,3725.38 4711.41,3671.38 4753.41,3671.38 4827.41,3745.38 v1(4994.41,3745.38)
TMS: IC6.A15 IC7.6 J7.11 | length 1397.1
  Top Layer w6: IC6.A15@3900.4,3773.17 3913.6,3773.17 3939.41,3747.38 3939.41,3707.38 4008.41,3638.38 4008.41,3528.38 4033.41,3503.38 4154.41,3503.38 v1(4166.41,3515.38) ; IC7.6@4895.23,3797.52 4895.23,3736.56 v1(4912.41,3719.38)
  L3 w6: v1(4166.41,3515.38) 4167.41,3515.38 4180.4,3502.38 4425.41,3502.38 4465.7,3542.68 J7.11@4523.67,3542.68 4561.19,3580.21 4684.23,3580.21 4713.41,3609.38 4802.41,3609.38 v1(4912.41,3719.38)
USB_DEVICE_INT#: IC1.41 IC6.H4 pad.1@3731.41,5413.38 | length 2201
  Top Layer w6: IC6.H4@3624.8,4206.28 3627.3,4206.28 v1(3646.41,4225.38) ; v1(4203.41,5800.37) 4214.41,5789.38 IC1.41@4214.41,5740.38
  L3 w6: v1(3646.41,4225.38) 3647.41,4225.38 3666.41,4244.38 3666.41,4324.38 3703.51,4361.48 3732.5,4361.48 3799.41,4428.38 3799.41,4686.38 3729.41,4756.38 3729.41,5242.38 v1(3799.41,5312.37)
  Bottom Layer w6: v1(3799.41,5312.37) 3799.41,5338.38 3731.41,5406.38 3731.41,5439.38 3822.41,5530.38 4111.41,5530.38 4178.41,5597.38 4178.41,5773.38 4203.41,5798.38 v1(4203.41,5800.37)
USB_DEVICE_READY: IC1.40 IC6.H2 pad.1@3671.41,5413.38 | length 1897.2
  Top Layer w6: IC6.H2@3624.8,4284.98 3643.41,4303.58 3643.41,4355.38 3582.41,4416.37 3582.41,4592.37 3641.41,4651.38 3641.41,4895.38 3654.41,4908.38 v1(3654.41,4948.38) ; pad.1@3671.41,5413.38 3749.41,5491.38 3941.41,5491.38 4032.41,5582.38 4123.41,5582.38 4162.41,5621.38 4162.41,5638.38 4189.41,5665.38 IC1.40@4189.41,5732
  Bottom Layer w6: v1(3654.41,4948.38) 3671.41,4965.38 pad.1@3671.41,5413.38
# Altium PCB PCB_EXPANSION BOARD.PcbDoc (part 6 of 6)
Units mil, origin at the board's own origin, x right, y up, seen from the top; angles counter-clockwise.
Board outline 5512.34 x 7953.29 mil, 6 copper layers (Top Layer, L2, L3, L4, L5, Bottom Layer); 420 components, 365 nets, 1860 pads, 895 vias.
Unrouted connection lines stored in the file: 9.

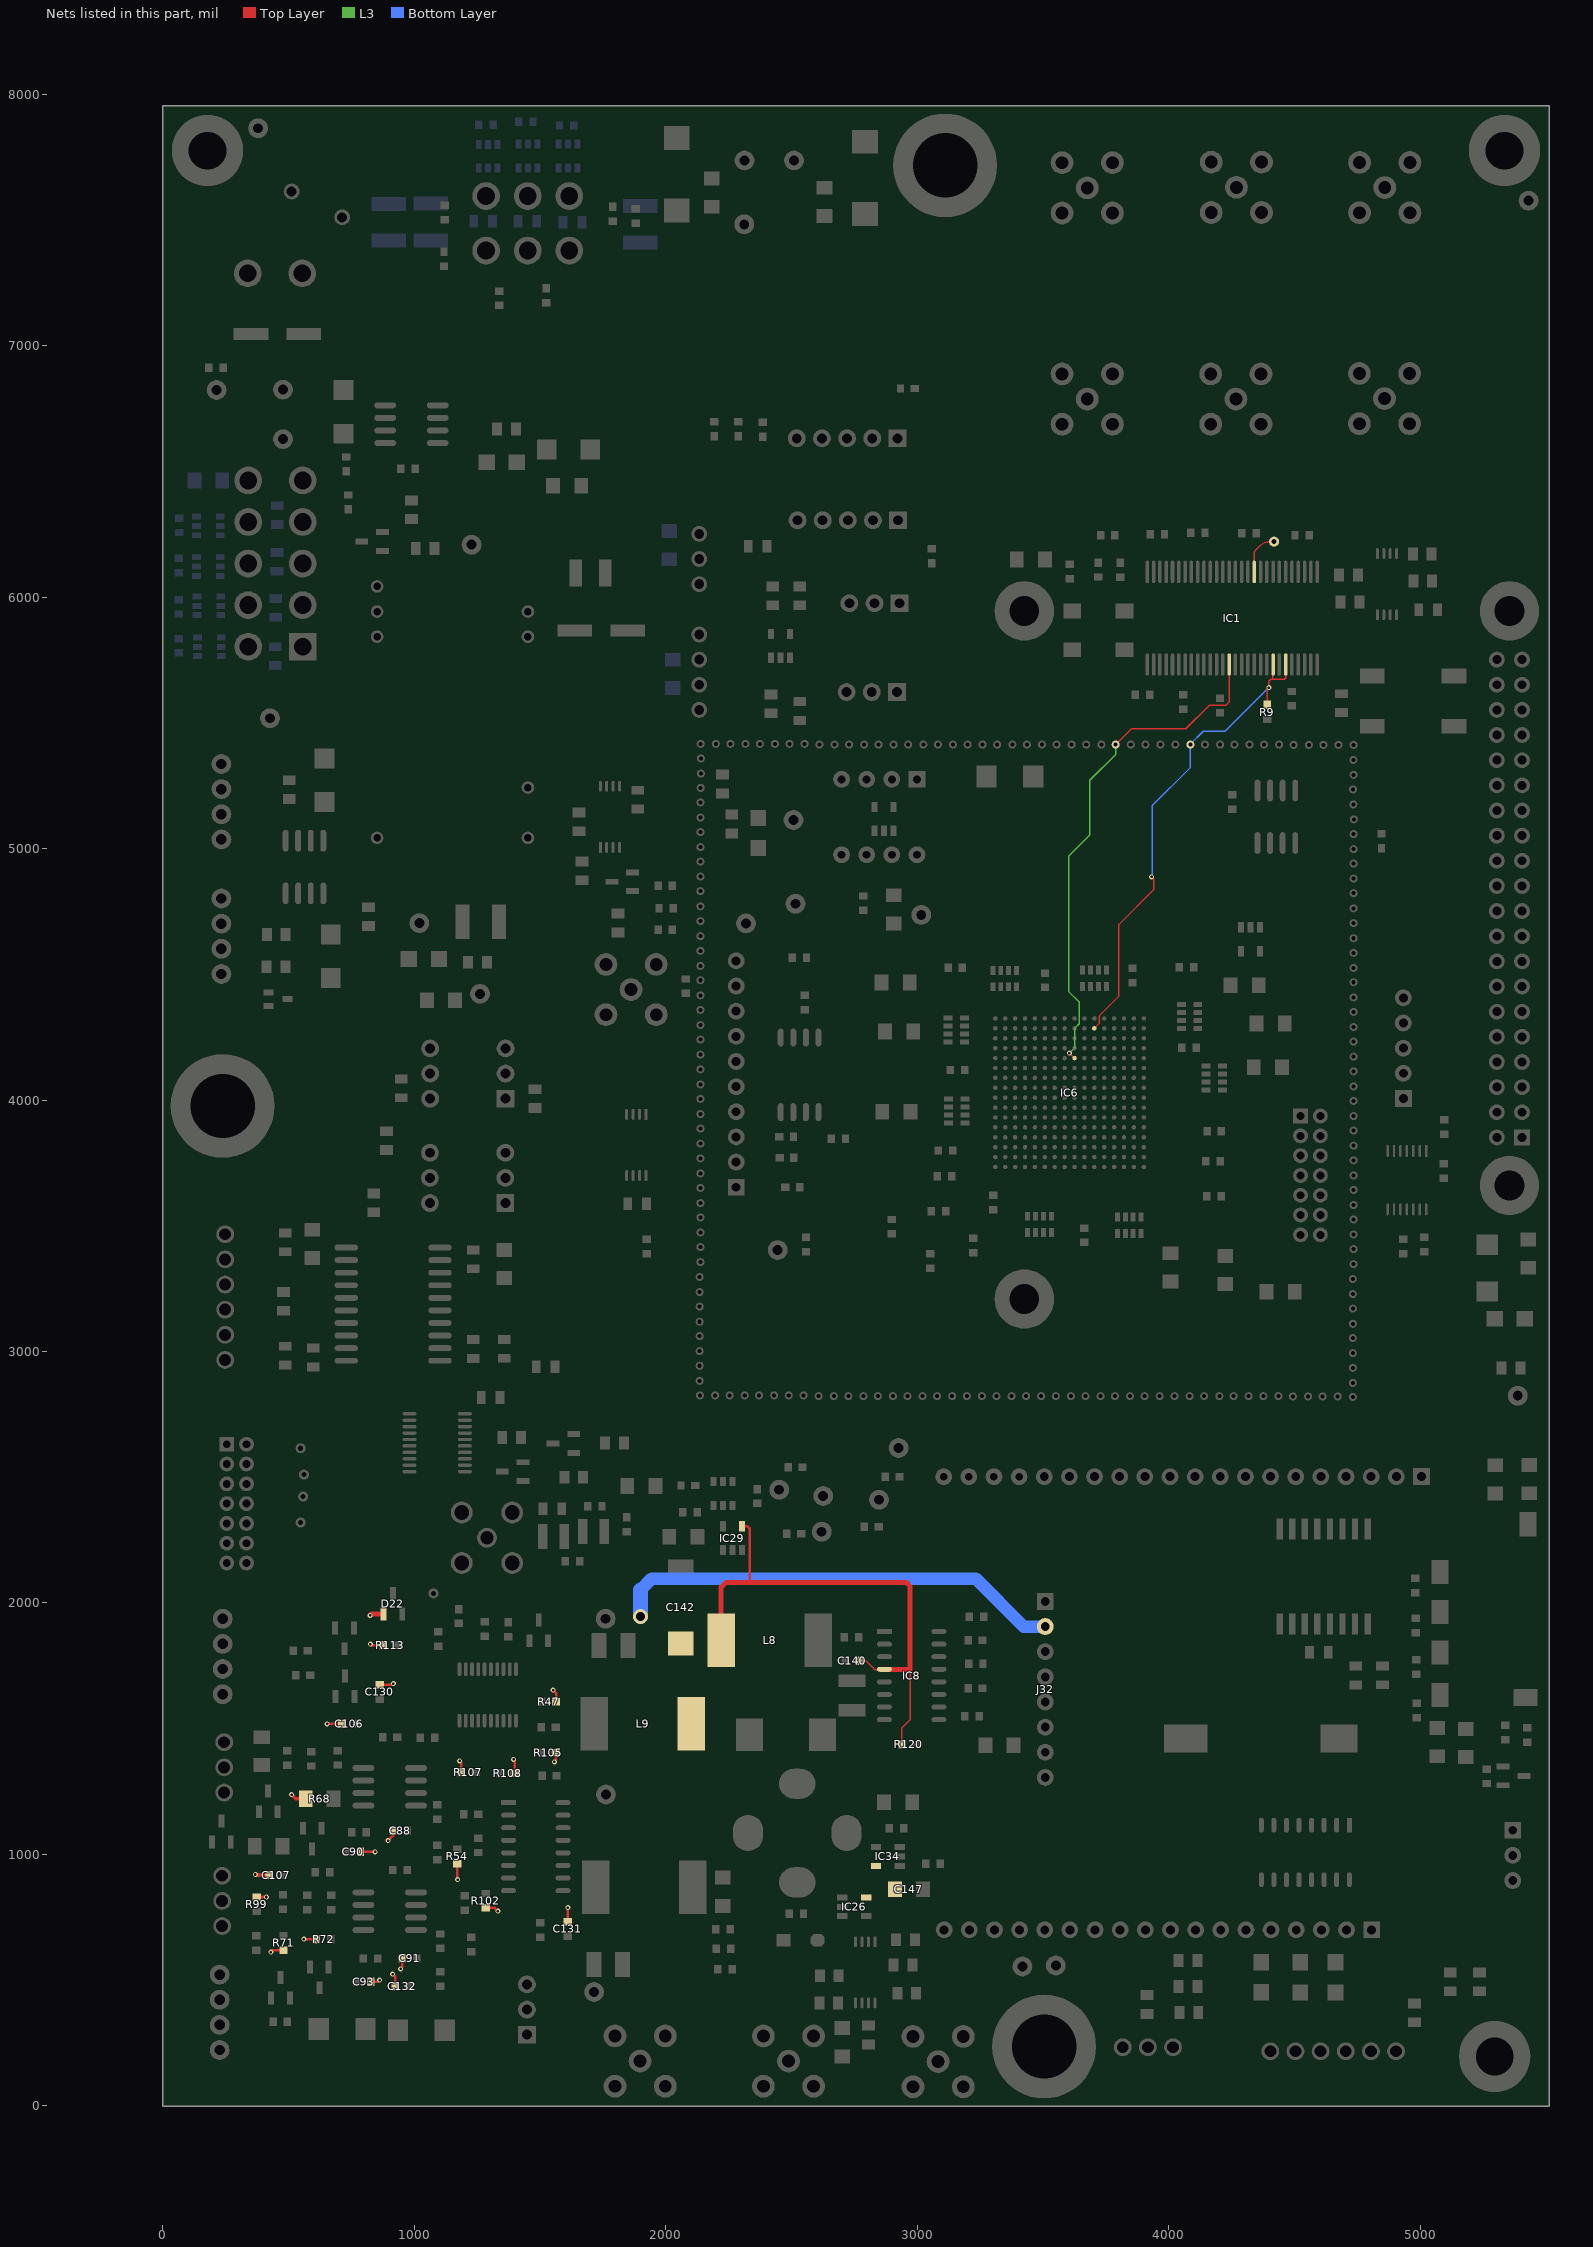
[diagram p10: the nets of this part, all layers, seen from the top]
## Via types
v1: diameter 20, hole 10, Top Layer to Bottom Layer, tented both sides, 808 vias
v2: diameter 60, hole 35, Top Layer to Bottom Layer, 47 vias
v3: diameter 42, hole 24, Top Layer to Bottom Layer, 32 vias
v4: diameter 125.98/125.98/125.98/125.98/125.98/125.98 (per signal layer), hole 125.98, Top Layer to Bottom Layer, 6 vias
v5: diameter 51.18, hole 51.18, Top Layer to Bottom Layer, 2 vias

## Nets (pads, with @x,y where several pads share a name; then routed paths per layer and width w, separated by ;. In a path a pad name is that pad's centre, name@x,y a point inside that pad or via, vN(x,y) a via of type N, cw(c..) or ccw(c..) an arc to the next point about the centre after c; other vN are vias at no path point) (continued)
USB_DEVICE_RSET#_WAKUP: IC1.49 IC1.51 IC6.F2 pad.1@4085.41,5413.38 R9.2 | length 1991
  Top Layer w6: IC6.F2@3703.51,4284.98 3722.41,4303.87 3722.41,4334.38 3801.41,4413.38 3801.41,4698.38 3939.41,4836.38 3939.41,4879.38 v1(3931.41,4887.38) ; R9.2@4390.41,5571.54 4390.41,5633.38 v1(4397.41,5640.37) 4397.41,5665.38 4405.41,5673.38 4413.41,5673.38 ; IC1.49@4412.4,5738.38 4412.4,5674.38 4413.41,5673.38 ; IC1.51@4464.41,5732 4464.41,5679.38 4458.41,5673.38 4413.41,5673.38
  Bottom Layer w6: v1(3931.41,4887.38) 3933.41,4889.38 3933.41,5170.38 4085.41,5322.38 pad.1@4085.41,5410.38 ; pad.1@4085.41,5413.38 pad.1@4085.41,5410.38 ; v1(4397.41,5640.37) 4223.41,5466.38 4136.41,5466.38 4085.41,5415.38 pad.1@4085.41,5410.38
USB_DEVICE_SLOE: IC1.42 IC6.H5 pad.1@3788.4,5413.38 | length 2037.1
  Top Layer w6: v1(3604.41,4186.38) 3623.91,4166.88 IC6.H5@3624.8,4166.88 ; pad.1@3788.4,5413.38 3851.41,5476.38 4067.41,5476.38 4160.41,5569.38 4226.41,5569.38 4239.41,5582.38 IC1.42@4239.41,5732
  L3 w6: v1(3604.41,4186.38) 3626.41,4208.37 3626.41,4286.38 3643.41,4303.38 3643.41,4389.38 3601.41,4431.38 3601.41,4969.38 3685.41,5053.38 3685.41,5271.38 3788.4,5374.38 pad.1@3788.4,5413.38
V+: C147.1 IC26.5 IC34.5
VCC: C140.2 C142.1 IC8.4 IC29.4 L8.2 L9.1 R120.1 | length 2164.7
  Top Layer w6: 2332.41,2081.38 2332.41,2110.38 ; C140.2@2769.95,1770.38 2795.41,1770.38 2830.41,1735.38 IC8.4@2885.41,1735.38 ; R120.1@2937.86,1437.38 2937.86,1502.83 2971.41,1536.38 2971.41,1736.38
  Top Layer w10: IC29.4@2302.05,2305.07 2323.71,2305.07 2332.41,2296.38 2332.41,2126.38 ; 2332.41,2081.38 2332.41,2126.38 ; 2332.41,2110.38 2332.41,2126.38
  Top Layer w20: L8.2@2219.5,1851.38 2219.5,2063.47 2237.41,2081.38 2332.41,2081.38 2956.41,2081.38 2971.41,2066.38 2971.41,1736.38 IC8.4@2869.06,1736.38
  Top Layer w60: L8.2@2206.8,1838.68 L8.2@2219.5,1851.38
VREF_2V048: C88.1 C90.2 C91.1 C93.2 C106.1 C107.1 C130.2 C131.2 C132.1 D22.1 J32.2 R47.2 R54.1 R68.1 R71.1 R72.1 R99.2 R102.1 R105.2 R107.1 R108.2 R113.1 | length 2905
  Top Layer w10: R99.2@372.41,830.92 v1(411.41,830.92) ; v1(429.41,611.38) 437.86,619.83 R71.1@479.41,619.83 ; v1(560.41,663.38) R72.1@609.86,663.38 ; v1(652.41,1519.38) C106.1@711.36,1519.38 ; C90.2@785.5,1010.38 v1(843.41,1010.38) ; v1(824.41,1836.38) 829.06,1831.72 R113.1@875.86,1831.72 ; C93.2@826.95,494.38 855.41,494.38 v1(861.41,500.38) ; C130.2@861.41,1674.92 911.95,1674.92 v1(916.41,1679.38) ; v1(895.41,1055.38) 914.86,1074.83 C88.1@914.86,1094.38 ; v1(913.41,524.38) 922.86,514.92 C132.1@922.86,476.38 ; v1(945.41,545.38) 951.86,551.83 C91.1@951.86,586.38 ; R54.1@1170.41,963.83 1170.41,901.38 v1(1171.41,900.38) ; v1(1179.41,1372.38) 1185.86,1365.92 R107.1@1185.86,1326.38 ; R102.1@1283.41,787.83 1318.95,787.83 1318.95,786.83 v1(1331.41,774.38) ; v1(1394.41,1378.38) 1398.95,1373.83 R108.2@1398.95,1323.38 ; v1(1551.41,1653.38) 1562.95,1641.83 R47.2@1562.95,1607.38 ; v1(1556.41,1368.38) 1560.95,1372.92 R105.2@1560.95,1405.38 ; C131.2@1610.41,732.22 v1(1610.41,788.38)
  Top Layer w15: v1(367.41,920.38) 369.41,918.38 C107.1@421.86,918.38 ; v1(511.41,1238.38) 528.31,1221.48 R68.1@567.99,1221.48
  Top Layer w20: v1(823.41,1950.38) 829.17,1956.14 D22.1@876.7,1956.14
  Bottom Layer w50: 1898.41,2051.38 1943.41,2096.38 3232.41,2096.38 3422.41,1906.38 J32.2@3508.41,1906.38
  Bottom Layer w60: v2(1898.41,1946.38) 1898.41,2051.38
XTAL_OUT: IC1.11 pad.1@4418.41,6220.38 | length 173
  Top Layer w6: IC1.11@4339.41,6100.38 4339.41,6173.38 cw(c4358.72,6173.38) 4345.06,6187.03 4362.41,6204.38 cw(c4401.03,6165.75) 4401.03,6220.38 pad.1@4418.41,6220.38
pads on no net: D9.1 D19.3 D22.3 IC1.5 IC4.4 IC5.3 IC5.5 IC5.8 IC6.A12 IC6.B12 IC6.C9 IC6.F7 IC6.J11 IC6.J12 IC6.J16 IC6.K11 IC6.L11 IC6.L12 IC6.P14 IC6.R1 IC8.11 IC8.15 IC10.7 IC12.1 IC13.3 IC19.11 IC25.3 IC27.3 IC29.1 IC32.3 IC32.6 IC32.9 IC32.10 IC32.11 IC32.12 IC32.13 IC33.8 J7.1 J7.3 J17.1 J32.6 J32.7 J32.8 OP1.3 OP2.6 P1.8 P1.11 P1.18 P1.22 P1.23 P1.24 P1.25 P1.27 P1.28 P1.31 P1.34 P1.36 P1.37 P1.39 TP1.1
copper on no net: | length 2545.3
  Top Layer w6: v3(5169.41,5061.38) 5169.41,5060.38 5229.41,5000.37 5343.41,5000.37 5392.41,4951.38 ; v3(5178.41,4952.37) 5179.41,4951.38 5292.41,4951.38 ; v3(5183.41,4150.38) 5291.41,4150.38 5292.41,4151.38 ; v3(5203.41,4845.38) 5209.41,4851.38 5292.4,4851.38 ; v3(5208.41,5109.38) 5216.41,5101.38 5342.41,5101.38 5354.91,5088.88 5379.91,5063.88 5392.41,5051.38
  Top Layer w10: v1(3329.41,4341.38) 3346.41,4324.38 3349.21,4324.38
  Bottom Layer w6: 2316.41,5416.37 2348.41,5384.37 2348.41,5042.38 2762.41,4628.38 3118.41,4628.38 3232.41,4514.38 3232.41,4399.38 3290.41,4341.38 v1(3329.41,4341.38)
  other v4: 179.35,5625.65 180.41,6646.38 171.41,7110.38 172.41,7473.38 1802.41,7759.38 1108.03,7760.34
  other v5: 4229.41,1461.38 4524.64,1461.51

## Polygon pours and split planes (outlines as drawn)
12V_POWER on Top Layer "Top Layer-12V_POWER" (solid, remove dead copper, pour order 41): 2201.41,6025.38 2201.41,6524.38 2190.41,6535.38 1981.41,6535.38 1968.41,6548.38 1968.41,6986.38 1525.41,6986.38 1262.41,6986.38 1262.41,7156.38 842.41,7156.38 842.41,7556.38 644.41,7556.38 644.41,6923.38 641.41,6920.37 783.41,6920.37 797.41,6906.38 797.41,6827.38 804.41,6820.38 1179.41,6820.38 1186.41,6813.38 1186.41,6661.38 1165.41,6640.37 819.41,6640.37 806.41,6627.38 806.41,6557.38 812.41,6551.38 975.86,6551.38 986.41,6540.83 986.41,6475.98 985.8,6475.38 910.41,6475.38 905.41,6470.38 905.41,6356.38 914.41,6347.38 1059.41,6347.38 1063.41,6343.38 1063.41,6264.37 1070.41,6257.38 1138.41,6257.38 1160.41,6235.38 1160.41,6134.38 1172.41,6122.38 1297.41,6122.38 1301.41,6126.38 1301.41,6222.38 1700.41,6222.38 1700.41,6037.38 1739.41,5998.38 2174.41,5998.38
NetC146_1 on Top Layer "Top Layer-No Net 2" (solid, remove dead copper, pour order 39): 2582.41,806.38 2742.41,806.38 2742.41,826.38 2742.41,946.38 2722.41,946.38 2482.41,946.38 2462.41,946.38 2462.41,826.38 2522.41,826.38 2522.41,806.38 2522.41,746.38 2582.41,746.38
+5VSW on Top Layer "Top Layer-+5VSW" (solid, remove dead copper, pour order 34): 5215.41,1475.38 5215.41,2258.38 5242.41,2285.38 5242.41,2611.38 5243.41,2612.38 5441.41,2612.38 5467.41,2638.36 5467.41,3171.38 5481.41,3171.38 5489.41,3179.38 5489.41,3983.38 5485.41,3987.38 5343.41,3987.38 5340.4,3984.37 5340.4,3527.38 5325.41,3512.38 5240.41,3512.38 5192.41,3464.38 5192.41,3188.38 5204.4,3176.38 5251.41,3176.38 5245.41,3170.38 5245.41,2915.38 5189.41,2859.38 5176.41,2846.38 5176.41,2329.38 5158.41,2311.38 5158.41,1870.38 5136.41,1848.38 5046.75,1848.38 5043.75,1845.38 5043.75,1475.72 5034.41,1466.38 5206.41,1466.38
GND on Top Layer "Top Layer-GND 5" (solid, remove dead copper, pour order 25): 4439.41,4430.38 4439.41,4476.38 4447.41,4484.38 4466.41,4484.38 4486.41,4504.37 4486.41,4518.38 4459.41,4545.38 4459.41,4878.38 4443.41,4894.38 4389.41,4894.38 4361.41,4922.38 4250.41,4922.38 4181.41,4991.38 4085.41,4991.38 4074.41,4991.38 4070.41,4987.38 4070.41,4766.38 4019.41,4715.38 4019.41,4612.38 3985.41,4578.38 3985.41,4577.38 3985.41,4491.98 4157.8,4491.98 4177.41,4472.37 4177.41,4431.38 4191.41,4417.38 4426.41,4417.38
12V_EXT on Top Layer "Top Layer-12V_EXT" (solid, remove dead copper, pour order 27): 1263.41,4634.38 1263.4,5075.38 1236.41,5102.38 918.4,5102.38 896.41,5080.38 896.41,4634.38 913.41,4617.38 1246.41,4617.38
12V_OUT on Top Layer "NONET_L-01_P-001" (solid, remove dead copper, pour order 91): 1992.41,7886.38 2362.41,7886.38 2362.41,7646.38 1992.41,7646.38 1992.41,7636.38
12V_POWER on Top Layer "NONET_L-01_P-001" (solid, remove dead copper, pour order 90): 2832.41,7876.38 2832.41,7696.38 2472.41,7696.38 2472.41,7876.38
GND on Top Layer "Top Layer-GND" (solid, remove dead copper, pour order 40): 616.41,6981.38 616.41,7100.38 483.41,7233.38 483.41,7346.38 502.41,7365.38 617.41,7365.38 617.41,7558.38 33.41,7558.38 33.41,7149.38 448.39,7149.38 509.41,7088.37 509.41,6994.38 522.41,6981.38
VCC on Top Layer "NONET_L-01_P-001" (solid, remove dead copper, pour order 46): 1992.41,1341.38 2197.41,1341.38 2197.41,1681.38 2217.41,1701.38 2267.41,1701.38 2282.41,1716.38 2282.41,1956.38 2017.41,1956.38 1992.41,1931.38
NetD15_1 on Top Layer "Top Layer-VSW" (solid, remove dead copper, pour order 33): 2681.91,1545.88 2801.91,1545.88 2801.91,1631.88 2641.91,1631.88 2641.91,1725.88 2681.91,1725.88 2681.91,1985.88 2521.91,1985.88 2521.91,1405.88 2581.91,1405.88 2681.91,1405.88
12V_POWER on Top Layer "Top Layer-No Net" (solid, remove dead copper, pour order 45): 3302.41,1386.38 3302.41,1506.38 3202.41,1506.38 3202.41,1546.38 3202.41,1606.38 3042.41,1606.38 3042.41,1566.38 3122.41,1566.38 3142.41,1566.38 3142.41,1486.38 3122.41,1486.38 3122.41,1326.38 2782.41,1326.38 2782.41,1226.38 2662.41,1226.38 2662.41,986.38 2782.41,986.38 2782.41,1126.38 2782.41,1166.38 2902.41,1166.38 2902.41,1256.38 3102.55,1256.38 3102.41,1006.38 3072.28,1006.38 3072.51,915.87 3302.41,915.87
-5VA on Top Layer "Top Layer--5VA" (solid, remove dead copper, pour order 44): 1770.41,726.38 1782.41,726.38 1842.41,726.38 1842.41,746.38 1842.41,1106.38 1682.41,1106.38 1662.41,1106.38 1662.41,746.38 1662.41,386.38 1770.41,386.38
NetC111_2 on Top Layer "Top Layer-FANS" (solid, remove dead copper, pour order 43): 405.41,6387.38 405.41,6537.38 426.41,6558.38 546.98,6558.38 548.44,6559.84 548.44,6668.38 543.44,6673.38 371.41,6673.38 373.41,6675.38 373.41,6878.38 389.41,6894.38 443.41,6894.38 448.41,6899.38 448.41,7072.37 444.41,7076.38 261.41,7076.38 237.41,7052.38 237.41,6948.38 222.41,6933.38 222.41,6885.38 209.41,6872.37 87.41,6872.37 36.41,6821.38 36.41,6403.38 57.41,6382.38 400.41,6382.38
V+ on Top Layer "Top Layer-No Net 1" (solid, remove dead copper, pour order 42): 2882.41,800.38 2945.41,800.38 2945.41,827.38 2945.41,918.38 2857.41,918.38 2857.41,986.38 2801.41,986.38 2801.41,974.38 2801.41,883.38 2772.41,883.38 2772.41,852.38 2772.41,780.38 2782.41,780.38 2882.41,780.38
GND on Top Layer "Top Layer-GND 1" (solid, remove dead copper, pour order 38): 3107.41,1376.38 3107.41,1496.38 3122.41,1496.38 3122.41,1546.38 3032.41,1546.38 3032.41,1476.38 3032.41,1406.38 2892.41,1406.38 2892.41,1446.38 2892.41,1516.38 2922.41,1516.38 2922.41,1546.38 2825.41,1546.38 2825.41,1396.38 2802.41,1396.38 2572.41,1396.38 2462.41,1396.38 2462.41,1416.38 2462.41,1606.38 2262.41,1606.38 2262.41,1376.38
NetC146_2 on Top Layer "Top Layer-No Net 3" (solid, remove dead copper, pour order 37): 2502.41,746.38 2502.41,806.38 2422.41,806.38 2422.41,826.38 2422.41,976.38 2442.41,976.38 2442.41,1186.38 2402.41,1186.38 2262.41,1186.38 2262.41,966.38 2302.41,966.38 2322.41,946.38 2382.41,946.38 2382.41,846.38 2382.41,626.38 2422.41,626.38 2502.41,626.38
NetF1_2 on Top Layer "Top Layer-PM_12V_OUT" (solid, remove dead copper, pour order 36): 1531.41,4624.37 1531.41,5101.38 1530.41,5102.38 1287.41,5102.38 1283.41,5098.38 1283.41,4627.38 1296.41,4614.38 1521.41,4614.38
GND on Top Layer "Top Layer-GND 2" (solid, remove dead copper, pour order 35): 2999.83,1002.35 3030.41,1002.38 3030.41,1130.38 2928.41,1130.38 2928.41,1078.38 2928.36,1078.25 2928.41,1056.38 2959.41,1056.38 2959.41,1051.38 2959.41,1028.38 2959.41,1004.38 2909.41,1004.38 2909.41,978.38 2922.41,978.38 2999.83,978.35
NetC144_2 on Top Layer "Top Layer-No Net 4" (solid, remove dead copper, pour order 32): 2222.41,546.38 2222.41,586.38 2222.41,646.38 2162.41,646.38 2162.41,726.38 2182.41,726.38 2182.41,806.38 2182.41,866.38 2262.41,866.38 2302.41,866.38 2302.41,926.38 2282.41,946.38 2225.41,946.38 2225.41,1006.38 2225.41,1186.38 2225.41,1206.38 2622.41,1206.38 2622.41,1366.38 2442.41,1366.38 2262.41,1366.38 2262.41,1307.08 2022.41,1307.08 2022.41,1006.38 2022.41,646.38 2022.41,486.38 2222.41,486.38
12V_POWER on Top Layer "Top Layer-No Net 5" (solid, remove dead copper, pour order 31): 5367.41,1477.38 5306.41,1477.38 5306,1712.5 5485.41,1711.68 5485.41,2466.38 5268.4,2466.38 5242.41,2466.38 5242.41,1376.38 5367.41,1376.38
+5VA on Top Layer "Top Layer-+5VA" (solid, remove dead copper, pour order 30): 1797.41,1338.38 1797.41,1996.38 1652.41,1996.38 1647.41,1991.38 1647.41,1338.38 1658.41,1338.38
NetC71_2 on Top Layer "Top Layer-No Net 6" (solid, remove dead copper, pour order 29): 1665.41,5819.38 1665.41,6157.38 1661.41,6161.38 1412.41,6161.38 1402.41,6151.38 1402.41,5805.38 1415.41,5792.37 1638.41,5792.37
GND on Top Layer "Top Layer-GND 3" (solid, remove dead copper, pour order 28): 2462.41,1606.38 2462.41,1986.38 2462.41,2016.38 2822.41,2016.38 2822.41,1866.38 2832.41,1866.38 2912.41,1866.38 2922.41,1866.38 2922.41,2036.38 2922.41,2046.38 2322.41,2046.38 2322.41,1606.38 2322.41,1536.38 2462.41,1536.38
GND on Top Layer "Top Layer-GND 4" (solid, remove dead copper, pour order 26): 2014.41,5812.38 2014.41,5923.38 1977.41,5960.37 1794.41,5960.37 1791.41,5960.37 1779.41,5948.38 1779.41,5795.38 1796.41,5778.38 1980.41,5778.38
12V_POWER on Bottom Layer "Bottom Layer-12V_POWER" (solid, remove dead copper, pour order 19): 304.91,1681.38 139.91,1681.38 139.91,2818.88 126.91,2831.88 126.91,3478.38 161.91,3513.38 161.91,5403.4 662.91,5403.4 662.91,6792.38 774.91,6792.38 774.91,7644.38 772.91,7644.38 629.91,7644.38 629.91,7129.38 0,7129.38 0,1534.38 304.91,1534.38
NetC99_1 on Bottom Layer "Bottom Layer-No Net 11" (solid, remove dead copper, pour order 11): 472.41,5486.38 472.41,5567.38 466.41,5573.38 414.41,5573.38 403.41,5584.37 403.41,5768.37 411.41,5776.37 475.41,5776.37 481.41,5782.38 481.41,5857.38 476.41,5862.38 470.41,5862.38 376.41,5862.38 361.41,5877.38 284.41,5877.38 264.41,5857.38 264.41,5823.38 257.41,5816.37 209.41,5816.37 208.41,5815.38 208.41,5755.38 215.41,5748.38 342.41,5748.38 349.41,5741.38 349.41,5491.38 366.41,5474.38 460.41,5474.38
NetC111_2 on Bottom Layer "Bottom Layer-No Net 6" (solid, remove dead copper, pour order 17): 405.41,6407.38 405.41,6580.38 410.41,6585.38 514.41,6585.38 523.41,6594.38 523.41,6663.38 512.41,6674.38 404.41,6674.38 399.41,6679.38 399.41,6953.38 393.41,6959.38 212.41,6959.38 211.41,6958.38 211.41,6893.38 205.41,6887.38 163.41,6887.38 160.41,6884.38 160.41,6789.38 170.41,6779.38 302.41,6779.38 309.41,6772.38 309.41,6526.38 296.41,6513.38 214.41,6513.38 211.41,6510.38 211.41,6414.38 223.41,6402.38 400.41,6402.38
12V_OUT on Bottom Layer "Bottom Layer-12V_OUT" (solid, remove dead copper, pour order 15): 2119.81,7226.38 2119.81,7936.37 2016.41,7936.37 2009.41,7929.38 2009.41,7476.38 1979.41,7446.38 828.41,7446.38 820.41,7438.38 820.41,7234.38 828.41,7226.38
GND on Bottom Layer "Bottom Layer-GND" (solid, pour order 9): 2220.41,1305.38 3222.41,1305.38 3222.41,1631.38 3018.41,1631.38 3018.41,1566.38 2900.41,1566.38 2900.41,1707.38 3132.41,1707.38 3132.41,2003.38 3130.41,2003.38 2737.41,2003.38 2735.41,2003.38 2735.41,1730.38 2643.41,1730.38 2643.41,1933.38 2120.41,1933.38 2120.41,2053.38 1979.41,2053.38 1979.41,1295.38 1724.51,1295.38 1724.51,1245.38 2220.41,1245.38
GND on Bottom Layer "Bottom Layer-No Net 1" (solid, pour order 23): 2703.41,810.38 3404.41,810.38 3404.41,1289.38 3404.41,1292.38 2229.41,1292.38 2229.41,1237.38 2209.41,1237.38 2063.41,1237.38 1722.21,1237.38 1722.21,1182.38 1968.41,1182.38 1968.41,734.38 2703.41,734.38
NetC55_2 on Bottom Layer "Bottom Layer-No Net" (solid, remove dead copper, pour order 24): 1273.41,7473.38 1273.41,7532.38 1279.41,7538.38 1346.41,7538.38 1352.41,7544.37 1352.41,7647.38 1337.41,7662.38 1319.41,7662.38 1309.41,7672.37 1309.41,7726.38 1302.41,7733.38 1237.41,7733.38 1225.41,7721.38 1225.41,7551.38 1208.41,7534.38 1208.41,7468.38 1212.41,7464.37 1264.41,7464.37
12V on Bottom Layer "Bottom Layer-No Net 2" (solid, remove dead copper, pour order 22): 1623.41,7462.38 1623.41,7527.38 1634.41,7538.38 1657.71,7538.38 1670.41,7551.08 1670.41,7655.38 1655.41,7670.38 1634.41,7670.38 1626.41,7678.38 1626.41,7726.38 1621.41,7731.38 1558.41,7731.38 1551.41,7724.38 1551.41,7674.38 1538.41,7661.38 1538.41,7465.38 1545.41,7458.38 1619.41,7458.38
NetC96_2 on Bottom Layer "Bottom Layer-No Net 3" (solid, remove dead copper, pour order 21): 478.41,6310.49 418.21,6310.49 409.32,6319.38 409.32,6372.46 404.41,6377.38 400.41,6377.38 287.41,6377.38 275.41,6377.38 259.41,6361.38 259.41,6299.38 257.41,6297.38 205.41,6297.38 202.41,6294.38 202.41,6237.38 211.41,6228.38 478.41,6228.38
NetC54_1 on Bottom Layer "Bottom Layer-No Net 4" (solid, remove dead copper, pour order 20): 1525.41,7475.38 1525.41,7651.38 1509.41,7667.38 1476.41,7667.38 1469.41,7674.38 1469.41,7723.38 1460.41,7732.38 1395.41,7732.38 1384.41,7721.38 1384.41,7685.38 1372.41,7673.38 1372.41,7550.38 1386.41,7536.37 1443.41,7536.37 1451.41,7528.37 1451.41,7473.38 1464.41,7460.38 1510.41,7460.38
NetF5_2 on Bottom Layer "Bottom Layer-No Net 5" (solid, remove dead copper, pour order 18): 970.41,7723.38 993.41,7746.38 993.41,7877.38 1154.41,7877.38 1195.41,7918.38 1345.41,7918.38 1356.41,7907.38 1356.41,7787.38 1367.41,7776.37 1419.41,7776.37 1427.41,7784.37 1427.41,7830.38 1439.41,7842.38 1439.41,7938.38 1435.41,7942.38 822.41,7942.38 822.41,7758.38 822.41,7537.38 827.41,7532.38 955.41,7532.38 970.41,7532.38
NetC100_1 on Bottom Layer "Bottom Layer-No Net 7" (solid, remove dead copper, pour order 16): 842.41,3551.38 841.41,3552.38 673.41,3552.38 656.41,3535.38 463.41,3535.38 425.41,3497.38 425.41,3438.38 343.41,3356.38 343.41,2872.38 346.41,2869.38 842.41,2869.38
NetF7_2 on Bottom Layer "Bottom Layer-No Net 8" (solid, remove dead copper, pour order 14): 1218.41,7569.38 1218.41,7763.38 1228.41,7773.38 1266.41,7773.38 1274.41,7781.38 1274.41,7902.38 1273.41,7903.38 1203.41,7903.38 1146,7845.97 1146,7674.4 1016.43,7674.4 997.41,7655.38 997.41,7534.38 999.41,7532.38 1181.41,7532.38
NetC98_2 on Bottom Layer "Bottom Layer-No Net 9" (solid, remove dead copper, pour order 13): 478.41,5881.38 478.41,5937.38 470.41,5945.38 415.41,5945.38 407.41,5953.38 407.41,6022.38 392.41,6037.38 289.41,6037.38 278.41,6026.38 278.41,5986.38 272.41,5980.38 210.41,5980.38 209.41,5979.38 209.41,5904.37 213.41,5900.38 358.41,5900.38 383.41,5875.38 472.41,5875.38
NetC97_2 on Bottom Layer "Bottom Layer-No Net 10" (solid, remove dead copper, pour order 12): 479.41,6063.38 480.41,6063.38 480.41,6137.38 402.41,6137.38 402.41,6200.37 264.41,6200.37 264.41,6129.38 232.41,6129.38 205.41,6129.38 205.41,6060.35 246.41,6060.35 258.38,6048.37 398.41,6048.37 406.35,6048.04 456.35,6048.04
NetF6_2 on Bottom Layer "Bottom Layer-No Net 12" (solid, remove dead copper, pour order 10): 1980.41,7546.38 1980.41,7933.38 1976.41,7937.38 1526.41,7937.38 1520.41,7931.38 1520.41,7779.38 1525.41,7774.38 1586.41,7774.38 1588.41,7776.37 1588.41,7838.38 1596.41,7846.38 1596.41,7901.38 1603.41,7908.38 1664.41,7908.38 1700.41,7872.37 1700.41,7546.38
GND on L3 "Mid-Layer 1-GND" (solid, remove dead copper, pour order 97): 5.7,24.4 5490.7,24.4 5490.7,7944.4 5.7,7944.4 5.7,2819.4
12V_POWER on L3 "L3-12V_POWER" (solid, remove dead copper, pour order 101): 662.91,5993.48 774.91,5993.48 774.91,5994.33 2184.41,5994.33 2184.41,6964.38 5016.41,6964.38 5016.41,2999.33 5159.41,2999.33 5159.41,2259.33 5449.41,2259.33 5449.41,7299.33 2809.41,7299.33 2809.41,7654.33 2809.41,7868.28 774.91,7868.28 662.91,7868.28
12V_EXT on L3 "NONET_L-01_P-001" (solid, remove dead copper, pour order 83): 1502.41,5386.38 1502.41,4346.38 1142.41,4346.38 1142.41,3646.38 642.41,3646.38 642.41,4346.38 182.41,4346.38 182.41,5386.38
NetF2_2 on L3 "NONET_L-01_P-001" (solid, pour order 102): 422.41,7186.38 652.8,7186.38 652.8,7666.38 422.41,7666.38
VREF_2V048 on L3 "NONET_L-01_P-001" (solid, remove dead copper, pour order 80): 1933.41,2026.38 1933.41,376.38 1202.41,376.38 342.41,376.38 342.41,2026.38
12V_POWER on L3 "NONET_L-01_P-001" (solid, pour order 60): 3122.41,1466.38 3242.41,1466.38 3242.41,1126.38 5202.41,1126.38 5202.41,1446.38 5322.41,1446.38 5322.41,1006.38 3122.41,1006.38 3122.41,1406.38
NetC100_2 on L3 "NONET_L-01_P-001" (solid, pour order 84): 442.41,3386.38 842.41,3386.38 842.41,2886.38 442.41,2886.38
GND on L4 "Mid-Layer 1-GND" (solid, remove dead copper, pour order 92): 5.61,24.28 5490.61,24.28 5490.61,7944.28 5.61,7944.28 5.61,2819.28
+1V2 on L4 "NONET_L-01_P-001" (solid, remove dead copper, pour order 67): 2432.41,4876.38 4442.41,4876.38 4442.41,3416.38 2472.41,3416.38 2432.41,3456.38
NetF2_2 on L4 "NONET_L-01_P-001" (solid, pour order 103): 422.41,7186.38 622.41,7186.38 622.41,7666.38 422.41,7666.38
GND1 on L4 "NONET_L-01_P-001" (solid, remove dead copper, pour order 86): 188.11,5380.28 198.71,5390.88 675.51,5390.88 1502.41,5390.88 1502.41,4312.68 1148.71,4312.68 1143.24,4307.21 1143.24,3626.38 642.41,3626.38 642.41,3907.28 642.41,4346.38 190.41,4346.38 190.41,5377.88 187.81,5380.48
NetC100_1 on L4 "NONET_L-01_P-001" (solid, pour order 87): 202.41,2886.38 842.41,2886.38 842.41,3526.38 322.41,3526.38 322.41,3306.38 202.41,3306.38 202.41,3286.38
+5VA on L4 "NONET_L-01_P-001" (solid, remove dead copper, pour order 72): 182.41,2046.38 1817.91,2046.38 1817.91,401.88 1642.41,226.38 1642.41,146.38 182.41,146.38
3V3 on L5 "NONET_L-01_P-001" (solid, remove dead copper, pour order 68): 1572.41,5386.38 1912.41,5386.38 1912.41,6526.38 1922.41,6536.38 5032.41,6536.38 5032.41,466.38 2862.41,466.38 2862.41,346.38 2742.41,346.38 2742.41,626.38 3952.41,626.38 3952.41,2216.38 3902.41,2266.38 1122.41,2266.38 1122.41,3476.38 1322.41,3476.38 1322.41,4256.38 1572.41,4256.38
GND on L5 "Mid-Layer 1-GND" (solid, remove dead copper, pour order 99): 8.57,20.41 5493.57,20.41 5493.57,7940.41 8.57,7940.41 8.57,2815.41
GND1 on L5 "NONET_L-01_P-001" (solid, remove dead copper, pour order 88): 187.27,5380.28 197.87,5390.88 674.67,5390.88 1501.57,5390.88 1501.57,4312.68 1147.87,4312.68 1142.41,4307.21 1142.41,3626.38 641.57,3626.38 641.57,3907.28 641.57,4346.38 189.57,4346.38 189.57,5377.88 186.97,5380.48
NetC100_1 on L5 "NONET_L-01_P-001" (solid, pour order 89): 202.41,2886.38 842.41,2886.38 842.41,3526.38 322.41,3526.38 322.41,3306.38 202.41,3306.38 202.41,3286.38
-5VA on L5 "NONET_L-01_P-001" (solid, remove dead copper, pour order 73): 322.41,2046.38 1805.41,2046.38 1805.41,389.38 1642.41,226.38 1642.41,146.38 322.41,146.38
GND on L2 "Mid-Layer 1-GND" (solid, remove dead copper, pour order 49): 4.41,24.38 5489.41,24.38 5489.41,7944.38 4.41,7944.38 4.41,2819.38
GND1 on L2 "NONET_L-01_P-001" (solid, remove dead copper, pour order 82): 188.11,5380.28 198.71,5390.88 675.51,5390.88 1502.41,5390.88 1502.41,4312.68 1148.71,4312.68 1143.24,4307.21 1143.24,3626.38 642.41,3626.38 642.41,3907.28 642.41,4346.38 190.41,4346.38 190.41,5377.88 187.81,5380.48
NetC100_1 on L2 "NONET_L-01_P-001" (solid, pour order 85): 202.41,2886.38 842.41,2886.38 842.41,3526.38 322.41,3526.38 322.41,3306.38 202.41,3306.38 202.41,3286.38

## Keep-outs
L2:
  lines w20: 1673.03,1309.55 1673.33,1309.25 1962.26,1309.25 1962.26,2056.25 2122.26,2056.25 2122.26,1927.25 2641.26,1927.25 2642.26,1926.25 2642.26,1726.25 2743.26,1726.25 2743.26,2006.25 3132.26,2006.25 3132.26,1718.25 3130.26,1716.25 2902.26,1716.25 2902.26,1566.25 2912.26,1556.25 3026.26,1556.25 3032.26,1562.25 3032.26,1626.25 3034.26,1628.25 3220.26,1628.25 3222.26,1626.25 3222.26,1296.25 ; 1674.22,1168.66 1674.81,1169.25 1962.26,1169.25 1962.26,736.25 1964.26,734.25 2700.26,734.25 2702.26,736.25 2702.26,816.25 2706.26,820.25 3396.26,820.25 3396.26,1282.25 3383.26,1295.25 3223.26,1295.25 3222.26,1296.25 ; 1920.26,1242.25 2217.26,1242.25 2220.26,1245.25 2220.26,1283.25 2233.26,1296.25 3222.26,1296.25 ; 160.71,4305.48 602.41,4305.48 602.41,3875.68 602.41,3551.48 172.41,3551.48 161.61,3540.68 161.61,2865.78 164.71,2862.68 994.51,2862.68 994.51,3490.68 1002.31,3498.48 1268.91,3498.48 1279.81,3509.38 1279.81,4266.38 1305.81,4266.38 1559.11,4266.38 1559.11,5463.08 199.11,5463.08 160.71,5424.68 160.71,5409.58 160.71,4305.48
L3:
  lines w5: 648.8,7860.9 648.8,7180.8 651.5,7178.1 1049.2,7178.1 1049.2,7116.2 1049.2,5994.8 ; 1323.3,4154.7 1393,4154.7 ; 1550.41,4331.19 1550.41,4340.08
  lines w20: 1281.11,3510.68 1270.21,3499.78 1003.61,3499.78 995.81,3491.98 995.81,2863.98 166.01,2863.98 162.91,2867.08 162.91,3541.98 173.71,3552.78 617.21,3552.78 617.21,3863.48 617.21,4306.78 162.01,4306.78 162.01,5410.88 162.01,5425.98 190.41,5454.38 1550.41,5454.38 1550.41,4340.08 ; 1282.41,3519.38 1282.41,4037.38 ; 1920.26,1242.25 2217.26,1242.25 2220.26,1245.25 2220.26,1283.25 2233.26,1296.25 3084.41,1296.25 3085.41,1295.25 ; 3086.41,1277.12 3086.41,992.38 3102.41,976.38 3391.41,976.38 3396.26,971.53 3396.26,820.25 2706.26,820.25 2702.26,816.25 2702.26,736.25 2700.26,734.25 1945.41,734.25 1945.41,1169.25 1691.41,1169.25 1691.41,1306.38 1948.7,1306.38 1948.7,2056.25 2122.26,2056.25 2122.26,1927.25 2641.26,1927.25 2642.26,1926.25 2642.26,1726.25 2743.26,1726.25 2743.26,2006.25 3132.26,2006.25 3132.26,1718.25 3130.26,1716.25 2902.26,1716.25 2902.26,1566.25 2912.26,1556.25 3026.26,1556.25 3032.26,1562.25 3032.26,1626.25 3034.26,1628.25 3220.26,1628.25 3222.26,1626.25 3222.26,1496.38 3109.41,1496.38 3103.41,1502.38
L4:
  lines w20: 1920.41,1242.38 2217.41,1242.38 2220.41,1245.38 2220.41,1283.38 2233.41,1296.38 3222.41,1296.38 ; 1675.45,1309.4 1675.45,1171.29 1676.54,1170.2 1961.59,1170.2 1962.41,1169.38 1962.41,736.38 1964.41,734.38 2700.41,734.38 2702.41,736.38 2702.41,816.38 2706.41,820.38 3396.41,820.38 3396.41,1282.38 3383.41,1295.38 3223.41,1295.38 3222.41,1296.38 ; 1675.45,1309.4 1675.47,1309.38 ; 1675.47,1309.38 1962.41,1309.38 1962.41,2056.38 2122.41,2056.38 2122.41,1927.38 2641.41,1927.38 2642.41,1926.38 2642.41,1726.38 2743.41,1726.38 2743.41,2006.38 3132.41,2006.38 3131.41,2005.38 3131.41,1717.38 3130.41,1716.38 2902.41,1716.38 2902.41,1566.38 2912.41,1556.38 3026.41,1556.38 3032.41,1562.38 3032.41,1626.38 3034.41,1628.38 3220.41,1628.38 3222.41,1626.38 3222.41,1296.38 ; 161.01,4305.78 602.71,4305.78 602.71,3875.98 602.71,3551.78 172.71,3551.78 161.91,3540.98 161.91,2866.08 165.01,2862.98 994.81,2862.98 994.81,3490.98 1002.61,3498.78 1269.21,3498.78 1280.11,3509.68 1280.11,4266.68 1306.11,4266.68 1559.41,4266.68 1559.41,5463.38 199.41,5463.38 161.01,5424.98 161.01,5409.88 161.01,4305.78
L5:
  lines w20: 1920.41,1242.38 2217.41,1242.38 2220.41,1245.38 2220.41,1283.38 2233.41,1296.38 3222.41,1296.38 ; 1962.18,1169.61 1962.41,1169.38 ; 1962.18,1169.61 1962.41,1169.38 ; 1962.18,1169.61 1685.74,1169.61 1685.22,1170.13 1685.22,1310.04 1685.88,1309.38 1962.41,1309.38 1962.41,2056.38 2122.41,2056.38 2122.41,1927.38 2641.41,1927.38 2642.41,1926.38 2642.41,1726.38 2743.41,1726.38 2743.41,2006.38 3132.41,2006.38 3131.41,2005.38 3131.41,1717.38 3130.41,1716.38 2902.41,1716.38 2902.41,1566.38 2912.41,1556.38 3026.41,1556.38 3032.41,1562.38 3032.41,1626.38 3034.41,1628.38 3220.41,1628.38 3222.41,1626.38 3222.41,1296.38 ; 1962.41,1169.38 1962.41,736.38 1964.41,734.38 2700.41,734.38 2702.41,736.38 2702.41,816.38 2706.41,820.38 3396.41,820.38 3396.41,1282.38 3383.41,1295.38 3223.41,1295.38 3222.41,1296.38 ; 162.01,4304.78 162.01,5408.88 162.01,5423.98 200.41,5462.38 1560.41,5462.38 1560.41,4265.68 1307.11,4265.68 1281.11,4265.68 1281.11,3508.68 1270.21,3497.78 1003.61,3497.78 995.81,3489.98 995.81,2861.98 166.01,2861.98 162.91,2865.08 162.91,3539.98 173.71,3550.78 603.71,3550.78 603.71,3874.98 603.71,4304.78 162.01,4304.78
Bottom Layer:
  lines w5: 405.41,6407.38 412.65,6414.62 412.65,6579.97 516.65,6579.97 531.7,6595.02 531.7,6662.74 512.82,6681.62 404.82,6681.62 405.6,6682.4 405.6,6968.4 404.6,6969.4 202.2,6969.4 200.2,6967.4 200.2,6910.1 193.2,6903.1 190.3,6903.1 189.3,6902.1 157.4,6902.1 149.9,6894.6 149.9,6767.1 150.9,6766.1 279,6766.1 294.99,6750.11 294.99,6526.21 293.58,6524.8 276.6,6524.8 198.5,6524.8 186.9,6513.2 186.9,6416.7 199,6404.6 199,5726.1 319.3,5726.1 327.2,5718.2 327.2,5479.8 346.9,5460.1 460,5460.1 486.2,5486.3 486.2,5570.1 475.3,5581 424.1,5581 414.3,5590.8 414.3,5695.3 413.2,5696.4
  lines w20: 247.6,6391.2 393.7,6391.2 ; 257.23,6043.23 403.33,6043.23 ; 257.62,6213.35 403.72,6213.35
Keep-Out Layer:
  circle w0.5: c5509.41,7946.38 r0.25
  circle w0.5: c5509.41,7946.38 r0.25
  circle w0.5: c5509.41,7946.38 r0.25
  circle w0.5: c5509.41,7946.38 r0.25
  lines w0.25: 236.09,7952.76 cw(c236.22,7952.76) 236.35,7952.76 cw(c236.22,7952.76) 236.09,7952.76 ; 3425.07,7952.76 cw(c3425.2,7952.76) 3425.32,7952.76 cw(c3425.2,7952.76) 3425.07,7952.76 ; 5334.52,7952.76 cw(c5334.65,7952.76) 5334.77,7952.76 cw(c5334.65,7952.76) 5334.52,7952.76
  lines w0.5: 236.22,7952.76 413.39,7952.76 ; 3110.24,7952.76 5511.81,7952.76 ; 3425.2,7952.76 5511.81,7952.76 ; 3503.94,0 5511.81,0 ; 5295.28,0 5511.81,0 ; 5334.65,7952.76 5511.81,7952.76 ; 5511.81,0 0,0 0,7952.76 5511.81,7952.76 ; 5511.81,0 5511.81,7952.76

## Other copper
L3:
  pour cut-out: 5312.41,4276.38 5452.41,4276.38 5452.41,4076.38 5302.41,4076.38 5302.41,4266.38

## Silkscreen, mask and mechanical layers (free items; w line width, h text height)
Top Overlay:
  rectangle: 4469.41,7288.37 4630.41,7543.38
  rectangle: 5011.41,6980.38 5262.41,7669.38
  lines w10: 5342.41,3660.38 5342.41,5953.38 ; 5510.33,3197.46 5510.41,3197.38 ; 4469.41,7288.37 4469.41,7543.38 4630.41,7543.38 4630.41,7288.37 4469.41,7288.37 ; 5011.41,6980.38 5011.41,7669.38 5262.41,7669.38 5262.41,6980.38 5011.41,6980.38
  text "PA312J_S1" at 3974.41,7897.38 h40 r270
  text "PA312J_A1" at 4065.41,7896.38 h40 r270
  text "PA312J" at 4522.41,7878.38 h60 r270
  text "12V" at 1687.41,7573.38 h60 r270
  text "GND" at 5429.41,7521.38 h40 r270
  text "SER.NO." at 5273.41,7479.38 h60 r270
  text "12" at 512.41,7466.38 h60 r270
  text "0V" at 359.41,7460.38 h60 r270
  text "POWER" at 723.21,7425.49 h60 r270
  text "0V" at 1691.41,7403.38 h60 r270
  text "CLOCK2" at 4079.41,7337.38 h60 r270
  text "CLOCK3" at 3480.41,7325.38 h60 r270
  text "CLOCK1" at 4660.41,7321.38 h60 r270
  text "SCOPE1" at 1231.41,7295.38 h60 r270
  text "TOP SIDE FOR" at 3926.41,6895.38 h40 r270
  text "CLOCK CONNECTORS" at 4073.41,6895.38 h40 r270
  text "ON RVERSE" at 4026.41,6894.38 h40 r270
  text "FOR KRONOS" at 3978.41,6892.38 h40 r270
  text "SPOT TESTER" at 3876.41,6891.38 h40 r270
  text "FANS" at 48.41,6885.38 h40 r270
  text "5V" at 2480.41,6853.38 h40 r270
  text "DN" at 2592.41,6850.38 h40 r270
  text "DP" at 2707.41,6848.38 h40 r270
  text "G" at 2796.41,6817.38 h40 r270
  text "S" at 2861.41,6811.38 h40 r270
  text "USB" at 3067.41,6775.38 h40 r270
  text "FPGA" at 3120.41,6773.38 h40 r270
  text "PORT" at 3011.41,6772.38 h40 r270
  text "DIRECT" at 3183.41,6770.38 h40 r270
  text "SPOT TESTER" at 5211.41,6741.38 h40 r270
  text "ON" at 5268.41,6740.38 h40 r270
  text "40 WAY CONNTECTOR" at 5320.41,6737.38 h40 r270
  text "DO NOT FIT J28" at 5382.41,6734.38 h40 r270
  text "+12VF" at 1296.01,6405.34 h60 r270
  text "I/F" at 3074.41,6379.38 h40 r270
  text "MON" at 3133.41,6379.38 h40 r270
  text "BAT" at 3193.41,6379.38 h40 r270
  text "Y" at 2805.41,6161.38 h40 r270
  text "O" at 2908.41,6160.38 h40 r270
  text "B" at 2695.41,6157.38 h40 r270
  text "SERIAL" at 3118.41,6054.38 h40 r270
  text "FPGA" at 3181.41,6052.38 h40 r270
  text "PORT" at 3059.41,6051.38 h40 r270
  text "B" at 2691.41,5809.38 h40 r270
  text "Y" at 2799.41,5809.38 h40 r270
  text "O" at 2914.41,5806.38 h40 r270
  text "COMPUTER" at 3187.41,5780.38 h40 r270
  text "SERIAL" at 3129.41,5778.38 h40 r270
  text "PORT" at 3066.41,5776.38 h40 r270
  text "0" at 5191.41,5771.38 h40 r270
  text "0V" at 524.41,5709.38 h60 r270
  text "MUX" at 330.41,5570.38 h40 r270
  text "0" at 284.41,5361.38 h40 r270
  text "SERIAL EXPANSION" at 342.41,5314.38 h40 r270
  text "15" at 284.41,5288.38 h40 r270
  text "TX" at 282.41,5189.38 h40 r270
  text "USB" at 3215.41,5126.38 h40 r270
  text "EEPROM" at 3157.41,5123.55 h40 r270
  text "SK10" at 3077.41,5079.98 h40 r270
  text "RX" at 285.41,5070.38 h40 r270
  text "0" at 5236.41,5036.38 h40 r90
  text "RASPBERRY" at 5108.41,4879.38 h40 r270
  text "PROG_B" at 3094.08,4856.88 h40 r270
  text "+1V2" at 2587.41,4845.22 h40 r270
  text "0" at 290.41,4805.38 h40 r270
  text "3V3" at 2212.41,4745.32 h40 r270
  text "15" at 290.41,4732.38 h40 r270
  text "TX" at 288.41,4633.38 h40 r270
  text "15V_EXT" at 887.48,4618.05 h40
  text "RX" at 291.41,4514.38 h40 r270
  text "TMS" at 5124.41,4338.38 h40
  text "GND" at 1232.41,4316.38 h40
  text "TRIGGER" at 1687.41,4275.83 h40 r270
  text "EXTERNAL" at 1747.41,4274.3 h40 r270
  text "FAST" at 1807.41,4272.08 h40 r270
  text "0V" at 5163.41,4230.38 h40
  text "SCL" at 5135.41,4032.38 h40
  text "SDA" at 5136.41,3925.38 h40
  text "3V" at 5185.41,3879.38 h40 r270
  text "RS485" at 373.41,3587.38 h60 r270
  text "0" at 346.41,3453.38 h40 r90
  text "DONE" at 2272.41,3435.32 h40 r270
  text "12" at 307.41,3390.38 h40 r270
  text "A+" at 307.41,3286.38 h40 r270
  text "A-" at 307.41,3191.38 h40 r270
  text "T-" at 300.41,3083.38 h40 r270
  text "T+" at 299.41,2986.38 h40 r270
  text "+5VSW" at 5207.41,2979.63 h60 r270
  text "SYNC" at 2972.41,2789.38 h40 r270
  text "INT" at 3025.41,2783.38 h40 r270
  text "11" at 3990.41,2675.38 h40 r270
  text "18" at 3297.41,2674.38 h40 r270
  text "19" at 3196.41,2672.38 h40 r270
  text "17" at 3389.41,2671.38 h40 r270
  text "15" at 3588.41,2671.38 h40 r270
  text "20" at 3092.41,2670.38 h40 r270
  text "13" at 3784.41,2670.38 h40 r270
  text "14" at 3686.41,2669.38 h40 r270
  text "10" at 4088.41,2668.38 h40 r270
  text "12" at 3883.41,2666.38 h40 r270
  text "16" at 3490.41,2665.38 h40 r270
  text "9" at 4191.41,2656.38 h40 r270
  text "7" at 4389.41,2656.38 h40 r270
  text "6" at 4493.41,2650.38 h40 r270
  text "4" at 4689.41,2650.38 h40 r270
  text "2" at 4885.41,2650.38 h40 r270
  text "3" at 4782.41,2649.38 h40 r270
  text "8" at 4287.41,2648.38 h40 r270
  text "1" at 4986.41,2647.38 h40 r270
  text "5" at 4588.41,2642.38 h40 r270
  text "CAL" at 2692.41,2607.38 h40 r270
  text "FREO" at 2636.41,2597.38 h40 r270
  text "SYNC" at 2493.41,2496.38 h40 r270
  text "IND" at 2541.41,2492.38 h40 r270
  text "SYNC" at 2957.41,2430.12 h40 r270
  text "EXT" at 3012.41,2428.22 h40 r270
  text "SINE" at 1022.41,2376.38 h40 r270
  text "CAL" at 1080.41,2375.38 h40 r270
  text "OPT" at 2727.41,2237.38 h40 r270
  text "SYNC" at 2676.41,2232.38 h40 r270
  text "EXPANSION" at 3841.41,2114.38 h60 r270
  text "BOARD" at 3762.41,2112.38 h60 r270
  text "+5VA" at 1668.41,2043.38 h40 r270
  text "1" at 3571.41,2017.38 h40 r270
  text "T+" at 298.41,1951.38 h40 r270
  text "CAL" at 379.41,1938.38 h60 r270
  text "2" at 3568.41,1914.38 h40 r270
  text "CM" at 293.41,1866.38 h40 r270
  text "3" at 3568.41,1813.38 h40 r270
  text "C0" at 296.41,1764.38 h40 r270
  text "4" at 3570.41,1729.38 h40 r270
  text "SW" at 376.41,1723.38 h60 r270
  text "12" at 294.41,1651.38 h40 r270
  text "5" at 3570.41,1608.38 h40 r270
  text "6" at 3571.41,1510.38 h40 r270
  text "GND" at 298.8,1503.44 h40 r270
  text "7" at 3569.41,1410.38 h40 r270
  text "SIG" at 296.9,1373.48 h40 r270
  text "8" at 3570.41,1311.38 h40 r270
  text "0" at 299.7,1261.73 h40 r270
  text "DISPLAY" at 5161.41,1164.38 h60 r270
  text "EXT" at 99.41,1149.38 h40 r270
  text "50" at 28.41,1147.38 h40 r270
  text "0" at 5088.41,1114.38 h40 r270
  text "D" at 5087.41,1004.38 h40 r270
  text "-" at 294.41,927.38 h40 r270
  text "5" at 5088.41,893.38 h40 r270
  text "+" at 291.41,837.38 h40 r270
  text "11" at 3785.41,832.38 h40 r270
  text "18" at 3092.41,831.38 h40 r270
  text "17" at 3184.41,828.38 h40 r270
  text "15" at 3383.41,828.38 h40 r270
  text "13" at 3579.41,827.38 h40 r270
  text "14" at 3481.41,826.38 h40 r270
  text "10" at 3883.41,825.38 h40 r270
  text "12" at 3678.41,823.38 h40 r270
  text "16" at 3285.41,822.38 h40 r270
  text "9" at 3986.41,813.38 h40 r270
  text "7" at 4184.41,813.38 h40 r270
  text "6" at 4288.41,807.38 h40 r270
  text "4" at 4484.41,807.38 h40 r270
  text "2" at 4680.41,807.38 h40 r270
  text "3" at 4577.41,806.38 h40 r270
  text "8" at 4082.41,805.38 h40 r270
  text "1" at 4781.41,804.38 h40 r270
  text "5" at 4383.41,799.38 h40 r270
  text "0" at 290.41,729.38 h40 r270
  text "GND" at 3667.41,607.41 h40 r270
  text "INT50" at 51.41,586.38 h60
  text "O" at 282.41,543.38 h40 r270
  text "MFD50" at 334.41,521.38 h60 r270
  text "-" at 1274.41,509.38 h40 r270
  text "SW2" at 4257.41,445.38 h60 r270
  text "SW1" at 4414.41,441.38 h60 r270
  text "-5VA" at 1773.52,436.38 h40
  text "I" at 282.41,416.38 h40 r270
  text "0" at 1277.41,396.38 h40 r270
  text "HW" at 4629.41,394.38 h60 r270
  text "5" at 281.41,337.38 h40 r270
  text "TRIG3" at 2872.41,306.21 h60 r270
  text "TRIG1" at 1667.41,301.38 h60 r270
  text "TRIG2" at 2247.41,301.38 h60 r270
  text "+" at 1280.41,293.38 h40 r270
  text "LEDS" at 5055.41,264.38 h60 r270
  text "PELT" at 4141.41,252.38 h60 r270
  text "0" at 285.41,235.38 h40 r270
Bottom Overlay:
  text "FIT LOSWER SMA" at 4648.97,7439.7 h60 r270
  text "ON KRONOS" at 4530.17,7438.2 h60 r270
  text "CONNECTORS" at 4593.37,7438.2 h60 r270
  text "NOT SPOT TESTER" at 4462.47,7435.2 h60 r270
Mechanical 1:
  region: 5435.83,3882.87 5435.83,3819.88 5372.84,3819.88 5372.84,3882.87
  region: 5435.83,3882.87 5435.83,3819.88 5372.84,3819.88 5372.84,3882.87
  lines w0.5: 118.11,3976.38 236.22,3976.38 ; 236.22,3858.27 236.22,3976.38 ; 236.22,4094.49 236.22,3976.38 ; 236.22,7952.76 413.39,7952.76 ; 3110.24,7952.76 5511.81,7952.76 ; 3425.2,7952.76 5511.81,7952.76 ; 3503.94,0 5511.81,0 ; 5295.28,0 5511.81,0 ; 5334.65,7952.76 5511.81,7952.76 ; 5511.81,0 5511.81,7952.76 ; 5511.81,0 0,0 0,7952.76 5511.81,7952.76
